VERSION 5.8 ;
BUSBITCHARS "[]" ;
DIVIDERCHAR "/" ;
UNITS
    DATABASE MICRONS 1000 ;
END UNITS

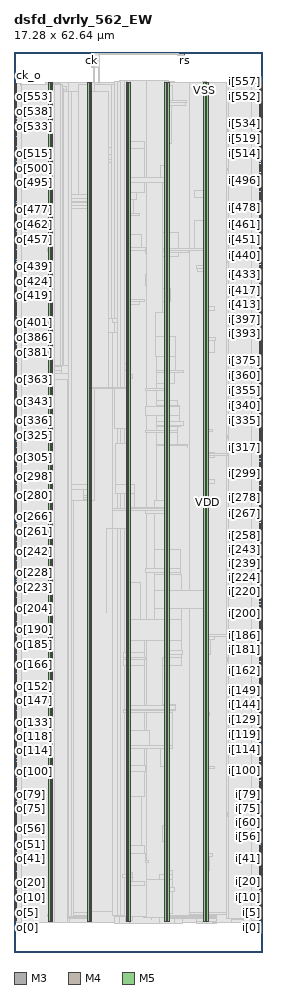
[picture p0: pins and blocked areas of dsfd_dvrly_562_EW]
MACRO dsfd_dvrly_562_EW
  FOREIGN dsfd_dvrly_562_EW 0 0 ;
  CLASS BLOCK ;
  SIZE 17.28 BY 62.64 ;
  PIN ck
    DIRECTION INPUT ;
    USE SIGNAL ;
    PORT
      LAYER M3 ;
        RECT  5.4 62.496 5.418 62.64 ;
    END
  END ck
  PIN ck_o
    DIRECTION OUTPUT ;
    USE SIGNAL ;
    PORT
      LAYER M4 ;
        RECT  0 60.432 0.192 60.456 ;
    END
  END ck_o
  PIN i[0]
    DIRECTION INPUT ;
    USE SIGNAL ;
    PORT
      LAYER M4 ;
        RECT  17.088 2.208 17.28 2.232 ;
    END
  END i[0]
  PIN i[100]
    DIRECTION INPUT ;
    USE SIGNAL ;
    PORT
      LAYER M4 ;
        RECT  17.088 12.624 17.28 12.648 ;
    END
  END i[100]
  PIN i[101]
    DIRECTION INPUT ;
    USE SIGNAL ;
    PORT
      LAYER M4 ;
        RECT  17.088 12.72 17.28 12.744 ;
    END
  END i[101]
  PIN i[102]
    DIRECTION INPUT ;
    USE SIGNAL ;
    PORT
      LAYER M4 ;
        RECT  17.088 12.816 17.28 12.84 ;
    END
  END i[102]
  PIN i[103]
    DIRECTION INPUT ;
    USE SIGNAL ;
    PORT
      LAYER M4 ;
        RECT  17.088 12.912 17.28 12.936 ;
    END
  END i[103]
  PIN i[104]
    DIRECTION INPUT ;
    USE SIGNAL ;
    PORT
      LAYER M4 ;
        RECT  17.088 13.008 17.28 13.032 ;
    END
  END i[104]
  PIN i[105]
    DIRECTION INPUT ;
    USE SIGNAL ;
    PORT
      LAYER M4 ;
        RECT  17.088 13.104 17.28 13.128 ;
    END
  END i[105]
  PIN i[106]
    DIRECTION INPUT ;
    USE SIGNAL ;
    PORT
      LAYER M4 ;
        RECT  17.088 13.2 17.28 13.224 ;
    END
  END i[106]
  PIN i[107]
    DIRECTION INPUT ;
    USE SIGNAL ;
    PORT
      LAYER M4 ;
        RECT  17.088 13.344 17.28 13.368 ;
    END
  END i[107]
  PIN i[108]
    DIRECTION INPUT ;
    USE SIGNAL ;
    PORT
      LAYER M4 ;
        RECT  17.088 13.44 17.28 13.464 ;
    END
  END i[108]
  PIN i[109]
    DIRECTION INPUT ;
    USE SIGNAL ;
    PORT
      LAYER M4 ;
        RECT  17.088 13.536 17.28 13.56 ;
    END
  END i[109]
  PIN i[10]
    DIRECTION INPUT ;
    USE SIGNAL ;
    PORT
      LAYER M4 ;
        RECT  17.088 3.264 17.28 3.288 ;
    END
  END i[10]
  PIN i[110]
    DIRECTION INPUT ;
    USE SIGNAL ;
    PORT
      LAYER M4 ;
        RECT  17.088 13.632 17.28 13.656 ;
    END
  END i[110]
  PIN i[111]
    DIRECTION INPUT ;
    USE SIGNAL ;
    PORT
      LAYER M4 ;
        RECT  17.088 13.728 17.28 13.752 ;
    END
  END i[111]
  PIN i[112]
    DIRECTION INPUT ;
    USE SIGNAL ;
    PORT
      LAYER M4 ;
        RECT  17.088 13.824 17.28 13.848 ;
    END
  END i[112]
  PIN i[113]
    DIRECTION INPUT ;
    USE SIGNAL ;
    PORT
      LAYER M4 ;
        RECT  17.088 13.968 17.28 13.992 ;
    END
  END i[113]
  PIN i[114]
    DIRECTION INPUT ;
    USE SIGNAL ;
    PORT
      LAYER M4 ;
        RECT  17.088 14.064 17.28 14.088 ;
    END
  END i[114]
  PIN i[115]
    DIRECTION INPUT ;
    USE SIGNAL ;
    PORT
      LAYER M4 ;
        RECT  17.088 14.16 17.28 14.184 ;
    END
  END i[115]
  PIN i[116]
    DIRECTION INPUT ;
    USE SIGNAL ;
    PORT
      LAYER M4 ;
        RECT  17.088 14.256 17.28 14.28 ;
    END
  END i[116]
  PIN i[117]
    DIRECTION INPUT ;
    USE SIGNAL ;
    PORT
      LAYER M4 ;
        RECT  17.088 14.352 17.28 14.376 ;
    END
  END i[117]
  PIN i[118]
    DIRECTION INPUT ;
    USE SIGNAL ;
    PORT
      LAYER M4 ;
        RECT  17.088 14.448 17.28 14.472 ;
    END
  END i[118]
  PIN i[119]
    DIRECTION INPUT ;
    USE SIGNAL ;
    PORT
      LAYER M4 ;
        RECT  17.088 14.592 17.28 14.616 ;
    END
  END i[119]
  PIN i[11]
    DIRECTION INPUT ;
    USE SIGNAL ;
    PORT
      LAYER M4 ;
        RECT  17.088 3.36 17.28 3.384 ;
    END
  END i[11]
  PIN i[120]
    DIRECTION INPUT ;
    USE SIGNAL ;
    PORT
      LAYER M4 ;
        RECT  17.088 14.688 17.28 14.712 ;
    END
  END i[120]
  PIN i[121]
    DIRECTION INPUT ;
    USE SIGNAL ;
    PORT
      LAYER M4 ;
        RECT  17.088 14.784 17.28 14.808 ;
    END
  END i[121]
  PIN i[122]
    DIRECTION INPUT ;
    USE SIGNAL ;
    PORT
      LAYER M4 ;
        RECT  17.088 14.88 17.28 14.904 ;
    END
  END i[122]
  PIN i[123]
    DIRECTION INPUT ;
    USE SIGNAL ;
    PORT
      LAYER M4 ;
        RECT  17.088 14.976 17.28 15 ;
    END
  END i[123]
  PIN i[124]
    DIRECTION INPUT ;
    USE SIGNAL ;
    PORT
      LAYER M4 ;
        RECT  17.088 15.072 17.28 15.096 ;
    END
  END i[124]
  PIN i[125]
    DIRECTION INPUT ;
    USE SIGNAL ;
    PORT
      LAYER M4 ;
        RECT  17.088 15.216 17.28 15.24 ;
    END
  END i[125]
  PIN i[126]
    DIRECTION INPUT ;
    USE SIGNAL ;
    PORT
      LAYER M4 ;
        RECT  17.088 15.312 17.28 15.336 ;
    END
  END i[126]
  PIN i[127]
    DIRECTION INPUT ;
    USE SIGNAL ;
    PORT
      LAYER M4 ;
        RECT  17.088 15.408 17.28 15.432 ;
    END
  END i[127]
  PIN i[128]
    DIRECTION INPUT ;
    USE SIGNAL ;
    PORT
      LAYER M4 ;
        RECT  17.088 15.504 17.28 15.528 ;
    END
  END i[128]
  PIN i[129]
    DIRECTION INPUT ;
    USE SIGNAL ;
    PORT
      LAYER M4 ;
        RECT  17.088 15.6 17.28 15.624 ;
    END
  END i[129]
  PIN i[12]
    DIRECTION INPUT ;
    USE SIGNAL ;
    PORT
      LAYER M4 ;
        RECT  17.088 3.456 17.28 3.48 ;
    END
  END i[12]
  PIN i[130]
    DIRECTION INPUT ;
    USE SIGNAL ;
    PORT
      LAYER M4 ;
        RECT  17.088 15.696 17.28 15.72 ;
    END
  END i[130]
  PIN i[131]
    DIRECTION INPUT ;
    USE SIGNAL ;
    PORT
      LAYER M4 ;
        RECT  17.088 15.84 17.28 15.864 ;
    END
  END i[131]
  PIN i[132]
    DIRECTION INPUT ;
    USE SIGNAL ;
    PORT
      LAYER M4 ;
        RECT  17.088 15.936 17.28 15.96 ;
    END
  END i[132]
  PIN i[133]
    DIRECTION INPUT ;
    USE SIGNAL ;
    PORT
      LAYER M4 ;
        RECT  17.088 16.032 17.28 16.056 ;
    END
  END i[133]
  PIN i[134]
    DIRECTION INPUT ;
    USE SIGNAL ;
    PORT
      LAYER M4 ;
        RECT  17.088 16.128 17.28 16.152 ;
    END
  END i[134]
  PIN i[135]
    DIRECTION INPUT ;
    USE SIGNAL ;
    PORT
      LAYER M4 ;
        RECT  17.088 16.224 17.28 16.248 ;
    END
  END i[135]
  PIN i[136]
    DIRECTION INPUT ;
    USE SIGNAL ;
    PORT
      LAYER M4 ;
        RECT  17.088 16.32 17.28 16.344 ;
    END
  END i[136]
  PIN i[137]
    DIRECTION INPUT ;
    USE SIGNAL ;
    PORT
      LAYER M4 ;
        RECT  17.088 16.464 17.28 16.488 ;
    END
  END i[137]
  PIN i[138]
    DIRECTION INPUT ;
    USE SIGNAL ;
    PORT
      LAYER M4 ;
        RECT  17.088 16.56 17.28 16.584 ;
    END
  END i[138]
  PIN i[139]
    DIRECTION INPUT ;
    USE SIGNAL ;
    PORT
      LAYER M4 ;
        RECT  17.088 16.656 17.28 16.68 ;
    END
  END i[139]
  PIN i[13]
    DIRECTION INPUT ;
    USE SIGNAL ;
    PORT
      LAYER M4 ;
        RECT  17.088 3.552 17.28 3.576 ;
    END
  END i[13]
  PIN i[140]
    DIRECTION INPUT ;
    USE SIGNAL ;
    PORT
      LAYER M4 ;
        RECT  17.088 16.752 17.28 16.776 ;
    END
  END i[140]
  PIN i[141]
    DIRECTION INPUT ;
    USE SIGNAL ;
    PORT
      LAYER M4 ;
        RECT  17.088 16.848 17.28 16.872 ;
    END
  END i[141]
  PIN i[142]
    DIRECTION INPUT ;
    USE SIGNAL ;
    PORT
      LAYER M4 ;
        RECT  17.088 16.944 17.28 16.968 ;
    END
  END i[142]
  PIN i[143]
    DIRECTION INPUT ;
    USE SIGNAL ;
    PORT
      LAYER M4 ;
        RECT  17.088 17.04 17.28 17.064 ;
    END
  END i[143]
  PIN i[144]
    DIRECTION INPUT ;
    USE SIGNAL ;
    PORT
      LAYER M4 ;
        RECT  17.088 17.184 17.28 17.208 ;
    END
  END i[144]
  PIN i[145]
    DIRECTION INPUT ;
    USE SIGNAL ;
    PORT
      LAYER M4 ;
        RECT  17.088 17.28 17.28 17.304 ;
    END
  END i[145]
  PIN i[146]
    DIRECTION INPUT ;
    USE SIGNAL ;
    PORT
      LAYER M4 ;
        RECT  17.088 17.376 17.28 17.4 ;
    END
  END i[146]
  PIN i[147]
    DIRECTION INPUT ;
    USE SIGNAL ;
    PORT
      LAYER M4 ;
        RECT  17.088 17.472 17.28 17.496 ;
    END
  END i[147]
  PIN i[148]
    DIRECTION INPUT ;
    USE SIGNAL ;
    PORT
      LAYER M4 ;
        RECT  17.088 17.568 17.28 17.592 ;
    END
  END i[148]
  PIN i[149]
    DIRECTION INPUT ;
    USE SIGNAL ;
    PORT
      LAYER M4 ;
        RECT  17.088 17.664 17.28 17.688 ;
    END
  END i[149]
  PIN i[14]
    DIRECTION INPUT ;
    USE SIGNAL ;
    PORT
      LAYER M4 ;
        RECT  17.088 3.696 17.28 3.72 ;
    END
  END i[14]
  PIN i[150]
    DIRECTION INPUT ;
    USE SIGNAL ;
    PORT
      LAYER M4 ;
        RECT  17.088 17.808 17.28 17.832 ;
    END
  END i[150]
  PIN i[151]
    DIRECTION INPUT ;
    USE SIGNAL ;
    PORT
      LAYER M4 ;
        RECT  17.088 17.904 17.28 17.928 ;
    END
  END i[151]
  PIN i[152]
    DIRECTION INPUT ;
    USE SIGNAL ;
    PORT
      LAYER M4 ;
        RECT  17.088 18 17.28 18.024 ;
    END
  END i[152]
  PIN i[153]
    DIRECTION INPUT ;
    USE SIGNAL ;
    PORT
      LAYER M4 ;
        RECT  17.088 18.096 17.28 18.12 ;
    END
  END i[153]
  PIN i[154]
    DIRECTION INPUT ;
    USE SIGNAL ;
    PORT
      LAYER M4 ;
        RECT  17.088 18.192 17.28 18.216 ;
    END
  END i[154]
  PIN i[155]
    DIRECTION INPUT ;
    USE SIGNAL ;
    PORT
      LAYER M4 ;
        RECT  17.088 18.288 17.28 18.312 ;
    END
  END i[155]
  PIN i[156]
    DIRECTION INPUT ;
    USE SIGNAL ;
    PORT
      LAYER M4 ;
        RECT  17.088 18.432 17.28 18.456 ;
    END
  END i[156]
  PIN i[157]
    DIRECTION INPUT ;
    USE SIGNAL ;
    PORT
      LAYER M4 ;
        RECT  17.088 18.528 17.28 18.552 ;
    END
  END i[157]
  PIN i[158]
    DIRECTION INPUT ;
    USE SIGNAL ;
    PORT
      LAYER M4 ;
        RECT  17.088 18.624 17.28 18.648 ;
    END
  END i[158]
  PIN i[159]
    DIRECTION INPUT ;
    USE SIGNAL ;
    PORT
      LAYER M4 ;
        RECT  17.088 18.72 17.28 18.744 ;
    END
  END i[159]
  PIN i[15]
    DIRECTION INPUT ;
    USE SIGNAL ;
    PORT
      LAYER M4 ;
        RECT  17.088 3.792 17.28 3.816 ;
    END
  END i[15]
  PIN i[160]
    DIRECTION INPUT ;
    USE SIGNAL ;
    PORT
      LAYER M4 ;
        RECT  17.088 18.816 17.28 18.84 ;
    END
  END i[160]
  PIN i[161]
    DIRECTION INPUT ;
    USE SIGNAL ;
    PORT
      LAYER M4 ;
        RECT  17.088 18.912 17.28 18.936 ;
    END
  END i[161]
  PIN i[162]
    DIRECTION INPUT ;
    USE SIGNAL ;
    PORT
      LAYER M4 ;
        RECT  17.088 19.056 17.28 19.08 ;
    END
  END i[162]
  PIN i[163]
    DIRECTION INPUT ;
    USE SIGNAL ;
    PORT
      LAYER M4 ;
        RECT  17.088 19.152 17.28 19.176 ;
    END
  END i[163]
  PIN i[164]
    DIRECTION INPUT ;
    USE SIGNAL ;
    PORT
      LAYER M4 ;
        RECT  17.088 19.248 17.28 19.272 ;
    END
  END i[164]
  PIN i[165]
    DIRECTION INPUT ;
    USE SIGNAL ;
    PORT
      LAYER M4 ;
        RECT  17.088 19.344 17.28 19.368 ;
    END
  END i[165]
  PIN i[166]
    DIRECTION INPUT ;
    USE SIGNAL ;
    PORT
      LAYER M4 ;
        RECT  17.088 19.44 17.28 19.464 ;
    END
  END i[166]
  PIN i[167]
    DIRECTION INPUT ;
    USE SIGNAL ;
    PORT
      LAYER M4 ;
        RECT  17.088 19.536 17.28 19.56 ;
    END
  END i[167]
  PIN i[168]
    DIRECTION INPUT ;
    USE SIGNAL ;
    PORT
      LAYER M4 ;
        RECT  17.088 19.68 17.28 19.704 ;
    END
  END i[168]
  PIN i[169]
    DIRECTION INPUT ;
    USE SIGNAL ;
    PORT
      LAYER M4 ;
        RECT  17.088 19.776 17.28 19.8 ;
    END
  END i[169]
  PIN i[16]
    DIRECTION INPUT ;
    USE SIGNAL ;
    PORT
      LAYER M4 ;
        RECT  17.088 3.888 17.28 3.912 ;
    END
  END i[16]
  PIN i[170]
    DIRECTION INPUT ;
    USE SIGNAL ;
    PORT
      LAYER M4 ;
        RECT  17.088 19.872 17.28 19.896 ;
    END
  END i[170]
  PIN i[171]
    DIRECTION INPUT ;
    USE SIGNAL ;
    PORT
      LAYER M4 ;
        RECT  17.088 19.968 17.28 19.992 ;
    END
  END i[171]
  PIN i[172]
    DIRECTION INPUT ;
    USE SIGNAL ;
    PORT
      LAYER M4 ;
        RECT  17.088 20.064 17.28 20.088 ;
    END
  END i[172]
  PIN i[173]
    DIRECTION INPUT ;
    USE SIGNAL ;
    PORT
      LAYER M4 ;
        RECT  17.088 20.16 17.28 20.184 ;
    END
  END i[173]
  PIN i[174]
    DIRECTION INPUT ;
    USE SIGNAL ;
    PORT
      LAYER M4 ;
        RECT  17.088 20.304 17.28 20.328 ;
    END
  END i[174]
  PIN i[175]
    DIRECTION INPUT ;
    USE SIGNAL ;
    PORT
      LAYER M4 ;
        RECT  17.088 20.4 17.28 20.424 ;
    END
  END i[175]
  PIN i[176]
    DIRECTION INPUT ;
    USE SIGNAL ;
    PORT
      LAYER M4 ;
        RECT  17.088 20.496 17.28 20.52 ;
    END
  END i[176]
  PIN i[177]
    DIRECTION INPUT ;
    USE SIGNAL ;
    PORT
      LAYER M4 ;
        RECT  17.088 20.592 17.28 20.616 ;
    END
  END i[177]
  PIN i[178]
    DIRECTION INPUT ;
    USE SIGNAL ;
    PORT
      LAYER M4 ;
        RECT  17.088 20.688 17.28 20.712 ;
    END
  END i[178]
  PIN i[179]
    DIRECTION INPUT ;
    USE SIGNAL ;
    PORT
      LAYER M4 ;
        RECT  17.088 20.784 17.28 20.808 ;
    END
  END i[179]
  PIN i[17]
    DIRECTION INPUT ;
    USE SIGNAL ;
    PORT
      LAYER M4 ;
        RECT  17.088 3.984 17.28 4.008 ;
    END
  END i[17]
  PIN i[180]
    DIRECTION INPUT ;
    USE SIGNAL ;
    PORT
      LAYER M4 ;
        RECT  17.088 20.88 17.28 20.904 ;
    END
  END i[180]
  PIN i[181]
    DIRECTION INPUT ;
    USE SIGNAL ;
    PORT
      LAYER M4 ;
        RECT  17.088 21.024 17.28 21.048 ;
    END
  END i[181]
  PIN i[182]
    DIRECTION INPUT ;
    USE SIGNAL ;
    PORT
      LAYER M4 ;
        RECT  17.088 21.12 17.28 21.144 ;
    END
  END i[182]
  PIN i[183]
    DIRECTION INPUT ;
    USE SIGNAL ;
    PORT
      LAYER M4 ;
        RECT  17.088 21.216 17.28 21.24 ;
    END
  END i[183]
  PIN i[184]
    DIRECTION INPUT ;
    USE SIGNAL ;
    PORT
      LAYER M4 ;
        RECT  17.088 21.312 17.28 21.336 ;
    END
  END i[184]
  PIN i[185]
    DIRECTION INPUT ;
    USE SIGNAL ;
    PORT
      LAYER M4 ;
        RECT  17.088 21.408 17.28 21.432 ;
    END
  END i[185]
  PIN i[186]
    DIRECTION INPUT ;
    USE SIGNAL ;
    PORT
      LAYER M4 ;
        RECT  17.088 21.504 17.28 21.528 ;
    END
  END i[186]
  PIN i[187]
    DIRECTION INPUT ;
    USE SIGNAL ;
    PORT
      LAYER M4 ;
        RECT  17.088 21.648 17.28 21.672 ;
    END
  END i[187]
  PIN i[188]
    DIRECTION INPUT ;
    USE SIGNAL ;
    PORT
      LAYER M4 ;
        RECT  17.088 21.744 17.28 21.768 ;
    END
  END i[188]
  PIN i[189]
    DIRECTION INPUT ;
    USE SIGNAL ;
    PORT
      LAYER M4 ;
        RECT  17.088 21.84 17.28 21.864 ;
    END
  END i[189]
  PIN i[18]
    DIRECTION INPUT ;
    USE SIGNAL ;
    PORT
      LAYER M4 ;
        RECT  17.088 4.08 17.28 4.104 ;
    END
  END i[18]
  PIN i[190]
    DIRECTION INPUT ;
    USE SIGNAL ;
    PORT
      LAYER M4 ;
        RECT  17.088 21.936 17.28 21.96 ;
    END
  END i[190]
  PIN i[191]
    DIRECTION INPUT ;
    USE SIGNAL ;
    PORT
      LAYER M4 ;
        RECT  17.088 22.032 17.28 22.056 ;
    END
  END i[191]
  PIN i[192]
    DIRECTION INPUT ;
    USE SIGNAL ;
    PORT
      LAYER M4 ;
        RECT  17.088 22.128 17.28 22.152 ;
    END
  END i[192]
  PIN i[193]
    DIRECTION INPUT ;
    USE SIGNAL ;
    PORT
      LAYER M4 ;
        RECT  17.088 22.272 17.28 22.296 ;
    END
  END i[193]
  PIN i[194]
    DIRECTION INPUT ;
    USE SIGNAL ;
    PORT
      LAYER M4 ;
        RECT  17.088 22.368 17.28 22.392 ;
    END
  END i[194]
  PIN i[195]
    DIRECTION INPUT ;
    USE SIGNAL ;
    PORT
      LAYER M4 ;
        RECT  17.088 22.464 17.28 22.488 ;
    END
  END i[195]
  PIN i[196]
    DIRECTION INPUT ;
    USE SIGNAL ;
    PORT
      LAYER M4 ;
        RECT  17.088 22.56 17.28 22.584 ;
    END
  END i[196]
  PIN i[197]
    DIRECTION INPUT ;
    USE SIGNAL ;
    PORT
      LAYER M4 ;
        RECT  17.088 22.656 17.28 22.68 ;
    END
  END i[197]
  PIN i[198]
    DIRECTION INPUT ;
    USE SIGNAL ;
    PORT
      LAYER M4 ;
        RECT  17.088 22.752 17.28 22.776 ;
    END
  END i[198]
  PIN i[199]
    DIRECTION INPUT ;
    USE SIGNAL ;
    PORT
      LAYER M4 ;
        RECT  17.088 22.896 17.28 22.92 ;
    END
  END i[199]
  PIN i[19]
    DIRECTION INPUT ;
    USE SIGNAL ;
    PORT
      LAYER M4 ;
        RECT  17.088 4.176 17.28 4.2 ;
    END
  END i[19]
  PIN i[1]
    DIRECTION INPUT ;
    USE SIGNAL ;
    PORT
      LAYER M4 ;
        RECT  17.088 2.304 17.28 2.328 ;
    END
  END i[1]
  PIN i[200]
    DIRECTION INPUT ;
    USE SIGNAL ;
    PORT
      LAYER M4 ;
        RECT  17.088 22.992 17.28 23.016 ;
    END
  END i[200]
  PIN i[201]
    DIRECTION INPUT ;
    USE SIGNAL ;
    PORT
      LAYER M4 ;
        RECT  17.088 23.088 17.28 23.112 ;
    END
  END i[201]
  PIN i[202]
    DIRECTION INPUT ;
    USE SIGNAL ;
    PORT
      LAYER M4 ;
        RECT  17.088 23.184 17.28 23.208 ;
    END
  END i[202]
  PIN i[203]
    DIRECTION INPUT ;
    USE SIGNAL ;
    PORT
      LAYER M4 ;
        RECT  17.088 23.28 17.28 23.304 ;
    END
  END i[203]
  PIN i[204]
    DIRECTION INPUT ;
    USE SIGNAL ;
    PORT
      LAYER M4 ;
        RECT  17.088 23.376 17.28 23.4 ;
    END
  END i[204]
  PIN i[205]
    DIRECTION INPUT ;
    USE SIGNAL ;
    PORT
      LAYER M4 ;
        RECT  17.088 23.52 17.28 23.544 ;
    END
  END i[205]
  PIN i[206]
    DIRECTION INPUT ;
    USE SIGNAL ;
    PORT
      LAYER M4 ;
        RECT  17.088 23.616 17.28 23.64 ;
    END
  END i[206]
  PIN i[207]
    DIRECTION INPUT ;
    USE SIGNAL ;
    PORT
      LAYER M4 ;
        RECT  17.088 23.712 17.28 23.736 ;
    END
  END i[207]
  PIN i[208]
    DIRECTION INPUT ;
    USE SIGNAL ;
    PORT
      LAYER M4 ;
        RECT  17.088 23.808 17.28 23.832 ;
    END
  END i[208]
  PIN i[209]
    DIRECTION INPUT ;
    USE SIGNAL ;
    PORT
      LAYER M4 ;
        RECT  17.088 23.904 17.28 23.928 ;
    END
  END i[209]
  PIN i[20]
    DIRECTION INPUT ;
    USE SIGNAL ;
    PORT
      LAYER M4 ;
        RECT  17.088 4.32 17.28 4.344 ;
    END
  END i[20]
  PIN i[210]
    DIRECTION INPUT ;
    USE SIGNAL ;
    PORT
      LAYER M4 ;
        RECT  17.088 24 17.28 24.024 ;
    END
  END i[210]
  PIN i[211]
    DIRECTION INPUT ;
    USE SIGNAL ;
    PORT
      LAYER M4 ;
        RECT  17.088 24.096 17.28 24.12 ;
    END
  END i[211]
  PIN i[212]
    DIRECTION INPUT ;
    USE SIGNAL ;
    PORT
      LAYER M4 ;
        RECT  17.088 24.24 17.28 24.264 ;
    END
  END i[212]
  PIN i[213]
    DIRECTION INPUT ;
    USE SIGNAL ;
    PORT
      LAYER M4 ;
        RECT  17.088 24.336 17.28 24.36 ;
    END
  END i[213]
  PIN i[214]
    DIRECTION INPUT ;
    USE SIGNAL ;
    PORT
      LAYER M4 ;
        RECT  17.088 24.432 17.28 24.456 ;
    END
  END i[214]
  PIN i[215]
    DIRECTION INPUT ;
    USE SIGNAL ;
    PORT
      LAYER M4 ;
        RECT  17.088 24.528 17.28 24.552 ;
    END
  END i[215]
  PIN i[216]
    DIRECTION INPUT ;
    USE SIGNAL ;
    PORT
      LAYER M4 ;
        RECT  17.088 24.624 17.28 24.648 ;
    END
  END i[216]
  PIN i[217]
    DIRECTION INPUT ;
    USE SIGNAL ;
    PORT
      LAYER M4 ;
        RECT  17.088 24.72 17.28 24.744 ;
    END
  END i[217]
  PIN i[218]
    DIRECTION INPUT ;
    USE SIGNAL ;
    PORT
      LAYER M4 ;
        RECT  17.088 24.864 17.28 24.888 ;
    END
  END i[218]
  PIN i[219]
    DIRECTION INPUT ;
    USE SIGNAL ;
    PORT
      LAYER M4 ;
        RECT  17.088 24.96 17.28 24.984 ;
    END
  END i[219]
  PIN i[21]
    DIRECTION INPUT ;
    USE SIGNAL ;
    PORT
      LAYER M4 ;
        RECT  17.088 4.416 17.28 4.44 ;
    END
  END i[21]
  PIN i[220]
    DIRECTION INPUT ;
    USE SIGNAL ;
    PORT
      LAYER M4 ;
        RECT  17.088 25.056 17.28 25.08 ;
    END
  END i[220]
  PIN i[221]
    DIRECTION INPUT ;
    USE SIGNAL ;
    PORT
      LAYER M4 ;
        RECT  17.088 25.152 17.28 25.176 ;
    END
  END i[221]
  PIN i[222]
    DIRECTION INPUT ;
    USE SIGNAL ;
    PORT
      LAYER M4 ;
        RECT  17.088 25.248 17.28 25.272 ;
    END
  END i[222]
  PIN i[223]
    DIRECTION INPUT ;
    USE SIGNAL ;
    PORT
      LAYER M4 ;
        RECT  17.088 25.344 17.28 25.368 ;
    END
  END i[223]
  PIN i[224]
    DIRECTION INPUT ;
    USE SIGNAL ;
    PORT
      LAYER M4 ;
        RECT  17.088 25.488 17.28 25.512 ;
    END
  END i[224]
  PIN i[225]
    DIRECTION INPUT ;
    USE SIGNAL ;
    PORT
      LAYER M4 ;
        RECT  17.088 25.584 17.28 25.608 ;
    END
  END i[225]
  PIN i[226]
    DIRECTION INPUT ;
    USE SIGNAL ;
    PORT
      LAYER M4 ;
        RECT  17.088 25.68 17.28 25.704 ;
    END
  END i[226]
  PIN i[227]
    DIRECTION INPUT ;
    USE SIGNAL ;
    PORT
      LAYER M4 ;
        RECT  17.088 25.776 17.28 25.8 ;
    END
  END i[227]
  PIN i[228]
    DIRECTION INPUT ;
    USE SIGNAL ;
    PORT
      LAYER M4 ;
        RECT  17.088 25.872 17.28 25.896 ;
    END
  END i[228]
  PIN i[229]
    DIRECTION INPUT ;
    USE SIGNAL ;
    PORT
      LAYER M4 ;
        RECT  17.088 25.968 17.28 25.992 ;
    END
  END i[229]
  PIN i[22]
    DIRECTION INPUT ;
    USE SIGNAL ;
    PORT
      LAYER M4 ;
        RECT  17.088 4.512 17.28 4.536 ;
    END
  END i[22]
  PIN i[230]
    DIRECTION INPUT ;
    USE SIGNAL ;
    PORT
      LAYER M4 ;
        RECT  17.088 26.112 17.28 26.136 ;
    END
  END i[230]
  PIN i[231]
    DIRECTION INPUT ;
    USE SIGNAL ;
    PORT
      LAYER M4 ;
        RECT  17.088 26.208 17.28 26.232 ;
    END
  END i[231]
  PIN i[232]
    DIRECTION INPUT ;
    USE SIGNAL ;
    PORT
      LAYER M4 ;
        RECT  17.088 26.304 17.28 26.328 ;
    END
  END i[232]
  PIN i[233]
    DIRECTION INPUT ;
    USE SIGNAL ;
    PORT
      LAYER M4 ;
        RECT  17.088 26.4 17.28 26.424 ;
    END
  END i[233]
  PIN i[234]
    DIRECTION INPUT ;
    USE SIGNAL ;
    PORT
      LAYER M4 ;
        RECT  17.088 26.496 17.28 26.52 ;
    END
  END i[234]
  PIN i[235]
    DIRECTION INPUT ;
    USE SIGNAL ;
    PORT
      LAYER M4 ;
        RECT  17.088 26.592 17.28 26.616 ;
    END
  END i[235]
  PIN i[236]
    DIRECTION INPUT ;
    USE SIGNAL ;
    PORT
      LAYER M4 ;
        RECT  17.088 26.736 17.28 26.76 ;
    END
  END i[236]
  PIN i[237]
    DIRECTION INPUT ;
    USE SIGNAL ;
    PORT
      LAYER M4 ;
        RECT  17.088 26.832 17.28 26.856 ;
    END
  END i[237]
  PIN i[238]
    DIRECTION INPUT ;
    USE SIGNAL ;
    PORT
      LAYER M4 ;
        RECT  17.088 26.928 17.28 26.952 ;
    END
  END i[238]
  PIN i[239]
    DIRECTION INPUT ;
    USE SIGNAL ;
    PORT
      LAYER M4 ;
        RECT  17.088 27.024 17.28 27.048 ;
    END
  END i[239]
  PIN i[23]
    DIRECTION INPUT ;
    USE SIGNAL ;
    PORT
      LAYER M4 ;
        RECT  17.088 4.608 17.28 4.632 ;
    END
  END i[23]
  PIN i[240]
    DIRECTION INPUT ;
    USE SIGNAL ;
    PORT
      LAYER M4 ;
        RECT  17.088 27.12 17.28 27.144 ;
    END
  END i[240]
  PIN i[241]
    DIRECTION INPUT ;
    USE SIGNAL ;
    PORT
      LAYER M4 ;
        RECT  17.088 27.216 17.28 27.24 ;
    END
  END i[241]
  PIN i[242]
    DIRECTION INPUT ;
    USE SIGNAL ;
    PORT
      LAYER M4 ;
        RECT  17.088 27.36 17.28 27.384 ;
    END
  END i[242]
  PIN i[243]
    DIRECTION INPUT ;
    USE SIGNAL ;
    PORT
      LAYER M4 ;
        RECT  17.088 27.456 17.28 27.48 ;
    END
  END i[243]
  PIN i[244]
    DIRECTION INPUT ;
    USE SIGNAL ;
    PORT
      LAYER M4 ;
        RECT  17.088 27.552 17.28 27.576 ;
    END
  END i[244]
  PIN i[245]
    DIRECTION INPUT ;
    USE SIGNAL ;
    PORT
      LAYER M4 ;
        RECT  17.088 27.648 17.28 27.672 ;
    END
  END i[245]
  PIN i[246]
    DIRECTION INPUT ;
    USE SIGNAL ;
    PORT
      LAYER M4 ;
        RECT  17.088 27.744 17.28 27.768 ;
    END
  END i[246]
  PIN i[247]
    DIRECTION INPUT ;
    USE SIGNAL ;
    PORT
      LAYER M4 ;
        RECT  17.088 27.84 17.28 27.864 ;
    END
  END i[247]
  PIN i[248]
    DIRECTION INPUT ;
    USE SIGNAL ;
    PORT
      LAYER M4 ;
        RECT  17.088 27.936 17.28 27.96 ;
    END
  END i[248]
  PIN i[249]
    DIRECTION INPUT ;
    USE SIGNAL ;
    PORT
      LAYER M4 ;
        RECT  17.088 28.08 17.28 28.104 ;
    END
  END i[249]
  PIN i[24]
    DIRECTION INPUT ;
    USE SIGNAL ;
    PORT
      LAYER M4 ;
        RECT  17.088 4.704 17.28 4.728 ;
    END
  END i[24]
  PIN i[250]
    DIRECTION INPUT ;
    USE SIGNAL ;
    PORT
      LAYER M4 ;
        RECT  17.088 28.176 17.28 28.2 ;
    END
  END i[250]
  PIN i[251]
    DIRECTION INPUT ;
    USE SIGNAL ;
    PORT
      LAYER M4 ;
        RECT  17.088 28.272 17.28 28.296 ;
    END
  END i[251]
  PIN i[252]
    DIRECTION INPUT ;
    USE SIGNAL ;
    PORT
      LAYER M4 ;
        RECT  17.088 28.368 17.28 28.392 ;
    END
  END i[252]
  PIN i[253]
    DIRECTION INPUT ;
    USE SIGNAL ;
    PORT
      LAYER M4 ;
        RECT  17.088 28.464 17.28 28.488 ;
    END
  END i[253]
  PIN i[254]
    DIRECTION INPUT ;
    USE SIGNAL ;
    PORT
      LAYER M4 ;
        RECT  17.088 28.56 17.28 28.584 ;
    END
  END i[254]
  PIN i[255]
    DIRECTION INPUT ;
    USE SIGNAL ;
    PORT
      LAYER M4 ;
        RECT  17.088 28.704 17.28 28.728 ;
    END
  END i[255]
  PIN i[256]
    DIRECTION INPUT ;
    USE SIGNAL ;
    PORT
      LAYER M4 ;
        RECT  17.088 28.8 17.28 28.824 ;
    END
  END i[256]
  PIN i[257]
    DIRECTION INPUT ;
    USE SIGNAL ;
    PORT
      LAYER M4 ;
        RECT  17.088 28.896 17.28 28.92 ;
    END
  END i[257]
  PIN i[258]
    DIRECTION INPUT ;
    USE SIGNAL ;
    PORT
      LAYER M4 ;
        RECT  17.088 28.992 17.28 29.016 ;
    END
  END i[258]
  PIN i[259]
    DIRECTION INPUT ;
    USE SIGNAL ;
    PORT
      LAYER M4 ;
        RECT  17.088 29.088 17.28 29.112 ;
    END
  END i[259]
  PIN i[25]
    DIRECTION INPUT ;
    USE SIGNAL ;
    PORT
      LAYER M4 ;
        RECT  17.088 4.8 17.28 4.824 ;
    END
  END i[25]
  PIN i[260]
    DIRECTION INPUT ;
    USE SIGNAL ;
    PORT
      LAYER M4 ;
        RECT  17.088 29.184 17.28 29.208 ;
    END
  END i[260]
  PIN i[261]
    DIRECTION INPUT ;
    USE SIGNAL ;
    PORT
      LAYER M4 ;
        RECT  17.088 29.328 17.28 29.352 ;
    END
  END i[261]
  PIN i[262]
    DIRECTION INPUT ;
    USE SIGNAL ;
    PORT
      LAYER M4 ;
        RECT  17.088 29.424 17.28 29.448 ;
    END
  END i[262]
  PIN i[263]
    DIRECTION INPUT ;
    USE SIGNAL ;
    PORT
      LAYER M4 ;
        RECT  17.088 29.52 17.28 29.544 ;
    END
  END i[263]
  PIN i[264]
    DIRECTION INPUT ;
    USE SIGNAL ;
    PORT
      LAYER M4 ;
        RECT  17.088 29.616 17.28 29.64 ;
    END
  END i[264]
  PIN i[265]
    DIRECTION INPUT ;
    USE SIGNAL ;
    PORT
      LAYER M4 ;
        RECT  17.088 29.712 17.28 29.736 ;
    END
  END i[265]
  PIN i[266]
    DIRECTION INPUT ;
    USE SIGNAL ;
    PORT
      LAYER M4 ;
        RECT  17.088 29.808 17.28 29.832 ;
    END
  END i[266]
  PIN i[267]
    DIRECTION INPUT ;
    USE SIGNAL ;
    PORT
      LAYER M4 ;
        RECT  17.088 29.952 17.28 29.976 ;
    END
  END i[267]
  PIN i[268]
    DIRECTION INPUT ;
    USE SIGNAL ;
    PORT
      LAYER M4 ;
        RECT  17.088 30.048 17.28 30.072 ;
    END
  END i[268]
  PIN i[269]
    DIRECTION INPUT ;
    USE SIGNAL ;
    PORT
      LAYER M4 ;
        RECT  17.088 30.144 17.28 30.168 ;
    END
  END i[269]
  PIN i[26]
    DIRECTION INPUT ;
    USE SIGNAL ;
    PORT
      LAYER M4 ;
        RECT  17.088 4.944 17.28 4.968 ;
    END
  END i[26]
  PIN i[270]
    DIRECTION INPUT ;
    USE SIGNAL ;
    PORT
      LAYER M4 ;
        RECT  17.088 30.24 17.28 30.264 ;
    END
  END i[270]
  PIN i[271]
    DIRECTION INPUT ;
    USE SIGNAL ;
    PORT
      LAYER M4 ;
        RECT  17.088 30.336 17.28 30.36 ;
    END
  END i[271]
  PIN i[272]
    DIRECTION INPUT ;
    USE SIGNAL ;
    PORT
      LAYER M4 ;
        RECT  17.088 30.432 17.28 30.456 ;
    END
  END i[272]
  PIN i[273]
    DIRECTION INPUT ;
    USE SIGNAL ;
    PORT
      LAYER M4 ;
        RECT  17.088 30.576 17.28 30.6 ;
    END
  END i[273]
  PIN i[274]
    DIRECTION INPUT ;
    USE SIGNAL ;
    PORT
      LAYER M4 ;
        RECT  17.088 30.672 17.28 30.696 ;
    END
  END i[274]
  PIN i[275]
    DIRECTION INPUT ;
    USE SIGNAL ;
    PORT
      LAYER M4 ;
        RECT  17.088 30.768 17.28 30.792 ;
    END
  END i[275]
  PIN i[276]
    DIRECTION INPUT ;
    USE SIGNAL ;
    PORT
      LAYER M4 ;
        RECT  17.088 30.864 17.28 30.888 ;
    END
  END i[276]
  PIN i[277]
    DIRECTION INPUT ;
    USE SIGNAL ;
    PORT
      LAYER M4 ;
        RECT  17.088 30.96 17.28 30.984 ;
    END
  END i[277]
  PIN i[278]
    DIRECTION INPUT ;
    USE SIGNAL ;
    PORT
      LAYER M4 ;
        RECT  17.088 31.056 17.28 31.08 ;
    END
  END i[278]
  PIN i[279]
    DIRECTION INPUT ;
    USE SIGNAL ;
    PORT
      LAYER M4 ;
        RECT  17.088 31.2 17.28 31.224 ;
    END
  END i[279]
  PIN i[27]
    DIRECTION INPUT ;
    USE SIGNAL ;
    PORT
      LAYER M4 ;
        RECT  17.088 5.04 17.28 5.064 ;
    END
  END i[27]
  PIN i[280]
    DIRECTION INPUT ;
    USE SIGNAL ;
    PORT
      LAYER M4 ;
        RECT  17.088 31.296 17.28 31.32 ;
    END
  END i[280]
  PIN i[281]
    DIRECTION INPUT ;
    USE SIGNAL ;
    PORT
      LAYER M4 ;
        RECT  17.088 31.392 17.28 31.416 ;
    END
  END i[281]
  PIN i[282]
    DIRECTION INPUT ;
    USE SIGNAL ;
    PORT
      LAYER M4 ;
        RECT  17.088 31.488 17.28 31.512 ;
    END
  END i[282]
  PIN i[283]
    DIRECTION INPUT ;
    USE SIGNAL ;
    PORT
      LAYER M4 ;
        RECT  17.088 31.584 17.28 31.608 ;
    END
  END i[283]
  PIN i[284]
    DIRECTION INPUT ;
    USE SIGNAL ;
    PORT
      LAYER M4 ;
        RECT  17.088 31.68 17.28 31.704 ;
    END
  END i[284]
  PIN i[285]
    DIRECTION INPUT ;
    USE SIGNAL ;
    PORT
      LAYER M4 ;
        RECT  17.088 31.776 17.28 31.8 ;
    END
  END i[285]
  PIN i[286]
    DIRECTION INPUT ;
    USE SIGNAL ;
    PORT
      LAYER M4 ;
        RECT  17.088 31.92 17.28 31.944 ;
    END
  END i[286]
  PIN i[287]
    DIRECTION INPUT ;
    USE SIGNAL ;
    PORT
      LAYER M4 ;
        RECT  17.088 32.016 17.28 32.04 ;
    END
  END i[287]
  PIN i[288]
    DIRECTION INPUT ;
    USE SIGNAL ;
    PORT
      LAYER M4 ;
        RECT  17.088 32.112 17.28 32.136 ;
    END
  END i[288]
  PIN i[289]
    DIRECTION INPUT ;
    USE SIGNAL ;
    PORT
      LAYER M4 ;
        RECT  17.088 32.208 17.28 32.232 ;
    END
  END i[289]
  PIN i[28]
    DIRECTION INPUT ;
    USE SIGNAL ;
    PORT
      LAYER M4 ;
        RECT  17.088 5.136 17.28 5.16 ;
    END
  END i[28]
  PIN i[290]
    DIRECTION INPUT ;
    USE SIGNAL ;
    PORT
      LAYER M4 ;
        RECT  17.088 32.304 17.28 32.328 ;
    END
  END i[290]
  PIN i[291]
    DIRECTION INPUT ;
    USE SIGNAL ;
    PORT
      LAYER M4 ;
        RECT  17.088 32.4 17.28 32.424 ;
    END
  END i[291]
  PIN i[292]
    DIRECTION INPUT ;
    USE SIGNAL ;
    PORT
      LAYER M4 ;
        RECT  17.088 32.544 17.28 32.568 ;
    END
  END i[292]
  PIN i[293]
    DIRECTION INPUT ;
    USE SIGNAL ;
    PORT
      LAYER M4 ;
        RECT  17.088 32.64 17.28 32.664 ;
    END
  END i[293]
  PIN i[294]
    DIRECTION INPUT ;
    USE SIGNAL ;
    PORT
      LAYER M4 ;
        RECT  17.088 32.736 17.28 32.76 ;
    END
  END i[294]
  PIN i[295]
    DIRECTION INPUT ;
    USE SIGNAL ;
    PORT
      LAYER M4 ;
        RECT  17.088 32.832 17.28 32.856 ;
    END
  END i[295]
  PIN i[296]
    DIRECTION INPUT ;
    USE SIGNAL ;
    PORT
      LAYER M4 ;
        RECT  17.088 32.928 17.28 32.952 ;
    END
  END i[296]
  PIN i[297]
    DIRECTION INPUT ;
    USE SIGNAL ;
    PORT
      LAYER M4 ;
        RECT  17.088 33.024 17.28 33.048 ;
    END
  END i[297]
  PIN i[298]
    DIRECTION INPUT ;
    USE SIGNAL ;
    PORT
      LAYER M4 ;
        RECT  17.088 33.168 17.28 33.192 ;
    END
  END i[298]
  PIN i[299]
    DIRECTION INPUT ;
    USE SIGNAL ;
    PORT
      LAYER M4 ;
        RECT  17.088 33.264 17.28 33.288 ;
    END
  END i[299]
  PIN i[29]
    DIRECTION INPUT ;
    USE SIGNAL ;
    PORT
      LAYER M4 ;
        RECT  17.088 5.232 17.28 5.256 ;
    END
  END i[29]
  PIN i[2]
    DIRECTION INPUT ;
    USE SIGNAL ;
    PORT
      LAYER M4 ;
        RECT  17.088 2.448 17.28 2.472 ;
    END
  END i[2]
  PIN i[300]
    DIRECTION INPUT ;
    USE SIGNAL ;
    PORT
      LAYER M4 ;
        RECT  17.088 33.36 17.28 33.384 ;
    END
  END i[300]
  PIN i[301]
    DIRECTION INPUT ;
    USE SIGNAL ;
    PORT
      LAYER M4 ;
        RECT  17.088 33.456 17.28 33.48 ;
    END
  END i[301]
  PIN i[302]
    DIRECTION INPUT ;
    USE SIGNAL ;
    PORT
      LAYER M4 ;
        RECT  17.088 33.552 17.28 33.576 ;
    END
  END i[302]
  PIN i[303]
    DIRECTION INPUT ;
    USE SIGNAL ;
    PORT
      LAYER M4 ;
        RECT  17.088 33.648 17.28 33.672 ;
    END
  END i[303]
  PIN i[304]
    DIRECTION INPUT ;
    USE SIGNAL ;
    PORT
      LAYER M4 ;
        RECT  17.088 33.792 17.28 33.816 ;
    END
  END i[304]
  PIN i[305]
    DIRECTION INPUT ;
    USE SIGNAL ;
    PORT
      LAYER M4 ;
        RECT  17.088 33.888 17.28 33.912 ;
    END
  END i[305]
  PIN i[306]
    DIRECTION INPUT ;
    USE SIGNAL ;
    PORT
      LAYER M4 ;
        RECT  17.088 33.984 17.28 34.008 ;
    END
  END i[306]
  PIN i[307]
    DIRECTION INPUT ;
    USE SIGNAL ;
    PORT
      LAYER M4 ;
        RECT  17.088 34.08 17.28 34.104 ;
    END
  END i[307]
  PIN i[308]
    DIRECTION INPUT ;
    USE SIGNAL ;
    PORT
      LAYER M4 ;
        RECT  17.088 34.176 17.28 34.2 ;
    END
  END i[308]
  PIN i[309]
    DIRECTION INPUT ;
    USE SIGNAL ;
    PORT
      LAYER M4 ;
        RECT  17.088 34.272 17.28 34.296 ;
    END
  END i[309]
  PIN i[30]
    DIRECTION INPUT ;
    USE SIGNAL ;
    PORT
      LAYER M4 ;
        RECT  17.088 5.328 17.28 5.352 ;
    END
  END i[30]
  PIN i[310]
    DIRECTION INPUT ;
    USE SIGNAL ;
    PORT
      LAYER M4 ;
        RECT  17.088 34.416 17.28 34.44 ;
    END
  END i[310]
  PIN i[311]
    DIRECTION INPUT ;
    USE SIGNAL ;
    PORT
      LAYER M4 ;
        RECT  17.088 34.512 17.28 34.536 ;
    END
  END i[311]
  PIN i[312]
    DIRECTION INPUT ;
    USE SIGNAL ;
    PORT
      LAYER M4 ;
        RECT  17.088 34.608 17.28 34.632 ;
    END
  END i[312]
  PIN i[313]
    DIRECTION INPUT ;
    USE SIGNAL ;
    PORT
      LAYER M4 ;
        RECT  17.088 34.704 17.28 34.728 ;
    END
  END i[313]
  PIN i[314]
    DIRECTION INPUT ;
    USE SIGNAL ;
    PORT
      LAYER M4 ;
        RECT  17.088 34.8 17.28 34.824 ;
    END
  END i[314]
  PIN i[315]
    DIRECTION INPUT ;
    USE SIGNAL ;
    PORT
      LAYER M4 ;
        RECT  17.088 34.896 17.28 34.92 ;
    END
  END i[315]
  PIN i[316]
    DIRECTION INPUT ;
    USE SIGNAL ;
    PORT
      LAYER M4 ;
        RECT  17.088 34.992 17.28 35.016 ;
    END
  END i[316]
  PIN i[317]
    DIRECTION INPUT ;
    USE SIGNAL ;
    PORT
      LAYER M4 ;
        RECT  17.088 35.136 17.28 35.16 ;
    END
  END i[317]
  PIN i[318]
    DIRECTION INPUT ;
    USE SIGNAL ;
    PORT
      LAYER M4 ;
        RECT  17.088 35.232 17.28 35.256 ;
    END
  END i[318]
  PIN i[319]
    DIRECTION INPUT ;
    USE SIGNAL ;
    PORT
      LAYER M4 ;
        RECT  17.088 35.328 17.28 35.352 ;
    END
  END i[319]
  PIN i[31]
    DIRECTION INPUT ;
    USE SIGNAL ;
    PORT
      LAYER M4 ;
        RECT  17.088 5.424 17.28 5.448 ;
    END
  END i[31]
  PIN i[320]
    DIRECTION INPUT ;
    USE SIGNAL ;
    PORT
      LAYER M4 ;
        RECT  17.088 35.424 17.28 35.448 ;
    END
  END i[320]
  PIN i[321]
    DIRECTION INPUT ;
    USE SIGNAL ;
    PORT
      LAYER M4 ;
        RECT  17.088 35.52 17.28 35.544 ;
    END
  END i[321]
  PIN i[322]
    DIRECTION INPUT ;
    USE SIGNAL ;
    PORT
      LAYER M4 ;
        RECT  17.088 35.616 17.28 35.64 ;
    END
  END i[322]
  PIN i[323]
    DIRECTION INPUT ;
    USE SIGNAL ;
    PORT
      LAYER M4 ;
        RECT  17.088 35.76 17.28 35.784 ;
    END
  END i[323]
  PIN i[324]
    DIRECTION INPUT ;
    USE SIGNAL ;
    PORT
      LAYER M4 ;
        RECT  17.088 35.856 17.28 35.88 ;
    END
  END i[324]
  PIN i[325]
    DIRECTION INPUT ;
    USE SIGNAL ;
    PORT
      LAYER M4 ;
        RECT  17.088 35.952 17.28 35.976 ;
    END
  END i[325]
  PIN i[326]
    DIRECTION INPUT ;
    USE SIGNAL ;
    PORT
      LAYER M4 ;
        RECT  17.088 36.048 17.28 36.072 ;
    END
  END i[326]
  PIN i[327]
    DIRECTION INPUT ;
    USE SIGNAL ;
    PORT
      LAYER M4 ;
        RECT  17.088 36.144 17.28 36.168 ;
    END
  END i[327]
  PIN i[328]
    DIRECTION INPUT ;
    USE SIGNAL ;
    PORT
      LAYER M4 ;
        RECT  17.088 36.24 17.28 36.264 ;
    END
  END i[328]
  PIN i[329]
    DIRECTION INPUT ;
    USE SIGNAL ;
    PORT
      LAYER M4 ;
        RECT  17.088 36.384 17.28 36.408 ;
    END
  END i[329]
  PIN i[32]
    DIRECTION INPUT ;
    USE SIGNAL ;
    PORT
      LAYER M4 ;
        RECT  17.088 5.568 17.28 5.592 ;
    END
  END i[32]
  PIN i[330]
    DIRECTION INPUT ;
    USE SIGNAL ;
    PORT
      LAYER M4 ;
        RECT  17.088 36.48 17.28 36.504 ;
    END
  END i[330]
  PIN i[331]
    DIRECTION INPUT ;
    USE SIGNAL ;
    PORT
      LAYER M4 ;
        RECT  17.088 36.576 17.28 36.6 ;
    END
  END i[331]
  PIN i[332]
    DIRECTION INPUT ;
    USE SIGNAL ;
    PORT
      LAYER M4 ;
        RECT  17.088 36.672 17.28 36.696 ;
    END
  END i[332]
  PIN i[333]
    DIRECTION INPUT ;
    USE SIGNAL ;
    PORT
      LAYER M4 ;
        RECT  17.088 36.768 17.28 36.792 ;
    END
  END i[333]
  PIN i[334]
    DIRECTION INPUT ;
    USE SIGNAL ;
    PORT
      LAYER M4 ;
        RECT  17.088 36.864 17.28 36.888 ;
    END
  END i[334]
  PIN i[335]
    DIRECTION INPUT ;
    USE SIGNAL ;
    PORT
      LAYER M4 ;
        RECT  17.088 37.008 17.28 37.032 ;
    END
  END i[335]
  PIN i[336]
    DIRECTION INPUT ;
    USE SIGNAL ;
    PORT
      LAYER M4 ;
        RECT  17.088 37.104 17.28 37.128 ;
    END
  END i[336]
  PIN i[337]
    DIRECTION INPUT ;
    USE SIGNAL ;
    PORT
      LAYER M4 ;
        RECT  17.088 37.2 17.28 37.224 ;
    END
  END i[337]
  PIN i[338]
    DIRECTION INPUT ;
    USE SIGNAL ;
    PORT
      LAYER M4 ;
        RECT  17.088 37.296 17.28 37.32 ;
    END
  END i[338]
  PIN i[339]
    DIRECTION INPUT ;
    USE SIGNAL ;
    PORT
      LAYER M4 ;
        RECT  17.088 37.392 17.28 37.416 ;
    END
  END i[339]
  PIN i[33]
    DIRECTION INPUT ;
    USE SIGNAL ;
    PORT
      LAYER M4 ;
        RECT  17.088 5.664 17.28 5.688 ;
    END
  END i[33]
  PIN i[340]
    DIRECTION INPUT ;
    USE SIGNAL ;
    PORT
      LAYER M4 ;
        RECT  17.088 37.488 17.28 37.512 ;
    END
  END i[340]
  PIN i[341]
    DIRECTION INPUT ;
    USE SIGNAL ;
    PORT
      LAYER M4 ;
        RECT  17.088 37.632 17.28 37.656 ;
    END
  END i[341]
  PIN i[342]
    DIRECTION INPUT ;
    USE SIGNAL ;
    PORT
      LAYER M4 ;
        RECT  17.088 37.728 17.28 37.752 ;
    END
  END i[342]
  PIN i[343]
    DIRECTION INPUT ;
    USE SIGNAL ;
    PORT
      LAYER M4 ;
        RECT  17.088 37.824 17.28 37.848 ;
    END
  END i[343]
  PIN i[344]
    DIRECTION INPUT ;
    USE SIGNAL ;
    PORT
      LAYER M4 ;
        RECT  17.088 37.92 17.28 37.944 ;
    END
  END i[344]
  PIN i[345]
    DIRECTION INPUT ;
    USE SIGNAL ;
    PORT
      LAYER M4 ;
        RECT  17.088 38.016 17.28 38.04 ;
    END
  END i[345]
  PIN i[346]
    DIRECTION INPUT ;
    USE SIGNAL ;
    PORT
      LAYER M4 ;
        RECT  17.088 38.112 17.28 38.136 ;
    END
  END i[346]
  PIN i[347]
    DIRECTION INPUT ;
    USE SIGNAL ;
    PORT
      LAYER M4 ;
        RECT  17.088 38.256 17.28 38.28 ;
    END
  END i[347]
  PIN i[348]
    DIRECTION INPUT ;
    USE SIGNAL ;
    PORT
      LAYER M4 ;
        RECT  17.088 38.352 17.28 38.376 ;
    END
  END i[348]
  PIN i[349]
    DIRECTION INPUT ;
    USE SIGNAL ;
    PORT
      LAYER M4 ;
        RECT  17.088 38.448 17.28 38.472 ;
    END
  END i[349]
  PIN i[34]
    DIRECTION INPUT ;
    USE SIGNAL ;
    PORT
      LAYER M4 ;
        RECT  17.088 5.76 17.28 5.784 ;
    END
  END i[34]
  PIN i[350]
    DIRECTION INPUT ;
    USE SIGNAL ;
    PORT
      LAYER M4 ;
        RECT  17.088 38.544 17.28 38.568 ;
    END
  END i[350]
  PIN i[351]
    DIRECTION INPUT ;
    USE SIGNAL ;
    PORT
      LAYER M4 ;
        RECT  17.088 38.64 17.28 38.664 ;
    END
  END i[351]
  PIN i[352]
    DIRECTION INPUT ;
    USE SIGNAL ;
    PORT
      LAYER M4 ;
        RECT  17.088 38.736 17.28 38.76 ;
    END
  END i[352]
  PIN i[353]
    DIRECTION INPUT ;
    USE SIGNAL ;
    PORT
      LAYER M4 ;
        RECT  17.088 38.832 17.28 38.856 ;
    END
  END i[353]
  PIN i[354]
    DIRECTION INPUT ;
    USE SIGNAL ;
    PORT
      LAYER M4 ;
        RECT  17.088 38.976 17.28 39 ;
    END
  END i[354]
  PIN i[355]
    DIRECTION INPUT ;
    USE SIGNAL ;
    PORT
      LAYER M4 ;
        RECT  17.088 39.072 17.28 39.096 ;
    END
  END i[355]
  PIN i[356]
    DIRECTION INPUT ;
    USE SIGNAL ;
    PORT
      LAYER M4 ;
        RECT  17.088 39.168 17.28 39.192 ;
    END
  END i[356]
  PIN i[357]
    DIRECTION INPUT ;
    USE SIGNAL ;
    PORT
      LAYER M4 ;
        RECT  17.088 39.264 17.28 39.288 ;
    END
  END i[357]
  PIN i[358]
    DIRECTION INPUT ;
    USE SIGNAL ;
    PORT
      LAYER M4 ;
        RECT  17.088 39.36 17.28 39.384 ;
    END
  END i[358]
  PIN i[359]
    DIRECTION INPUT ;
    USE SIGNAL ;
    PORT
      LAYER M4 ;
        RECT  17.088 39.456 17.28 39.48 ;
    END
  END i[359]
  PIN i[35]
    DIRECTION INPUT ;
    USE SIGNAL ;
    PORT
      LAYER M4 ;
        RECT  17.088 5.856 17.28 5.88 ;
    END
  END i[35]
  PIN i[360]
    DIRECTION INPUT ;
    USE SIGNAL ;
    PORT
      LAYER M4 ;
        RECT  17.088 39.6 17.28 39.624 ;
    END
  END i[360]
  PIN i[361]
    DIRECTION INPUT ;
    USE SIGNAL ;
    PORT
      LAYER M4 ;
        RECT  17.088 39.696 17.28 39.72 ;
    END
  END i[361]
  PIN i[362]
    DIRECTION INPUT ;
    USE SIGNAL ;
    PORT
      LAYER M4 ;
        RECT  17.088 39.792 17.28 39.816 ;
    END
  END i[362]
  PIN i[363]
    DIRECTION INPUT ;
    USE SIGNAL ;
    PORT
      LAYER M4 ;
        RECT  17.088 39.888 17.28 39.912 ;
    END
  END i[363]
  PIN i[364]
    DIRECTION INPUT ;
    USE SIGNAL ;
    PORT
      LAYER M4 ;
        RECT  17.088 39.984 17.28 40.008 ;
    END
  END i[364]
  PIN i[365]
    DIRECTION INPUT ;
    USE SIGNAL ;
    PORT
      LAYER M4 ;
        RECT  17.088 40.08 17.28 40.104 ;
    END
  END i[365]
  PIN i[366]
    DIRECTION INPUT ;
    USE SIGNAL ;
    PORT
      LAYER M4 ;
        RECT  17.088 40.224 17.28 40.248 ;
    END
  END i[366]
  PIN i[367]
    DIRECTION INPUT ;
    USE SIGNAL ;
    PORT
      LAYER M4 ;
        RECT  17.088 40.32 17.28 40.344 ;
    END
  END i[367]
  PIN i[368]
    DIRECTION INPUT ;
    USE SIGNAL ;
    PORT
      LAYER M4 ;
        RECT  17.088 40.416 17.28 40.44 ;
    END
  END i[368]
  PIN i[369]
    DIRECTION INPUT ;
    USE SIGNAL ;
    PORT
      LAYER M4 ;
        RECT  17.088 40.512 17.28 40.536 ;
    END
  END i[369]
  PIN i[36]
    DIRECTION INPUT ;
    USE SIGNAL ;
    PORT
      LAYER M4 ;
        RECT  17.088 5.952 17.28 5.976 ;
    END
  END i[36]
  PIN i[370]
    DIRECTION INPUT ;
    USE SIGNAL ;
    PORT
      LAYER M4 ;
        RECT  17.088 40.608 17.28 40.632 ;
    END
  END i[370]
  PIN i[371]
    DIRECTION INPUT ;
    USE SIGNAL ;
    PORT
      LAYER M4 ;
        RECT  17.088 40.704 17.28 40.728 ;
    END
  END i[371]
  PIN i[372]
    DIRECTION INPUT ;
    USE SIGNAL ;
    PORT
      LAYER M4 ;
        RECT  17.088 40.848 17.28 40.872 ;
    END
  END i[372]
  PIN i[373]
    DIRECTION INPUT ;
    USE SIGNAL ;
    PORT
      LAYER M4 ;
        RECT  17.088 40.944 17.28 40.968 ;
    END
  END i[373]
  PIN i[374]
    DIRECTION INPUT ;
    USE SIGNAL ;
    PORT
      LAYER M4 ;
        RECT  17.088 41.04 17.28 41.064 ;
    END
  END i[374]
  PIN i[375]
    DIRECTION INPUT ;
    USE SIGNAL ;
    PORT
      LAYER M4 ;
        RECT  17.088 41.136 17.28 41.16 ;
    END
  END i[375]
  PIN i[376]
    DIRECTION INPUT ;
    USE SIGNAL ;
    PORT
      LAYER M4 ;
        RECT  17.088 41.232 17.28 41.256 ;
    END
  END i[376]
  PIN i[377]
    DIRECTION INPUT ;
    USE SIGNAL ;
    PORT
      LAYER M4 ;
        RECT  17.088 41.328 17.28 41.352 ;
    END
  END i[377]
  PIN i[378]
    DIRECTION INPUT ;
    USE SIGNAL ;
    PORT
      LAYER M4 ;
        RECT  17.088 41.472 17.28 41.496 ;
    END
  END i[378]
  PIN i[379]
    DIRECTION INPUT ;
    USE SIGNAL ;
    PORT
      LAYER M4 ;
        RECT  17.088 41.568 17.28 41.592 ;
    END
  END i[379]
  PIN i[37]
    DIRECTION INPUT ;
    USE SIGNAL ;
    PORT
      LAYER M4 ;
        RECT  17.088 6.048 17.28 6.072 ;
    END
  END i[37]
  PIN i[380]
    DIRECTION INPUT ;
    USE SIGNAL ;
    PORT
      LAYER M4 ;
        RECT  17.088 41.664 17.28 41.688 ;
    END
  END i[380]
  PIN i[381]
    DIRECTION INPUT ;
    USE SIGNAL ;
    PORT
      LAYER M4 ;
        RECT  17.088 41.76 17.28 41.784 ;
    END
  END i[381]
  PIN i[382]
    DIRECTION INPUT ;
    USE SIGNAL ;
    PORT
      LAYER M4 ;
        RECT  17.088 41.856 17.28 41.88 ;
    END
  END i[382]
  PIN i[383]
    DIRECTION INPUT ;
    USE SIGNAL ;
    PORT
      LAYER M4 ;
        RECT  17.088 41.952 17.28 41.976 ;
    END
  END i[383]
  PIN i[384]
    DIRECTION INPUT ;
    USE SIGNAL ;
    PORT
      LAYER M4 ;
        RECT  17.088 42.096 17.28 42.12 ;
    END
  END i[384]
  PIN i[385]
    DIRECTION INPUT ;
    USE SIGNAL ;
    PORT
      LAYER M4 ;
        RECT  17.088 42.192 17.28 42.216 ;
    END
  END i[385]
  PIN i[386]
    DIRECTION INPUT ;
    USE SIGNAL ;
    PORT
      LAYER M4 ;
        RECT  17.088 42.288 17.28 42.312 ;
    END
  END i[386]
  PIN i[387]
    DIRECTION INPUT ;
    USE SIGNAL ;
    PORT
      LAYER M4 ;
        RECT  17.088 42.384 17.28 42.408 ;
    END
  END i[387]
  PIN i[388]
    DIRECTION INPUT ;
    USE SIGNAL ;
    PORT
      LAYER M4 ;
        RECT  17.088 42.48 17.28 42.504 ;
    END
  END i[388]
  PIN i[389]
    DIRECTION INPUT ;
    USE SIGNAL ;
    PORT
      LAYER M4 ;
        RECT  17.088 42.576 17.28 42.6 ;
    END
  END i[389]
  PIN i[38]
    DIRECTION INPUT ;
    USE SIGNAL ;
    PORT
      LAYER M4 ;
        RECT  17.088 6.144 17.28 6.168 ;
    END
  END i[38]
  PIN i[390]
    DIRECTION INPUT ;
    USE SIGNAL ;
    PORT
      LAYER M4 ;
        RECT  17.088 42.672 17.28 42.696 ;
    END
  END i[390]
  PIN i[391]
    DIRECTION INPUT ;
    USE SIGNAL ;
    PORT
      LAYER M4 ;
        RECT  17.088 42.816 17.28 42.84 ;
    END
  END i[391]
  PIN i[392]
    DIRECTION INPUT ;
    USE SIGNAL ;
    PORT
      LAYER M4 ;
        RECT  17.088 42.912 17.28 42.936 ;
    END
  END i[392]
  PIN i[393]
    DIRECTION INPUT ;
    USE SIGNAL ;
    PORT
      LAYER M4 ;
        RECT  17.088 43.008 17.28 43.032 ;
    END
  END i[393]
  PIN i[394]
    DIRECTION INPUT ;
    USE SIGNAL ;
    PORT
      LAYER M4 ;
        RECT  17.088 43.104 17.28 43.128 ;
    END
  END i[394]
  PIN i[395]
    DIRECTION INPUT ;
    USE SIGNAL ;
    PORT
      LAYER M4 ;
        RECT  17.088 43.2 17.28 43.224 ;
    END
  END i[395]
  PIN i[396]
    DIRECTION INPUT ;
    USE SIGNAL ;
    PORT
      LAYER M4 ;
        RECT  17.088 43.296 17.28 43.32 ;
    END
  END i[396]
  PIN i[397]
    DIRECTION INPUT ;
    USE SIGNAL ;
    PORT
      LAYER M4 ;
        RECT  17.088 43.44 17.28 43.464 ;
    END
  END i[397]
  PIN i[398]
    DIRECTION INPUT ;
    USE SIGNAL ;
    PORT
      LAYER M4 ;
        RECT  17.088 43.536 17.28 43.56 ;
    END
  END i[398]
  PIN i[399]
    DIRECTION INPUT ;
    USE SIGNAL ;
    PORT
      LAYER M4 ;
        RECT  17.088 43.632 17.28 43.656 ;
    END
  END i[399]
  PIN i[39]
    DIRECTION INPUT ;
    USE SIGNAL ;
    PORT
      LAYER M4 ;
        RECT  17.088 6.288 17.28 6.312 ;
    END
  END i[39]
  PIN i[3]
    DIRECTION INPUT ;
    USE SIGNAL ;
    PORT
      LAYER M4 ;
        RECT  17.088 2.544 17.28 2.568 ;
    END
  END i[3]
  PIN i[400]
    DIRECTION INPUT ;
    USE SIGNAL ;
    PORT
      LAYER M4 ;
        RECT  17.088 43.728 17.28 43.752 ;
    END
  END i[400]
  PIN i[401]
    DIRECTION INPUT ;
    USE SIGNAL ;
    PORT
      LAYER M4 ;
        RECT  17.088 43.824 17.28 43.848 ;
    END
  END i[401]
  PIN i[402]
    DIRECTION INPUT ;
    USE SIGNAL ;
    PORT
      LAYER M4 ;
        RECT  17.088 43.92 17.28 43.944 ;
    END
  END i[402]
  PIN i[403]
    DIRECTION INPUT ;
    USE SIGNAL ;
    PORT
      LAYER M4 ;
        RECT  17.088 44.064 17.28 44.088 ;
    END
  END i[403]
  PIN i[404]
    DIRECTION INPUT ;
    USE SIGNAL ;
    PORT
      LAYER M4 ;
        RECT  17.088 44.16 17.28 44.184 ;
    END
  END i[404]
  PIN i[405]
    DIRECTION INPUT ;
    USE SIGNAL ;
    PORT
      LAYER M4 ;
        RECT  17.088 44.256 17.28 44.28 ;
    END
  END i[405]
  PIN i[406]
    DIRECTION INPUT ;
    USE SIGNAL ;
    PORT
      LAYER M4 ;
        RECT  17.088 44.352 17.28 44.376 ;
    END
  END i[406]
  PIN i[407]
    DIRECTION INPUT ;
    USE SIGNAL ;
    PORT
      LAYER M4 ;
        RECT  17.088 44.448 17.28 44.472 ;
    END
  END i[407]
  PIN i[408]
    DIRECTION INPUT ;
    USE SIGNAL ;
    PORT
      LAYER M4 ;
        RECT  17.088 44.544 17.28 44.568 ;
    END
  END i[408]
  PIN i[409]
    DIRECTION INPUT ;
    USE SIGNAL ;
    PORT
      LAYER M4 ;
        RECT  17.088 44.688 17.28 44.712 ;
    END
  END i[409]
  PIN i[40]
    DIRECTION INPUT ;
    USE SIGNAL ;
    PORT
      LAYER M4 ;
        RECT  17.088 6.384 17.28 6.408 ;
    END
  END i[40]
  PIN i[410]
    DIRECTION INPUT ;
    USE SIGNAL ;
    PORT
      LAYER M4 ;
        RECT  17.088 44.784 17.28 44.808 ;
    END
  END i[410]
  PIN i[411]
    DIRECTION INPUT ;
    USE SIGNAL ;
    PORT
      LAYER M4 ;
        RECT  17.088 44.88 17.28 44.904 ;
    END
  END i[411]
  PIN i[412]
    DIRECTION INPUT ;
    USE SIGNAL ;
    PORT
      LAYER M4 ;
        RECT  17.088 44.976 17.28 45 ;
    END
  END i[412]
  PIN i[413]
    DIRECTION INPUT ;
    USE SIGNAL ;
    PORT
      LAYER M4 ;
        RECT  17.088 45.072 17.28 45.096 ;
    END
  END i[413]
  PIN i[414]
    DIRECTION INPUT ;
    USE SIGNAL ;
    PORT
      LAYER M4 ;
        RECT  17.088 45.168 17.28 45.192 ;
    END
  END i[414]
  PIN i[415]
    DIRECTION INPUT ;
    USE SIGNAL ;
    PORT
      LAYER M4 ;
        RECT  17.088 45.312 17.28 45.336 ;
    END
  END i[415]
  PIN i[416]
    DIRECTION INPUT ;
    USE SIGNAL ;
    PORT
      LAYER M4 ;
        RECT  17.088 45.408 17.28 45.432 ;
    END
  END i[416]
  PIN i[417]
    DIRECTION INPUT ;
    USE SIGNAL ;
    PORT
      LAYER M4 ;
        RECT  17.088 45.504 17.28 45.528 ;
    END
  END i[417]
  PIN i[418]
    DIRECTION INPUT ;
    USE SIGNAL ;
    PORT
      LAYER M4 ;
        RECT  17.088 45.6 17.28 45.624 ;
    END
  END i[418]
  PIN i[419]
    DIRECTION INPUT ;
    USE SIGNAL ;
    PORT
      LAYER M4 ;
        RECT  17.088 45.696 17.28 45.72 ;
    END
  END i[419]
  PIN i[41]
    DIRECTION INPUT ;
    USE SIGNAL ;
    PORT
      LAYER M4 ;
        RECT  17.088 6.48 17.28 6.504 ;
    END
  END i[41]
  PIN i[420]
    DIRECTION INPUT ;
    USE SIGNAL ;
    PORT
      LAYER M4 ;
        RECT  17.088 45.792 17.28 45.816 ;
    END
  END i[420]
  PIN i[421]
    DIRECTION INPUT ;
    USE SIGNAL ;
    PORT
      LAYER M4 ;
        RECT  17.088 45.936 17.28 45.96 ;
    END
  END i[421]
  PIN i[422]
    DIRECTION INPUT ;
    USE SIGNAL ;
    PORT
      LAYER M4 ;
        RECT  17.088 46.032 17.28 46.056 ;
    END
  END i[422]
  PIN i[423]
    DIRECTION INPUT ;
    USE SIGNAL ;
    PORT
      LAYER M4 ;
        RECT  17.088 46.128 17.28 46.152 ;
    END
  END i[423]
  PIN i[424]
    DIRECTION INPUT ;
    USE SIGNAL ;
    PORT
      LAYER M4 ;
        RECT  17.088 46.224 17.28 46.248 ;
    END
  END i[424]
  PIN i[425]
    DIRECTION INPUT ;
    USE SIGNAL ;
    PORT
      LAYER M4 ;
        RECT  17.088 46.32 17.28 46.344 ;
    END
  END i[425]
  PIN i[426]
    DIRECTION INPUT ;
    USE SIGNAL ;
    PORT
      LAYER M4 ;
        RECT  17.088 46.416 17.28 46.44 ;
    END
  END i[426]
  PIN i[427]
    DIRECTION INPUT ;
    USE SIGNAL ;
    PORT
      LAYER M4 ;
        RECT  17.088 46.512 17.28 46.536 ;
    END
  END i[427]
  PIN i[428]
    DIRECTION INPUT ;
    USE SIGNAL ;
    PORT
      LAYER M4 ;
        RECT  17.088 46.656 17.28 46.68 ;
    END
  END i[428]
  PIN i[429]
    DIRECTION INPUT ;
    USE SIGNAL ;
    PORT
      LAYER M4 ;
        RECT  17.088 46.752 17.28 46.776 ;
    END
  END i[429]
  PIN i[42]
    DIRECTION INPUT ;
    USE SIGNAL ;
    PORT
      LAYER M4 ;
        RECT  17.088 6.576 17.28 6.6 ;
    END
  END i[42]
  PIN i[430]
    DIRECTION INPUT ;
    USE SIGNAL ;
    PORT
      LAYER M4 ;
        RECT  17.088 46.848 17.28 46.872 ;
    END
  END i[430]
  PIN i[431]
    DIRECTION INPUT ;
    USE SIGNAL ;
    PORT
      LAYER M4 ;
        RECT  17.088 46.944 17.28 46.968 ;
    END
  END i[431]
  PIN i[432]
    DIRECTION INPUT ;
    USE SIGNAL ;
    PORT
      LAYER M4 ;
        RECT  17.088 47.04 17.28 47.064 ;
    END
  END i[432]
  PIN i[433]
    DIRECTION INPUT ;
    USE SIGNAL ;
    PORT
      LAYER M4 ;
        RECT  17.088 47.136 17.28 47.16 ;
    END
  END i[433]
  PIN i[434]
    DIRECTION INPUT ;
    USE SIGNAL ;
    PORT
      LAYER M4 ;
        RECT  17.088 47.28 17.28 47.304 ;
    END
  END i[434]
  PIN i[435]
    DIRECTION INPUT ;
    USE SIGNAL ;
    PORT
      LAYER M4 ;
        RECT  17.088 47.376 17.28 47.4 ;
    END
  END i[435]
  PIN i[436]
    DIRECTION INPUT ;
    USE SIGNAL ;
    PORT
      LAYER M4 ;
        RECT  17.088 47.472 17.28 47.496 ;
    END
  END i[436]
  PIN i[437]
    DIRECTION INPUT ;
    USE SIGNAL ;
    PORT
      LAYER M4 ;
        RECT  17.088 47.568 17.28 47.592 ;
    END
  END i[437]
  PIN i[438]
    DIRECTION INPUT ;
    USE SIGNAL ;
    PORT
      LAYER M4 ;
        RECT  17.088 47.664 17.28 47.688 ;
    END
  END i[438]
  PIN i[439]
    DIRECTION INPUT ;
    USE SIGNAL ;
    PORT
      LAYER M4 ;
        RECT  17.088 47.76 17.28 47.784 ;
    END
  END i[439]
  PIN i[43]
    DIRECTION INPUT ;
    USE SIGNAL ;
    PORT
      LAYER M4 ;
        RECT  17.088 6.672 17.28 6.696 ;
    END
  END i[43]
  PIN i[440]
    DIRECTION INPUT ;
    USE SIGNAL ;
    PORT
      LAYER M4 ;
        RECT  17.088 47.904 17.28 47.928 ;
    END
  END i[440]
  PIN i[441]
    DIRECTION INPUT ;
    USE SIGNAL ;
    PORT
      LAYER M4 ;
        RECT  17.088 48 17.28 48.024 ;
    END
  END i[441]
  PIN i[442]
    DIRECTION INPUT ;
    USE SIGNAL ;
    PORT
      LAYER M4 ;
        RECT  17.088 48.096 17.28 48.12 ;
    END
  END i[442]
  PIN i[443]
    DIRECTION INPUT ;
    USE SIGNAL ;
    PORT
      LAYER M4 ;
        RECT  17.088 48.192 17.28 48.216 ;
    END
  END i[443]
  PIN i[444]
    DIRECTION INPUT ;
    USE SIGNAL ;
    PORT
      LAYER M4 ;
        RECT  17.088 48.288 17.28 48.312 ;
    END
  END i[444]
  PIN i[445]
    DIRECTION INPUT ;
    USE SIGNAL ;
    PORT
      LAYER M4 ;
        RECT  17.088 48.384 17.28 48.408 ;
    END
  END i[445]
  PIN i[446]
    DIRECTION INPUT ;
    USE SIGNAL ;
    PORT
      LAYER M4 ;
        RECT  17.088 48.528 17.28 48.552 ;
    END
  END i[446]
  PIN i[447]
    DIRECTION INPUT ;
    USE SIGNAL ;
    PORT
      LAYER M4 ;
        RECT  17.088 48.624 17.28 48.648 ;
    END
  END i[447]
  PIN i[448]
    DIRECTION INPUT ;
    USE SIGNAL ;
    PORT
      LAYER M4 ;
        RECT  17.088 48.72 17.28 48.744 ;
    END
  END i[448]
  PIN i[449]
    DIRECTION INPUT ;
    USE SIGNAL ;
    PORT
      LAYER M4 ;
        RECT  17.088 48.816 17.28 48.84 ;
    END
  END i[449]
  PIN i[44]
    DIRECTION INPUT ;
    USE SIGNAL ;
    PORT
      LAYER M4 ;
        RECT  17.088 6.768 17.28 6.792 ;
    END
  END i[44]
  PIN i[450]
    DIRECTION INPUT ;
    USE SIGNAL ;
    PORT
      LAYER M4 ;
        RECT  17.088 48.912 17.28 48.936 ;
    END
  END i[450]
  PIN i[451]
    DIRECTION INPUT ;
    USE SIGNAL ;
    PORT
      LAYER M4 ;
        RECT  17.088 49.008 17.28 49.032 ;
    END
  END i[451]
  PIN i[452]
    DIRECTION INPUT ;
    USE SIGNAL ;
    PORT
      LAYER M4 ;
        RECT  17.088 49.152 17.28 49.176 ;
    END
  END i[452]
  PIN i[453]
    DIRECTION INPUT ;
    USE SIGNAL ;
    PORT
      LAYER M4 ;
        RECT  17.088 49.248 17.28 49.272 ;
    END
  END i[453]
  PIN i[454]
    DIRECTION INPUT ;
    USE SIGNAL ;
    PORT
      LAYER M4 ;
        RECT  17.088 49.344 17.28 49.368 ;
    END
  END i[454]
  PIN i[455]
    DIRECTION INPUT ;
    USE SIGNAL ;
    PORT
      LAYER M4 ;
        RECT  17.088 49.44 17.28 49.464 ;
    END
  END i[455]
  PIN i[456]
    DIRECTION INPUT ;
    USE SIGNAL ;
    PORT
      LAYER M4 ;
        RECT  17.088 49.536 17.28 49.56 ;
    END
  END i[456]
  PIN i[457]
    DIRECTION INPUT ;
    USE SIGNAL ;
    PORT
      LAYER M4 ;
        RECT  17.088 49.632 17.28 49.656 ;
    END
  END i[457]
  PIN i[458]
    DIRECTION INPUT ;
    USE SIGNAL ;
    PORT
      LAYER M4 ;
        RECT  17.088 49.728 17.28 49.752 ;
    END
  END i[458]
  PIN i[459]
    DIRECTION INPUT ;
    USE SIGNAL ;
    PORT
      LAYER M4 ;
        RECT  17.088 49.872 17.28 49.896 ;
    END
  END i[459]
  PIN i[45]
    DIRECTION INPUT ;
    USE SIGNAL ;
    PORT
      LAYER M4 ;
        RECT  17.088 6.912 17.28 6.936 ;
    END
  END i[45]
  PIN i[460]
    DIRECTION INPUT ;
    USE SIGNAL ;
    PORT
      LAYER M4 ;
        RECT  17.088 49.968 17.28 49.992 ;
    END
  END i[460]
  PIN i[461]
    DIRECTION INPUT ;
    USE SIGNAL ;
    PORT
      LAYER M4 ;
        RECT  17.088 50.064 17.28 50.088 ;
    END
  END i[461]
  PIN i[462]
    DIRECTION INPUT ;
    USE SIGNAL ;
    PORT
      LAYER M4 ;
        RECT  17.088 50.16 17.28 50.184 ;
    END
  END i[462]
  PIN i[463]
    DIRECTION INPUT ;
    USE SIGNAL ;
    PORT
      LAYER M4 ;
        RECT  17.088 50.256 17.28 50.28 ;
    END
  END i[463]
  PIN i[464]
    DIRECTION INPUT ;
    USE SIGNAL ;
    PORT
      LAYER M4 ;
        RECT  17.088 50.352 17.28 50.376 ;
    END
  END i[464]
  PIN i[465]
    DIRECTION INPUT ;
    USE SIGNAL ;
    PORT
      LAYER M4 ;
        RECT  17.088 50.496 17.28 50.52 ;
    END
  END i[465]
  PIN i[466]
    DIRECTION INPUT ;
    USE SIGNAL ;
    PORT
      LAYER M4 ;
        RECT  17.088 50.592 17.28 50.616 ;
    END
  END i[466]
  PIN i[467]
    DIRECTION INPUT ;
    USE SIGNAL ;
    PORT
      LAYER M4 ;
        RECT  17.088 50.688 17.28 50.712 ;
    END
  END i[467]
  PIN i[468]
    DIRECTION INPUT ;
    USE SIGNAL ;
    PORT
      LAYER M4 ;
        RECT  17.088 50.784 17.28 50.808 ;
    END
  END i[468]
  PIN i[469]
    DIRECTION INPUT ;
    USE SIGNAL ;
    PORT
      LAYER M4 ;
        RECT  17.088 50.88 17.28 50.904 ;
    END
  END i[469]
  PIN i[46]
    DIRECTION INPUT ;
    USE SIGNAL ;
    PORT
      LAYER M4 ;
        RECT  17.088 7.008 17.28 7.032 ;
    END
  END i[46]
  PIN i[470]
    DIRECTION INPUT ;
    USE SIGNAL ;
    PORT
      LAYER M4 ;
        RECT  17.088 50.976 17.28 51 ;
    END
  END i[470]
  PIN i[471]
    DIRECTION INPUT ;
    USE SIGNAL ;
    PORT
      LAYER M4 ;
        RECT  17.088 51.12 17.28 51.144 ;
    END
  END i[471]
  PIN i[472]
    DIRECTION INPUT ;
    USE SIGNAL ;
    PORT
      LAYER M4 ;
        RECT  17.088 51.216 17.28 51.24 ;
    END
  END i[472]
  PIN i[473]
    DIRECTION INPUT ;
    USE SIGNAL ;
    PORT
      LAYER M4 ;
        RECT  17.088 51.312 17.28 51.336 ;
    END
  END i[473]
  PIN i[474]
    DIRECTION INPUT ;
    USE SIGNAL ;
    PORT
      LAYER M4 ;
        RECT  17.088 51.408 17.28 51.432 ;
    END
  END i[474]
  PIN i[475]
    DIRECTION INPUT ;
    USE SIGNAL ;
    PORT
      LAYER M4 ;
        RECT  17.088 51.504 17.28 51.528 ;
    END
  END i[475]
  PIN i[476]
    DIRECTION INPUT ;
    USE SIGNAL ;
    PORT
      LAYER M4 ;
        RECT  17.088 51.6 17.28 51.624 ;
    END
  END i[476]
  PIN i[477]
    DIRECTION INPUT ;
    USE SIGNAL ;
    PORT
      LAYER M4 ;
        RECT  17.088 51.744 17.28 51.768 ;
    END
  END i[477]
  PIN i[478]
    DIRECTION INPUT ;
    USE SIGNAL ;
    PORT
      LAYER M4 ;
        RECT  17.088 51.84 17.28 51.864 ;
    END
  END i[478]
  PIN i[479]
    DIRECTION INPUT ;
    USE SIGNAL ;
    PORT
      LAYER M4 ;
        RECT  17.088 51.936 17.28 51.96 ;
    END
  END i[479]
  PIN i[47]
    DIRECTION INPUT ;
    USE SIGNAL ;
    PORT
      LAYER M4 ;
        RECT  17.088 7.104 17.28 7.128 ;
    END
  END i[47]
  PIN i[480]
    DIRECTION INPUT ;
    USE SIGNAL ;
    PORT
      LAYER M4 ;
        RECT  17.088 52.032 17.28 52.056 ;
    END
  END i[480]
  PIN i[481]
    DIRECTION INPUT ;
    USE SIGNAL ;
    PORT
      LAYER M4 ;
        RECT  17.088 52.128 17.28 52.152 ;
    END
  END i[481]
  PIN i[482]
    DIRECTION INPUT ;
    USE SIGNAL ;
    PORT
      LAYER M4 ;
        RECT  17.088 52.224 17.28 52.248 ;
    END
  END i[482]
  PIN i[483]
    DIRECTION INPUT ;
    USE SIGNAL ;
    PORT
      LAYER M4 ;
        RECT  17.088 52.368 17.28 52.392 ;
    END
  END i[483]
  PIN i[484]
    DIRECTION INPUT ;
    USE SIGNAL ;
    PORT
      LAYER M4 ;
        RECT  17.088 52.464 17.28 52.488 ;
    END
  END i[484]
  PIN i[485]
    DIRECTION INPUT ;
    USE SIGNAL ;
    PORT
      LAYER M4 ;
        RECT  17.088 52.56 17.28 52.584 ;
    END
  END i[485]
  PIN i[486]
    DIRECTION INPUT ;
    USE SIGNAL ;
    PORT
      LAYER M4 ;
        RECT  17.088 52.656 17.28 52.68 ;
    END
  END i[486]
  PIN i[487]
    DIRECTION INPUT ;
    USE SIGNAL ;
    PORT
      LAYER M4 ;
        RECT  17.088 52.752 17.28 52.776 ;
    END
  END i[487]
  PIN i[488]
    DIRECTION INPUT ;
    USE SIGNAL ;
    PORT
      LAYER M4 ;
        RECT  17.088 52.848 17.28 52.872 ;
    END
  END i[488]
  PIN i[489]
    DIRECTION INPUT ;
    USE SIGNAL ;
    PORT
      LAYER M4 ;
        RECT  17.088 52.992 17.28 53.016 ;
    END
  END i[489]
  PIN i[48]
    DIRECTION INPUT ;
    USE SIGNAL ;
    PORT
      LAYER M4 ;
        RECT  17.088 7.2 17.28 7.224 ;
    END
  END i[48]
  PIN i[490]
    DIRECTION INPUT ;
    USE SIGNAL ;
    PORT
      LAYER M4 ;
        RECT  17.088 53.088 17.28 53.112 ;
    END
  END i[490]
  PIN i[491]
    DIRECTION INPUT ;
    USE SIGNAL ;
    PORT
      LAYER M4 ;
        RECT  17.088 53.184 17.28 53.208 ;
    END
  END i[491]
  PIN i[492]
    DIRECTION INPUT ;
    USE SIGNAL ;
    PORT
      LAYER M4 ;
        RECT  17.088 53.28 17.28 53.304 ;
    END
  END i[492]
  PIN i[493]
    DIRECTION INPUT ;
    USE SIGNAL ;
    PORT
      LAYER M4 ;
        RECT  17.088 53.376 17.28 53.4 ;
    END
  END i[493]
  PIN i[494]
    DIRECTION INPUT ;
    USE SIGNAL ;
    PORT
      LAYER M4 ;
        RECT  17.088 53.472 17.28 53.496 ;
    END
  END i[494]
  PIN i[495]
    DIRECTION INPUT ;
    USE SIGNAL ;
    PORT
      LAYER M4 ;
        RECT  17.088 53.568 17.28 53.592 ;
    END
  END i[495]
  PIN i[496]
    DIRECTION INPUT ;
    USE SIGNAL ;
    PORT
      LAYER M4 ;
        RECT  17.088 53.712 17.28 53.736 ;
    END
  END i[496]
  PIN i[497]
    DIRECTION INPUT ;
    USE SIGNAL ;
    PORT
      LAYER M4 ;
        RECT  17.088 53.808 17.28 53.832 ;
    END
  END i[497]
  PIN i[498]
    DIRECTION INPUT ;
    USE SIGNAL ;
    PORT
      LAYER M4 ;
        RECT  17.088 53.904 17.28 53.928 ;
    END
  END i[498]
  PIN i[499]
    DIRECTION INPUT ;
    USE SIGNAL ;
    PORT
      LAYER M4 ;
        RECT  17.088 54 17.28 54.024 ;
    END
  END i[499]
  PIN i[49]
    DIRECTION INPUT ;
    USE SIGNAL ;
    PORT
      LAYER M4 ;
        RECT  17.088 7.296 17.28 7.32 ;
    END
  END i[49]
  PIN i[4]
    DIRECTION INPUT ;
    USE SIGNAL ;
    PORT
      LAYER M4 ;
        RECT  17.088 2.64 17.28 2.664 ;
    END
  END i[4]
  PIN i[500]
    DIRECTION INPUT ;
    USE SIGNAL ;
    PORT
      LAYER M4 ;
        RECT  17.088 54.096 17.28 54.12 ;
    END
  END i[500]
  PIN i[501]
    DIRECTION INPUT ;
    USE SIGNAL ;
    PORT
      LAYER M4 ;
        RECT  17.088 54.192 17.28 54.216 ;
    END
  END i[501]
  PIN i[502]
    DIRECTION INPUT ;
    USE SIGNAL ;
    PORT
      LAYER M4 ;
        RECT  17.088 54.336 17.28 54.36 ;
    END
  END i[502]
  PIN i[503]
    DIRECTION INPUT ;
    USE SIGNAL ;
    PORT
      LAYER M4 ;
        RECT  17.088 54.432 17.28 54.456 ;
    END
  END i[503]
  PIN i[504]
    DIRECTION INPUT ;
    USE SIGNAL ;
    PORT
      LAYER M4 ;
        RECT  17.088 54.528 17.28 54.552 ;
    END
  END i[504]
  PIN i[505]
    DIRECTION INPUT ;
    USE SIGNAL ;
    PORT
      LAYER M4 ;
        RECT  17.088 54.624 17.28 54.648 ;
    END
  END i[505]
  PIN i[506]
    DIRECTION INPUT ;
    USE SIGNAL ;
    PORT
      LAYER M4 ;
        RECT  17.088 54.72 17.28 54.744 ;
    END
  END i[506]
  PIN i[507]
    DIRECTION INPUT ;
    USE SIGNAL ;
    PORT
      LAYER M4 ;
        RECT  17.088 54.816 17.28 54.84 ;
    END
  END i[507]
  PIN i[508]
    DIRECTION INPUT ;
    USE SIGNAL ;
    PORT
      LAYER M4 ;
        RECT  17.088 54.96 17.28 54.984 ;
    END
  END i[508]
  PIN i[509]
    DIRECTION INPUT ;
    USE SIGNAL ;
    PORT
      LAYER M4 ;
        RECT  17.088 55.056 17.28 55.08 ;
    END
  END i[509]
  PIN i[50]
    DIRECTION INPUT ;
    USE SIGNAL ;
    PORT
      LAYER M4 ;
        RECT  17.088 7.392 17.28 7.416 ;
    END
  END i[50]
  PIN i[510]
    DIRECTION INPUT ;
    USE SIGNAL ;
    PORT
      LAYER M4 ;
        RECT  17.088 55.152 17.28 55.176 ;
    END
  END i[510]
  PIN i[511]
    DIRECTION INPUT ;
    USE SIGNAL ;
    PORT
      LAYER M4 ;
        RECT  17.088 55.248 17.28 55.272 ;
    END
  END i[511]
  PIN i[512]
    DIRECTION INPUT ;
    USE SIGNAL ;
    PORT
      LAYER M4 ;
        RECT  17.088 55.344 17.28 55.368 ;
    END
  END i[512]
  PIN i[513]
    DIRECTION INPUT ;
    USE SIGNAL ;
    PORT
      LAYER M4 ;
        RECT  17.088 55.44 17.28 55.464 ;
    END
  END i[513]
  PIN i[514]
    DIRECTION INPUT ;
    USE SIGNAL ;
    PORT
      LAYER M4 ;
        RECT  17.088 55.584 17.28 55.608 ;
    END
  END i[514]
  PIN i[515]
    DIRECTION INPUT ;
    USE SIGNAL ;
    PORT
      LAYER M4 ;
        RECT  17.088 55.68 17.28 55.704 ;
    END
  END i[515]
  PIN i[516]
    DIRECTION INPUT ;
    USE SIGNAL ;
    PORT
      LAYER M4 ;
        RECT  17.088 55.776 17.28 55.8 ;
    END
  END i[516]
  PIN i[517]
    DIRECTION INPUT ;
    USE SIGNAL ;
    PORT
      LAYER M4 ;
        RECT  17.088 55.872 17.28 55.896 ;
    END
  END i[517]
  PIN i[518]
    DIRECTION INPUT ;
    USE SIGNAL ;
    PORT
      LAYER M4 ;
        RECT  17.088 55.968 17.28 55.992 ;
    END
  END i[518]
  PIN i[519]
    DIRECTION INPUT ;
    USE SIGNAL ;
    PORT
      LAYER M4 ;
        RECT  17.088 56.064 17.28 56.088 ;
    END
  END i[519]
  PIN i[51]
    DIRECTION INPUT ;
    USE SIGNAL ;
    PORT
      LAYER M4 ;
        RECT  17.088 7.536 17.28 7.56 ;
    END
  END i[51]
  PIN i[520]
    DIRECTION INPUT ;
    USE SIGNAL ;
    PORT
      LAYER M4 ;
        RECT  17.088 56.208 17.28 56.232 ;
    END
  END i[520]
  PIN i[521]
    DIRECTION INPUT ;
    USE SIGNAL ;
    PORT
      LAYER M4 ;
        RECT  17.088 56.304 17.28 56.328 ;
    END
  END i[521]
  PIN i[522]
    DIRECTION INPUT ;
    USE SIGNAL ;
    PORT
      LAYER M4 ;
        RECT  17.088 56.4 17.28 56.424 ;
    END
  END i[522]
  PIN i[523]
    DIRECTION INPUT ;
    USE SIGNAL ;
    PORT
      LAYER M4 ;
        RECT  17.088 56.496 17.28 56.52 ;
    END
  END i[523]
  PIN i[524]
    DIRECTION INPUT ;
    USE SIGNAL ;
    PORT
      LAYER M4 ;
        RECT  17.088 56.592 17.28 56.616 ;
    END
  END i[524]
  PIN i[525]
    DIRECTION INPUT ;
    USE SIGNAL ;
    PORT
      LAYER M4 ;
        RECT  17.088 56.688 17.28 56.712 ;
    END
  END i[525]
  PIN i[526]
    DIRECTION INPUT ;
    USE SIGNAL ;
    PORT
      LAYER M4 ;
        RECT  17.088 56.832 17.28 56.856 ;
    END
  END i[526]
  PIN i[527]
    DIRECTION INPUT ;
    USE SIGNAL ;
    PORT
      LAYER M4 ;
        RECT  17.088 56.928 17.28 56.952 ;
    END
  END i[527]
  PIN i[528]
    DIRECTION INPUT ;
    USE SIGNAL ;
    PORT
      LAYER M4 ;
        RECT  17.088 57.024 17.28 57.048 ;
    END
  END i[528]
  PIN i[529]
    DIRECTION INPUT ;
    USE SIGNAL ;
    PORT
      LAYER M4 ;
        RECT  17.088 57.12 17.28 57.144 ;
    END
  END i[529]
  PIN i[52]
    DIRECTION INPUT ;
    USE SIGNAL ;
    PORT
      LAYER M4 ;
        RECT  17.088 7.632 17.28 7.656 ;
    END
  END i[52]
  PIN i[530]
    DIRECTION INPUT ;
    USE SIGNAL ;
    PORT
      LAYER M4 ;
        RECT  17.088 57.216 17.28 57.24 ;
    END
  END i[530]
  PIN i[531]
    DIRECTION INPUT ;
    USE SIGNAL ;
    PORT
      LAYER M4 ;
        RECT  17.088 57.312 17.28 57.336 ;
    END
  END i[531]
  PIN i[532]
    DIRECTION INPUT ;
    USE SIGNAL ;
    PORT
      LAYER M4 ;
        RECT  17.088 57.408 17.28 57.432 ;
    END
  END i[532]
  PIN i[533]
    DIRECTION INPUT ;
    USE SIGNAL ;
    PORT
      LAYER M4 ;
        RECT  17.088 57.552 17.28 57.576 ;
    END
  END i[533]
  PIN i[534]
    DIRECTION INPUT ;
    USE SIGNAL ;
    PORT
      LAYER M4 ;
        RECT  17.088 57.648 17.28 57.672 ;
    END
  END i[534]
  PIN i[535]
    DIRECTION INPUT ;
    USE SIGNAL ;
    PORT
      LAYER M4 ;
        RECT  17.088 57.744 17.28 57.768 ;
    END
  END i[535]
  PIN i[536]
    DIRECTION INPUT ;
    USE SIGNAL ;
    PORT
      LAYER M4 ;
        RECT  17.088 57.84 17.28 57.864 ;
    END
  END i[536]
  PIN i[537]
    DIRECTION INPUT ;
    USE SIGNAL ;
    PORT
      LAYER M4 ;
        RECT  17.088 57.936 17.28 57.96 ;
    END
  END i[537]
  PIN i[538]
    DIRECTION INPUT ;
    USE SIGNAL ;
    PORT
      LAYER M4 ;
        RECT  17.088 58.032 17.28 58.056 ;
    END
  END i[538]
  PIN i[539]
    DIRECTION INPUT ;
    USE SIGNAL ;
    PORT
      LAYER M4 ;
        RECT  17.088 58.176 17.28 58.2 ;
    END
  END i[539]
  PIN i[53]
    DIRECTION INPUT ;
    USE SIGNAL ;
    PORT
      LAYER M4 ;
        RECT  17.088 7.728 17.28 7.752 ;
    END
  END i[53]
  PIN i[540]
    DIRECTION INPUT ;
    USE SIGNAL ;
    PORT
      LAYER M4 ;
        RECT  17.088 58.272 17.28 58.296 ;
    END
  END i[540]
  PIN i[541]
    DIRECTION INPUT ;
    USE SIGNAL ;
    PORT
      LAYER M4 ;
        RECT  17.088 58.368 17.28 58.392 ;
    END
  END i[541]
  PIN i[542]
    DIRECTION INPUT ;
    USE SIGNAL ;
    PORT
      LAYER M4 ;
        RECT  17.088 58.464 17.28 58.488 ;
    END
  END i[542]
  PIN i[543]
    DIRECTION INPUT ;
    USE SIGNAL ;
    PORT
      LAYER M4 ;
        RECT  17.088 58.56 17.28 58.584 ;
    END
  END i[543]
  PIN i[544]
    DIRECTION INPUT ;
    USE SIGNAL ;
    PORT
      LAYER M4 ;
        RECT  17.088 58.656 17.28 58.68 ;
    END
  END i[544]
  PIN i[545]
    DIRECTION INPUT ;
    USE SIGNAL ;
    PORT
      LAYER M4 ;
        RECT  17.088 58.8 17.28 58.824 ;
    END
  END i[545]
  PIN i[546]
    DIRECTION INPUT ;
    USE SIGNAL ;
    PORT
      LAYER M4 ;
        RECT  17.088 58.896 17.28 58.92 ;
    END
  END i[546]
  PIN i[547]
    DIRECTION INPUT ;
    USE SIGNAL ;
    PORT
      LAYER M4 ;
        RECT  17.088 58.992 17.28 59.016 ;
    END
  END i[547]
  PIN i[548]
    DIRECTION INPUT ;
    USE SIGNAL ;
    PORT
      LAYER M4 ;
        RECT  17.088 59.088 17.28 59.112 ;
    END
  END i[548]
  PIN i[549]
    DIRECTION INPUT ;
    USE SIGNAL ;
    PORT
      LAYER M4 ;
        RECT  17.088 59.184 17.28 59.208 ;
    END
  END i[549]
  PIN i[54]
    DIRECTION INPUT ;
    USE SIGNAL ;
    PORT
      LAYER M4 ;
        RECT  17.088 7.824 17.28 7.848 ;
    END
  END i[54]
  PIN i[550]
    DIRECTION INPUT ;
    USE SIGNAL ;
    PORT
      LAYER M4 ;
        RECT  17.088 59.28 17.28 59.304 ;
    END
  END i[550]
  PIN i[551]
    DIRECTION INPUT ;
    USE SIGNAL ;
    PORT
      LAYER M4 ;
        RECT  17.088 59.424 17.28 59.448 ;
    END
  END i[551]
  PIN i[552]
    DIRECTION INPUT ;
    USE SIGNAL ;
    PORT
      LAYER M4 ;
        RECT  17.088 59.52 17.28 59.544 ;
    END
  END i[552]
  PIN i[553]
    DIRECTION INPUT ;
    USE SIGNAL ;
    PORT
      LAYER M4 ;
        RECT  17.088 59.616 17.28 59.64 ;
    END
  END i[553]
  PIN i[554]
    DIRECTION INPUT ;
    USE SIGNAL ;
    PORT
      LAYER M4 ;
        RECT  17.088 59.712 17.28 59.736 ;
    END
  END i[554]
  PIN i[555]
    DIRECTION INPUT ;
    USE SIGNAL ;
    PORT
      LAYER M4 ;
        RECT  17.088 59.808 17.28 59.832 ;
    END
  END i[555]
  PIN i[556]
    DIRECTION INPUT ;
    USE SIGNAL ;
    PORT
      LAYER M4 ;
        RECT  17.088 59.904 17.28 59.928 ;
    END
  END i[556]
  PIN i[557]
    DIRECTION INPUT ;
    USE SIGNAL ;
    PORT
      LAYER M4 ;
        RECT  17.088 60.048 17.28 60.072 ;
    END
  END i[557]
  PIN i[558]
    DIRECTION INPUT ;
    USE SIGNAL ;
    PORT
      LAYER M4 ;
        RECT  17.088 60.144 17.28 60.168 ;
    END
  END i[558]
  PIN i[559]
    DIRECTION INPUT ;
    USE SIGNAL ;
    PORT
      LAYER M4 ;
        RECT  17.088 60.24 17.28 60.264 ;
    END
  END i[559]
  PIN i[55]
    DIRECTION INPUT ;
    USE SIGNAL ;
    PORT
      LAYER M4 ;
        RECT  17.088 7.92 17.28 7.944 ;
    END
  END i[55]
  PIN i[560]
    DIRECTION INPUT ;
    USE SIGNAL ;
    PORT
      LAYER M4 ;
        RECT  17.088 60.336 17.28 60.36 ;
    END
  END i[560]
  PIN i[561]
    DIRECTION INPUT ;
    USE SIGNAL ;
    PORT
      LAYER M4 ;
        RECT  17.088 60.432 17.28 60.456 ;
    END
  END i[561]
  PIN i[56]
    DIRECTION INPUT ;
    USE SIGNAL ;
    PORT
      LAYER M4 ;
        RECT  17.088 8.016 17.28 8.04 ;
    END
  END i[56]
  PIN i[57]
    DIRECTION INPUT ;
    USE SIGNAL ;
    PORT
      LAYER M4 ;
        RECT  17.088 8.16 17.28 8.184 ;
    END
  END i[57]
  PIN i[58]
    DIRECTION INPUT ;
    USE SIGNAL ;
    PORT
      LAYER M4 ;
        RECT  17.088 8.256 17.28 8.28 ;
    END
  END i[58]
  PIN i[59]
    DIRECTION INPUT ;
    USE SIGNAL ;
    PORT
      LAYER M4 ;
        RECT  17.088 8.352 17.28 8.376 ;
    END
  END i[59]
  PIN i[5]
    DIRECTION INPUT ;
    USE SIGNAL ;
    PORT
      LAYER M4 ;
        RECT  17.088 2.736 17.28 2.76 ;
    END
  END i[5]
  PIN i[60]
    DIRECTION INPUT ;
    USE SIGNAL ;
    PORT
      LAYER M4 ;
        RECT  17.088 8.448 17.28 8.472 ;
    END
  END i[60]
  PIN i[61]
    DIRECTION INPUT ;
    USE SIGNAL ;
    PORT
      LAYER M4 ;
        RECT  17.088 8.544 17.28 8.568 ;
    END
  END i[61]
  PIN i[62]
    DIRECTION INPUT ;
    USE SIGNAL ;
    PORT
      LAYER M4 ;
        RECT  17.088 8.64 17.28 8.664 ;
    END
  END i[62]
  PIN i[63]
    DIRECTION INPUT ;
    USE SIGNAL ;
    PORT
      LAYER M4 ;
        RECT  17.088 8.784 17.28 8.808 ;
    END
  END i[63]
  PIN i[64]
    DIRECTION INPUT ;
    USE SIGNAL ;
    PORT
      LAYER M4 ;
        RECT  17.088 8.88 17.28 8.904 ;
    END
  END i[64]
  PIN i[65]
    DIRECTION INPUT ;
    USE SIGNAL ;
    PORT
      LAYER M4 ;
        RECT  17.088 8.976 17.28 9 ;
    END
  END i[65]
  PIN i[66]
    DIRECTION INPUT ;
    USE SIGNAL ;
    PORT
      LAYER M4 ;
        RECT  17.088 9.072 17.28 9.096 ;
    END
  END i[66]
  PIN i[67]
    DIRECTION INPUT ;
    USE SIGNAL ;
    PORT
      LAYER M4 ;
        RECT  17.088 9.168 17.28 9.192 ;
    END
  END i[67]
  PIN i[68]
    DIRECTION INPUT ;
    USE SIGNAL ;
    PORT
      LAYER M4 ;
        RECT  17.088 9.264 17.28 9.288 ;
    END
  END i[68]
  PIN i[69]
    DIRECTION INPUT ;
    USE SIGNAL ;
    PORT
      LAYER M4 ;
        RECT  17.088 9.408 17.28 9.432 ;
    END
  END i[69]
  PIN i[6]
    DIRECTION INPUT ;
    USE SIGNAL ;
    PORT
      LAYER M4 ;
        RECT  17.088 2.832 17.28 2.856 ;
    END
  END i[6]
  PIN i[70]
    DIRECTION INPUT ;
    USE SIGNAL ;
    PORT
      LAYER M4 ;
        RECT  17.088 9.504 17.28 9.528 ;
    END
  END i[70]
  PIN i[71]
    DIRECTION INPUT ;
    USE SIGNAL ;
    PORT
      LAYER M4 ;
        RECT  17.088 9.6 17.28 9.624 ;
    END
  END i[71]
  PIN i[72]
    DIRECTION INPUT ;
    USE SIGNAL ;
    PORT
      LAYER M4 ;
        RECT  17.088 9.696 17.28 9.72 ;
    END
  END i[72]
  PIN i[73]
    DIRECTION INPUT ;
    USE SIGNAL ;
    PORT
      LAYER M4 ;
        RECT  17.088 9.792 17.28 9.816 ;
    END
  END i[73]
  PIN i[74]
    DIRECTION INPUT ;
    USE SIGNAL ;
    PORT
      LAYER M4 ;
        RECT  17.088 9.888 17.28 9.912 ;
    END
  END i[74]
  PIN i[75]
    DIRECTION INPUT ;
    USE SIGNAL ;
    PORT
      LAYER M4 ;
        RECT  17.088 9.984 17.28 10.008 ;
    END
  END i[75]
  PIN i[76]
    DIRECTION INPUT ;
    USE SIGNAL ;
    PORT
      LAYER M4 ;
        RECT  17.088 10.128 17.28 10.152 ;
    END
  END i[76]
  PIN i[77]
    DIRECTION INPUT ;
    USE SIGNAL ;
    PORT
      LAYER M4 ;
        RECT  17.088 10.224 17.28 10.248 ;
    END
  END i[77]
  PIN i[78]
    DIRECTION INPUT ;
    USE SIGNAL ;
    PORT
      LAYER M4 ;
        RECT  17.088 10.32 17.28 10.344 ;
    END
  END i[78]
  PIN i[79]
    DIRECTION INPUT ;
    USE SIGNAL ;
    PORT
      LAYER M4 ;
        RECT  17.088 10.416 17.28 10.44 ;
    END
  END i[79]
  PIN i[7]
    DIRECTION INPUT ;
    USE SIGNAL ;
    PORT
      LAYER M4 ;
        RECT  17.088 2.928 17.28 2.952 ;
    END
  END i[7]
  PIN i[80]
    DIRECTION INPUT ;
    USE SIGNAL ;
    PORT
      LAYER M4 ;
        RECT  17.088 10.512 17.28 10.536 ;
    END
  END i[80]
  PIN i[81]
    DIRECTION INPUT ;
    USE SIGNAL ;
    PORT
      LAYER M4 ;
        RECT  17.088 10.608 17.28 10.632 ;
    END
  END i[81]
  PIN i[82]
    DIRECTION INPUT ;
    USE SIGNAL ;
    PORT
      LAYER M4 ;
        RECT  17.088 10.752 17.28 10.776 ;
    END
  END i[82]
  PIN i[83]
    DIRECTION INPUT ;
    USE SIGNAL ;
    PORT
      LAYER M4 ;
        RECT  17.088 10.848 17.28 10.872 ;
    END
  END i[83]
  PIN i[84]
    DIRECTION INPUT ;
    USE SIGNAL ;
    PORT
      LAYER M4 ;
        RECT  17.088 10.944 17.28 10.968 ;
    END
  END i[84]
  PIN i[85]
    DIRECTION INPUT ;
    USE SIGNAL ;
    PORT
      LAYER M4 ;
        RECT  17.088 11.04 17.28 11.064 ;
    END
  END i[85]
  PIN i[86]
    DIRECTION INPUT ;
    USE SIGNAL ;
    PORT
      LAYER M4 ;
        RECT  17.088 11.136 17.28 11.16 ;
    END
  END i[86]
  PIN i[87]
    DIRECTION INPUT ;
    USE SIGNAL ;
    PORT
      LAYER M4 ;
        RECT  17.088 11.232 17.28 11.256 ;
    END
  END i[87]
  PIN i[88]
    DIRECTION INPUT ;
    USE SIGNAL ;
    PORT
      LAYER M4 ;
        RECT  17.088 11.376 17.28 11.4 ;
    END
  END i[88]
  PIN i[89]
    DIRECTION INPUT ;
    USE SIGNAL ;
    PORT
      LAYER M4 ;
        RECT  17.088 11.472 17.28 11.496 ;
    END
  END i[89]
  PIN i[8]
    DIRECTION INPUT ;
    USE SIGNAL ;
    PORT
      LAYER M4 ;
        RECT  17.088 3.072 17.28 3.096 ;
    END
  END i[8]
  PIN i[90]
    DIRECTION INPUT ;
    USE SIGNAL ;
    PORT
      LAYER M4 ;
        RECT  17.088 11.568 17.28 11.592 ;
    END
  END i[90]
  PIN i[91]
    DIRECTION INPUT ;
    USE SIGNAL ;
    PORT
      LAYER M4 ;
        RECT  17.088 11.664 17.28 11.688 ;
    END
  END i[91]
  PIN i[92]
    DIRECTION INPUT ;
    USE SIGNAL ;
    PORT
      LAYER M4 ;
        RECT  17.088 11.76 17.28 11.784 ;
    END
  END i[92]
  PIN i[93]
    DIRECTION INPUT ;
    USE SIGNAL ;
    PORT
      LAYER M4 ;
        RECT  17.088 11.856 17.28 11.88 ;
    END
  END i[93]
  PIN i[94]
    DIRECTION INPUT ;
    USE SIGNAL ;
    PORT
      LAYER M4 ;
        RECT  17.088 12 17.28 12.024 ;
    END
  END i[94]
  PIN i[95]
    DIRECTION INPUT ;
    USE SIGNAL ;
    PORT
      LAYER M4 ;
        RECT  17.088 12.096 17.28 12.12 ;
    END
  END i[95]
  PIN i[96]
    DIRECTION INPUT ;
    USE SIGNAL ;
    PORT
      LAYER M4 ;
        RECT  17.088 12.192 17.28 12.216 ;
    END
  END i[96]
  PIN i[97]
    DIRECTION INPUT ;
    USE SIGNAL ;
    PORT
      LAYER M4 ;
        RECT  17.088 12.288 17.28 12.312 ;
    END
  END i[97]
  PIN i[98]
    DIRECTION INPUT ;
    USE SIGNAL ;
    PORT
      LAYER M4 ;
        RECT  17.088 12.384 17.28 12.408 ;
    END
  END i[98]
  PIN i[99]
    DIRECTION INPUT ;
    USE SIGNAL ;
    PORT
      LAYER M4 ;
        RECT  17.088 12.48 17.28 12.504 ;
    END
  END i[99]
  PIN i[9]
    DIRECTION INPUT ;
    USE SIGNAL ;
    PORT
      LAYER M4 ;
        RECT  17.088 3.168 17.28 3.192 ;
    END
  END i[9]
  PIN o[0]
    DIRECTION OUTPUT ;
    USE SIGNAL ;
    PORT
      LAYER M4 ;
        RECT  0 2.208 0.192 2.232 ;
    END
  END o[0]
  PIN o[100]
    DIRECTION OUTPUT ;
    USE SIGNAL ;
    PORT
      LAYER M4 ;
        RECT  0 12.576 0.192 12.6 ;
    END
  END o[100]
  PIN o[101]
    DIRECTION OUTPUT ;
    USE SIGNAL ;
    PORT
      LAYER M4 ;
        RECT  0 12.672 0.192 12.696 ;
    END
  END o[101]
  PIN o[102]
    DIRECTION OUTPUT ;
    USE SIGNAL ;
    PORT
      LAYER M4 ;
        RECT  0 12.768 0.192 12.792 ;
    END
  END o[102]
  PIN o[103]
    DIRECTION OUTPUT ;
    USE SIGNAL ;
    PORT
      LAYER M4 ;
        RECT  0 12.912 0.192 12.936 ;
    END
  END o[103]
  PIN o[104]
    DIRECTION OUTPUT ;
    USE SIGNAL ;
    PORT
      LAYER M4 ;
        RECT  0 13.008 0.192 13.032 ;
    END
  END o[104]
  PIN o[105]
    DIRECTION OUTPUT ;
    USE SIGNAL ;
    PORT
      LAYER M4 ;
        RECT  0 13.104 0.192 13.128 ;
    END
  END o[105]
  PIN o[106]
    DIRECTION OUTPUT ;
    USE SIGNAL ;
    PORT
      LAYER M4 ;
        RECT  0 13.2 0.192 13.224 ;
    END
  END o[106]
  PIN o[107]
    DIRECTION OUTPUT ;
    USE SIGNAL ;
    PORT
      LAYER M4 ;
        RECT  0 13.296 0.192 13.32 ;
    END
  END o[107]
  PIN o[108]
    DIRECTION OUTPUT ;
    USE SIGNAL ;
    PORT
      LAYER M4 ;
        RECT  0 13.392 0.192 13.416 ;
    END
  END o[108]
  PIN o[109]
    DIRECTION OUTPUT ;
    USE SIGNAL ;
    PORT
      LAYER M4 ;
        RECT  0 13.536 0.192 13.56 ;
    END
  END o[109]
  PIN o[10]
    DIRECTION OUTPUT ;
    USE SIGNAL ;
    PORT
      LAYER M4 ;
        RECT  0 3.264 0.192 3.288 ;
    END
  END o[10]
  PIN o[110]
    DIRECTION OUTPUT ;
    USE SIGNAL ;
    PORT
      LAYER M4 ;
        RECT  0 13.632 0.192 13.656 ;
    END
  END o[110]
  PIN o[111]
    DIRECTION OUTPUT ;
    USE SIGNAL ;
    PORT
      LAYER M4 ;
        RECT  0 13.728 0.192 13.752 ;
    END
  END o[111]
  PIN o[112]
    DIRECTION OUTPUT ;
    USE SIGNAL ;
    PORT
      LAYER M4 ;
        RECT  0 13.824 0.192 13.848 ;
    END
  END o[112]
  PIN o[113]
    DIRECTION OUTPUT ;
    USE SIGNAL ;
    PORT
      LAYER M4 ;
        RECT  0 13.92 0.192 13.944 ;
    END
  END o[113]
  PIN o[114]
    DIRECTION OUTPUT ;
    USE SIGNAL ;
    PORT
      LAYER M4 ;
        RECT  0 14.016 0.192 14.04 ;
    END
  END o[114]
  PIN o[115]
    DIRECTION OUTPUT ;
    USE SIGNAL ;
    PORT
      LAYER M4 ;
        RECT  0 14.16 0.192 14.184 ;
    END
  END o[115]
  PIN o[116]
    DIRECTION OUTPUT ;
    USE SIGNAL ;
    PORT
      LAYER M4 ;
        RECT  0 14.256 0.192 14.28 ;
    END
  END o[116]
  PIN o[117]
    DIRECTION OUTPUT ;
    USE SIGNAL ;
    PORT
      LAYER M4 ;
        RECT  0 14.352 0.192 14.376 ;
    END
  END o[117]
  PIN o[118]
    DIRECTION OUTPUT ;
    USE SIGNAL ;
    PORT
      LAYER M4 ;
        RECT  0 14.448 0.192 14.472 ;
    END
  END o[118]
  PIN o[119]
    DIRECTION OUTPUT ;
    USE SIGNAL ;
    PORT
      LAYER M4 ;
        RECT  0 14.544 0.192 14.568 ;
    END
  END o[119]
  PIN o[11]
    DIRECTION OUTPUT ;
    USE SIGNAL ;
    PORT
      LAYER M4 ;
        RECT  0 3.36 0.192 3.384 ;
    END
  END o[11]
  PIN o[120]
    DIRECTION OUTPUT ;
    USE SIGNAL ;
    PORT
      LAYER M4 ;
        RECT  0 14.64 0.192 14.664 ;
    END
  END o[120]
  PIN o[121]
    DIRECTION OUTPUT ;
    USE SIGNAL ;
    PORT
      LAYER M4 ;
        RECT  0 14.736 0.192 14.76 ;
    END
  END o[121]
  PIN o[122]
    DIRECTION OUTPUT ;
    USE SIGNAL ;
    PORT
      LAYER M4 ;
        RECT  0 14.88 0.192 14.904 ;
    END
  END o[122]
  PIN o[123]
    DIRECTION OUTPUT ;
    USE SIGNAL ;
    PORT
      LAYER M4 ;
        RECT  0 14.976 0.192 15 ;
    END
  END o[123]
  PIN o[124]
    DIRECTION OUTPUT ;
    USE SIGNAL ;
    PORT
      LAYER M4 ;
        RECT  0 15.072 0.192 15.096 ;
    END
  END o[124]
  PIN o[125]
    DIRECTION OUTPUT ;
    USE SIGNAL ;
    PORT
      LAYER M4 ;
        RECT  0 15.168 0.192 15.192 ;
    END
  END o[125]
  PIN o[126]
    DIRECTION OUTPUT ;
    USE SIGNAL ;
    PORT
      LAYER M4 ;
        RECT  0 15.264 0.192 15.288 ;
    END
  END o[126]
  PIN o[127]
    DIRECTION OUTPUT ;
    USE SIGNAL ;
    PORT
      LAYER M4 ;
        RECT  0 15.36 0.192 15.384 ;
    END
  END o[127]
  PIN o[128]
    DIRECTION OUTPUT ;
    USE SIGNAL ;
    PORT
      LAYER M4 ;
        RECT  0 15.504 0.192 15.528 ;
    END
  END o[128]
  PIN o[129]
    DIRECTION OUTPUT ;
    USE SIGNAL ;
    PORT
      LAYER M4 ;
        RECT  0 15.6 0.192 15.624 ;
    END
  END o[129]
  PIN o[12]
    DIRECTION OUTPUT ;
    USE SIGNAL ;
    PORT
      LAYER M4 ;
        RECT  0 3.456 0.192 3.48 ;
    END
  END o[12]
  PIN o[130]
    DIRECTION OUTPUT ;
    USE SIGNAL ;
    PORT
      LAYER M4 ;
        RECT  0 15.696 0.192 15.72 ;
    END
  END o[130]
  PIN o[131]
    DIRECTION OUTPUT ;
    USE SIGNAL ;
    PORT
      LAYER M4 ;
        RECT  0 15.792 0.192 15.816 ;
    END
  END o[131]
  PIN o[132]
    DIRECTION OUTPUT ;
    USE SIGNAL ;
    PORT
      LAYER M4 ;
        RECT  0 15.888 0.192 15.912 ;
    END
  END o[132]
  PIN o[133]
    DIRECTION OUTPUT ;
    USE SIGNAL ;
    PORT
      LAYER M4 ;
        RECT  0 15.984 0.192 16.008 ;
    END
  END o[133]
  PIN o[134]
    DIRECTION OUTPUT ;
    USE SIGNAL ;
    PORT
      LAYER M4 ;
        RECT  0 16.128 0.192 16.152 ;
    END
  END o[134]
  PIN o[135]
    DIRECTION OUTPUT ;
    USE SIGNAL ;
    PORT
      LAYER M4 ;
        RECT  0 16.224 0.192 16.248 ;
    END
  END o[135]
  PIN o[136]
    DIRECTION OUTPUT ;
    USE SIGNAL ;
    PORT
      LAYER M4 ;
        RECT  0 16.32 0.192 16.344 ;
    END
  END o[136]
  PIN o[137]
    DIRECTION OUTPUT ;
    USE SIGNAL ;
    PORT
      LAYER M4 ;
        RECT  0 16.416 0.192 16.44 ;
    END
  END o[137]
  PIN o[138]
    DIRECTION OUTPUT ;
    USE SIGNAL ;
    PORT
      LAYER M4 ;
        RECT  0 16.512 0.192 16.536 ;
    END
  END o[138]
  PIN o[139]
    DIRECTION OUTPUT ;
    USE SIGNAL ;
    PORT
      LAYER M4 ;
        RECT  0 16.608 0.192 16.632 ;
    END
  END o[139]
  PIN o[13]
    DIRECTION OUTPUT ;
    USE SIGNAL ;
    PORT
      LAYER M4 ;
        RECT  0 3.552 0.192 3.576 ;
    END
  END o[13]
  PIN o[140]
    DIRECTION OUTPUT ;
    USE SIGNAL ;
    PORT
      LAYER M4 ;
        RECT  0 16.704 0.192 16.728 ;
    END
  END o[140]
  PIN o[141]
    DIRECTION OUTPUT ;
    USE SIGNAL ;
    PORT
      LAYER M4 ;
        RECT  0 16.848 0.192 16.872 ;
    END
  END o[141]
  PIN o[142]
    DIRECTION OUTPUT ;
    USE SIGNAL ;
    PORT
      LAYER M4 ;
        RECT  0 16.944 0.192 16.968 ;
    END
  END o[142]
  PIN o[143]
    DIRECTION OUTPUT ;
    USE SIGNAL ;
    PORT
      LAYER M4 ;
        RECT  0 17.04 0.192 17.064 ;
    END
  END o[143]
  PIN o[144]
    DIRECTION OUTPUT ;
    USE SIGNAL ;
    PORT
      LAYER M4 ;
        RECT  0 17.136 0.192 17.16 ;
    END
  END o[144]
  PIN o[145]
    DIRECTION OUTPUT ;
    USE SIGNAL ;
    PORT
      LAYER M4 ;
        RECT  0 17.232 0.192 17.256 ;
    END
  END o[145]
  PIN o[146]
    DIRECTION OUTPUT ;
    USE SIGNAL ;
    PORT
      LAYER M4 ;
        RECT  0 17.328 0.192 17.352 ;
    END
  END o[146]
  PIN o[147]
    DIRECTION OUTPUT ;
    USE SIGNAL ;
    PORT
      LAYER M4 ;
        RECT  0 17.472 0.192 17.496 ;
    END
  END o[147]
  PIN o[148]
    DIRECTION OUTPUT ;
    USE SIGNAL ;
    PORT
      LAYER M4 ;
        RECT  0 17.568 0.192 17.592 ;
    END
  END o[148]
  PIN o[149]
    DIRECTION OUTPUT ;
    USE SIGNAL ;
    PORT
      LAYER M4 ;
        RECT  0 17.664 0.192 17.688 ;
    END
  END o[149]
  PIN o[14]
    DIRECTION OUTPUT ;
    USE SIGNAL ;
    PORT
      LAYER M4 ;
        RECT  0 3.696 0.192 3.72 ;
    END
  END o[14]
  PIN o[150]
    DIRECTION OUTPUT ;
    USE SIGNAL ;
    PORT
      LAYER M4 ;
        RECT  0 17.76 0.192 17.784 ;
    END
  END o[150]
  PIN o[151]
    DIRECTION OUTPUT ;
    USE SIGNAL ;
    PORT
      LAYER M4 ;
        RECT  0 17.856 0.192 17.88 ;
    END
  END o[151]
  PIN o[152]
    DIRECTION OUTPUT ;
    USE SIGNAL ;
    PORT
      LAYER M4 ;
        RECT  0 17.952 0.192 17.976 ;
    END
  END o[152]
  PIN o[153]
    DIRECTION OUTPUT ;
    USE SIGNAL ;
    PORT
      LAYER M4 ;
        RECT  0 18.096 0.192 18.12 ;
    END
  END o[153]
  PIN o[154]
    DIRECTION OUTPUT ;
    USE SIGNAL ;
    PORT
      LAYER M4 ;
        RECT  0 18.192 0.192 18.216 ;
    END
  END o[154]
  PIN o[155]
    DIRECTION OUTPUT ;
    USE SIGNAL ;
    PORT
      LAYER M4 ;
        RECT  0 18.288 0.192 18.312 ;
    END
  END o[155]
  PIN o[156]
    DIRECTION OUTPUT ;
    USE SIGNAL ;
    PORT
      LAYER M4 ;
        RECT  0 18.384 0.192 18.408 ;
    END
  END o[156]
  PIN o[157]
    DIRECTION OUTPUT ;
    USE SIGNAL ;
    PORT
      LAYER M4 ;
        RECT  0 18.48 0.192 18.504 ;
    END
  END o[157]
  PIN o[158]
    DIRECTION OUTPUT ;
    USE SIGNAL ;
    PORT
      LAYER M4 ;
        RECT  0 18.576 0.192 18.6 ;
    END
  END o[158]
  PIN o[159]
    DIRECTION OUTPUT ;
    USE SIGNAL ;
    PORT
      LAYER M4 ;
        RECT  0 18.672 0.192 18.696 ;
    END
  END o[159]
  PIN o[15]
    DIRECTION OUTPUT ;
    USE SIGNAL ;
    PORT
      LAYER M4 ;
        RECT  0 3.792 0.192 3.816 ;
    END
  END o[15]
  PIN o[160]
    DIRECTION OUTPUT ;
    USE SIGNAL ;
    PORT
      LAYER M4 ;
        RECT  0 18.816 0.192 18.84 ;
    END
  END o[160]
  PIN o[161]
    DIRECTION OUTPUT ;
    USE SIGNAL ;
    PORT
      LAYER M4 ;
        RECT  0 18.912 0.192 18.936 ;
    END
  END o[161]
  PIN o[162]
    DIRECTION OUTPUT ;
    USE SIGNAL ;
    PORT
      LAYER M4 ;
        RECT  0 19.008 0.192 19.032 ;
    END
  END o[162]
  PIN o[163]
    DIRECTION OUTPUT ;
    USE SIGNAL ;
    PORT
      LAYER M4 ;
        RECT  0 19.104 0.192 19.128 ;
    END
  END o[163]
  PIN o[164]
    DIRECTION OUTPUT ;
    USE SIGNAL ;
    PORT
      LAYER M4 ;
        RECT  0 19.2 0.192 19.224 ;
    END
  END o[164]
  PIN o[165]
    DIRECTION OUTPUT ;
    USE SIGNAL ;
    PORT
      LAYER M4 ;
        RECT  0 19.296 0.192 19.32 ;
    END
  END o[165]
  PIN o[166]
    DIRECTION OUTPUT ;
    USE SIGNAL ;
    PORT
      LAYER M4 ;
        RECT  0 19.44 0.192 19.464 ;
    END
  END o[166]
  PIN o[167]
    DIRECTION OUTPUT ;
    USE SIGNAL ;
    PORT
      LAYER M4 ;
        RECT  0 19.536 0.192 19.56 ;
    END
  END o[167]
  PIN o[168]
    DIRECTION OUTPUT ;
    USE SIGNAL ;
    PORT
      LAYER M4 ;
        RECT  0 19.632 0.192 19.656 ;
    END
  END o[168]
  PIN o[169]
    DIRECTION OUTPUT ;
    USE SIGNAL ;
    PORT
      LAYER M4 ;
        RECT  0 19.728 0.192 19.752 ;
    END
  END o[169]
  PIN o[16]
    DIRECTION OUTPUT ;
    USE SIGNAL ;
    PORT
      LAYER M4 ;
        RECT  0 3.888 0.192 3.912 ;
    END
  END o[16]
  PIN o[170]
    DIRECTION OUTPUT ;
    USE SIGNAL ;
    PORT
      LAYER M4 ;
        RECT  0 19.824 0.192 19.848 ;
    END
  END o[170]
  PIN o[171]
    DIRECTION OUTPUT ;
    USE SIGNAL ;
    PORT
      LAYER M4 ;
        RECT  0 19.92 0.192 19.944 ;
    END
  END o[171]
  PIN o[172]
    DIRECTION OUTPUT ;
    USE SIGNAL ;
    PORT
      LAYER M4 ;
        RECT  0 20.064 0.192 20.088 ;
    END
  END o[172]
  PIN o[173]
    DIRECTION OUTPUT ;
    USE SIGNAL ;
    PORT
      LAYER M4 ;
        RECT  0 20.16 0.192 20.184 ;
    END
  END o[173]
  PIN o[174]
    DIRECTION OUTPUT ;
    USE SIGNAL ;
    PORT
      LAYER M4 ;
        RECT  0 20.256 0.192 20.28 ;
    END
  END o[174]
  PIN o[175]
    DIRECTION OUTPUT ;
    USE SIGNAL ;
    PORT
      LAYER M4 ;
        RECT  0 20.352 0.192 20.376 ;
    END
  END o[175]
  PIN o[176]
    DIRECTION OUTPUT ;
    USE SIGNAL ;
    PORT
      LAYER M4 ;
        RECT  0 20.448 0.192 20.472 ;
    END
  END o[176]
  PIN o[177]
    DIRECTION OUTPUT ;
    USE SIGNAL ;
    PORT
      LAYER M4 ;
        RECT  0 20.544 0.192 20.568 ;
    END
  END o[177]
  PIN o[178]
    DIRECTION OUTPUT ;
    USE SIGNAL ;
    PORT
      LAYER M4 ;
        RECT  0 20.64 0.192 20.664 ;
    END
  END o[178]
  PIN o[179]
    DIRECTION OUTPUT ;
    USE SIGNAL ;
    PORT
      LAYER M4 ;
        RECT  0 20.784 0.192 20.808 ;
    END
  END o[179]
  PIN o[17]
    DIRECTION OUTPUT ;
    USE SIGNAL ;
    PORT
      LAYER M4 ;
        RECT  0 3.984 0.192 4.008 ;
    END
  END o[17]
  PIN o[180]
    DIRECTION OUTPUT ;
    USE SIGNAL ;
    PORT
      LAYER M4 ;
        RECT  0 20.88 0.192 20.904 ;
    END
  END o[180]
  PIN o[181]
    DIRECTION OUTPUT ;
    USE SIGNAL ;
    PORT
      LAYER M4 ;
        RECT  0 20.976 0.192 21 ;
    END
  END o[181]
  PIN o[182]
    DIRECTION OUTPUT ;
    USE SIGNAL ;
    PORT
      LAYER M4 ;
        RECT  0 21.072 0.192 21.096 ;
    END
  END o[182]
  PIN o[183]
    DIRECTION OUTPUT ;
    USE SIGNAL ;
    PORT
      LAYER M4 ;
        RECT  0 21.168 0.192 21.192 ;
    END
  END o[183]
  PIN o[184]
    DIRECTION OUTPUT ;
    USE SIGNAL ;
    PORT
      LAYER M4 ;
        RECT  0 21.264 0.192 21.288 ;
    END
  END o[184]
  PIN o[185]
    DIRECTION OUTPUT ;
    USE SIGNAL ;
    PORT
      LAYER M4 ;
        RECT  0 21.408 0.192 21.432 ;
    END
  END o[185]
  PIN o[186]
    DIRECTION OUTPUT ;
    USE SIGNAL ;
    PORT
      LAYER M4 ;
        RECT  0 21.504 0.192 21.528 ;
    END
  END o[186]
  PIN o[187]
    DIRECTION OUTPUT ;
    USE SIGNAL ;
    PORT
      LAYER M4 ;
        RECT  0 21.6 0.192 21.624 ;
    END
  END o[187]
  PIN o[188]
    DIRECTION OUTPUT ;
    USE SIGNAL ;
    PORT
      LAYER M4 ;
        RECT  0 21.696 0.192 21.72 ;
    END
  END o[188]
  PIN o[189]
    DIRECTION OUTPUT ;
    USE SIGNAL ;
    PORT
      LAYER M4 ;
        RECT  0 21.792 0.192 21.816 ;
    END
  END o[189]
  PIN o[18]
    DIRECTION OUTPUT ;
    USE SIGNAL ;
    PORT
      LAYER M4 ;
        RECT  0 4.08 0.192 4.104 ;
    END
  END o[18]
  PIN o[190]
    DIRECTION OUTPUT ;
    USE SIGNAL ;
    PORT
      LAYER M4 ;
        RECT  0 21.888 0.192 21.912 ;
    END
  END o[190]
  PIN o[191]
    DIRECTION OUTPUT ;
    USE SIGNAL ;
    PORT
      LAYER M4 ;
        RECT  0 22.032 0.192 22.056 ;
    END
  END o[191]
  PIN o[192]
    DIRECTION OUTPUT ;
    USE SIGNAL ;
    PORT
      LAYER M4 ;
        RECT  0 22.128 0.192 22.152 ;
    END
  END o[192]
  PIN o[193]
    DIRECTION OUTPUT ;
    USE SIGNAL ;
    PORT
      LAYER M4 ;
        RECT  0 22.224 0.192 22.248 ;
    END
  END o[193]
  PIN o[194]
    DIRECTION OUTPUT ;
    USE SIGNAL ;
    PORT
      LAYER M4 ;
        RECT  0 22.32 0.192 22.344 ;
    END
  END o[194]
  PIN o[195]
    DIRECTION OUTPUT ;
    USE SIGNAL ;
    PORT
      LAYER M4 ;
        RECT  0 22.416 0.192 22.44 ;
    END
  END o[195]
  PIN o[196]
    DIRECTION OUTPUT ;
    USE SIGNAL ;
    PORT
      LAYER M4 ;
        RECT  0 22.512 0.192 22.536 ;
    END
  END o[196]
  PIN o[197]
    DIRECTION OUTPUT ;
    USE SIGNAL ;
    PORT
      LAYER M4 ;
        RECT  0 22.608 0.192 22.632 ;
    END
  END o[197]
  PIN o[198]
    DIRECTION OUTPUT ;
    USE SIGNAL ;
    PORT
      LAYER M4 ;
        RECT  0 22.752 0.192 22.776 ;
    END
  END o[198]
  PIN o[199]
    DIRECTION OUTPUT ;
    USE SIGNAL ;
    PORT
      LAYER M4 ;
        RECT  0 22.848 0.192 22.872 ;
    END
  END o[199]
  PIN o[19]
    DIRECTION OUTPUT ;
    USE SIGNAL ;
    PORT
      LAYER M4 ;
        RECT  0 4.176 0.192 4.2 ;
    END
  END o[19]
  PIN o[1]
    DIRECTION OUTPUT ;
    USE SIGNAL ;
    PORT
      LAYER M4 ;
        RECT  0 2.304 0.192 2.328 ;
    END
  END o[1]
  PIN o[200]
    DIRECTION OUTPUT ;
    USE SIGNAL ;
    PORT
      LAYER M4 ;
        RECT  0 22.944 0.192 22.968 ;
    END
  END o[200]
  PIN o[201]
    DIRECTION OUTPUT ;
    USE SIGNAL ;
    PORT
      LAYER M4 ;
        RECT  0 23.04 0.192 23.064 ;
    END
  END o[201]
  PIN o[202]
    DIRECTION OUTPUT ;
    USE SIGNAL ;
    PORT
      LAYER M4 ;
        RECT  0 23.136 0.192 23.16 ;
    END
  END o[202]
  PIN o[203]
    DIRECTION OUTPUT ;
    USE SIGNAL ;
    PORT
      LAYER M4 ;
        RECT  0 23.232 0.192 23.256 ;
    END
  END o[203]
  PIN o[204]
    DIRECTION OUTPUT ;
    USE SIGNAL ;
    PORT
      LAYER M4 ;
        RECT  0 23.376 0.192 23.4 ;
    END
  END o[204]
  PIN o[205]
    DIRECTION OUTPUT ;
    USE SIGNAL ;
    PORT
      LAYER M4 ;
        RECT  0 23.472 0.192 23.496 ;
    END
  END o[205]
  PIN o[206]
    DIRECTION OUTPUT ;
    USE SIGNAL ;
    PORT
      LAYER M4 ;
        RECT  0 23.568 0.192 23.592 ;
    END
  END o[206]
  PIN o[207]
    DIRECTION OUTPUT ;
    USE SIGNAL ;
    PORT
      LAYER M4 ;
        RECT  0 23.664 0.192 23.688 ;
    END
  END o[207]
  PIN o[208]
    DIRECTION OUTPUT ;
    USE SIGNAL ;
    PORT
      LAYER M4 ;
        RECT  0 23.76 0.192 23.784 ;
    END
  END o[208]
  PIN o[209]
    DIRECTION OUTPUT ;
    USE SIGNAL ;
    PORT
      LAYER M4 ;
        RECT  0 23.856 0.192 23.88 ;
    END
  END o[209]
  PIN o[20]
    DIRECTION OUTPUT ;
    USE SIGNAL ;
    PORT
      LAYER M4 ;
        RECT  0 4.272 0.192 4.296 ;
    END
  END o[20]
  PIN o[210]
    DIRECTION OUTPUT ;
    USE SIGNAL ;
    PORT
      LAYER M4 ;
        RECT  0 24 0.192 24.024 ;
    END
  END o[210]
  PIN o[211]
    DIRECTION OUTPUT ;
    USE SIGNAL ;
    PORT
      LAYER M4 ;
        RECT  0 24.096 0.192 24.12 ;
    END
  END o[211]
  PIN o[212]
    DIRECTION OUTPUT ;
    USE SIGNAL ;
    PORT
      LAYER M4 ;
        RECT  0 24.192 0.192 24.216 ;
    END
  END o[212]
  PIN o[213]
    DIRECTION OUTPUT ;
    USE SIGNAL ;
    PORT
      LAYER M4 ;
        RECT  0 24.288 0.192 24.312 ;
    END
  END o[213]
  PIN o[214]
    DIRECTION OUTPUT ;
    USE SIGNAL ;
    PORT
      LAYER M4 ;
        RECT  0 24.384 0.192 24.408 ;
    END
  END o[214]
  PIN o[215]
    DIRECTION OUTPUT ;
    USE SIGNAL ;
    PORT
      LAYER M4 ;
        RECT  0 24.48 0.192 24.504 ;
    END
  END o[215]
  PIN o[216]
    DIRECTION OUTPUT ;
    USE SIGNAL ;
    PORT
      LAYER M4 ;
        RECT  0 24.576 0.192 24.6 ;
    END
  END o[216]
  PIN o[217]
    DIRECTION OUTPUT ;
    USE SIGNAL ;
    PORT
      LAYER M4 ;
        RECT  0 24.72 0.192 24.744 ;
    END
  END o[217]
  PIN o[218]
    DIRECTION OUTPUT ;
    USE SIGNAL ;
    PORT
      LAYER M4 ;
        RECT  0 24.816 0.192 24.84 ;
    END
  END o[218]
  PIN o[219]
    DIRECTION OUTPUT ;
    USE SIGNAL ;
    PORT
      LAYER M4 ;
        RECT  0 24.912 0.192 24.936 ;
    END
  END o[219]
  PIN o[21]
    DIRECTION OUTPUT ;
    USE SIGNAL ;
    PORT
      LAYER M4 ;
        RECT  0 4.416 0.192 4.44 ;
    END
  END o[21]
  PIN o[220]
    DIRECTION OUTPUT ;
    USE SIGNAL ;
    PORT
      LAYER M4 ;
        RECT  0 25.008 0.192 25.032 ;
    END
  END o[220]
  PIN o[221]
    DIRECTION OUTPUT ;
    USE SIGNAL ;
    PORT
      LAYER M4 ;
        RECT  0 25.104 0.192 25.128 ;
    END
  END o[221]
  PIN o[222]
    DIRECTION OUTPUT ;
    USE SIGNAL ;
    PORT
      LAYER M4 ;
        RECT  0 25.2 0.192 25.224 ;
    END
  END o[222]
  PIN o[223]
    DIRECTION OUTPUT ;
    USE SIGNAL ;
    PORT
      LAYER M4 ;
        RECT  0 25.344 0.192 25.368 ;
    END
  END o[223]
  PIN o[224]
    DIRECTION OUTPUT ;
    USE SIGNAL ;
    PORT
      LAYER M4 ;
        RECT  0 25.44 0.192 25.464 ;
    END
  END o[224]
  PIN o[225]
    DIRECTION OUTPUT ;
    USE SIGNAL ;
    PORT
      LAYER M4 ;
        RECT  0 25.536 0.192 25.56 ;
    END
  END o[225]
  PIN o[226]
    DIRECTION OUTPUT ;
    USE SIGNAL ;
    PORT
      LAYER M4 ;
        RECT  0 25.632 0.192 25.656 ;
    END
  END o[226]
  PIN o[227]
    DIRECTION OUTPUT ;
    USE SIGNAL ;
    PORT
      LAYER M4 ;
        RECT  0 25.728 0.192 25.752 ;
    END
  END o[227]
  PIN o[228]
    DIRECTION OUTPUT ;
    USE SIGNAL ;
    PORT
      LAYER M4 ;
        RECT  0 25.824 0.192 25.848 ;
    END
  END o[228]
  PIN o[229]
    DIRECTION OUTPUT ;
    USE SIGNAL ;
    PORT
      LAYER M4 ;
        RECT  0 25.968 0.192 25.992 ;
    END
  END o[229]
  PIN o[22]
    DIRECTION OUTPUT ;
    USE SIGNAL ;
    PORT
      LAYER M4 ;
        RECT  0 4.512 0.192 4.536 ;
    END
  END o[22]
  PIN o[230]
    DIRECTION OUTPUT ;
    USE SIGNAL ;
    PORT
      LAYER M4 ;
        RECT  0 26.064 0.192 26.088 ;
    END
  END o[230]
  PIN o[231]
    DIRECTION OUTPUT ;
    USE SIGNAL ;
    PORT
      LAYER M4 ;
        RECT  0 26.16 0.192 26.184 ;
    END
  END o[231]
  PIN o[232]
    DIRECTION OUTPUT ;
    USE SIGNAL ;
    PORT
      LAYER M4 ;
        RECT  0 26.256 0.192 26.28 ;
    END
  END o[232]
  PIN o[233]
    DIRECTION OUTPUT ;
    USE SIGNAL ;
    PORT
      LAYER M4 ;
        RECT  0 26.352 0.192 26.376 ;
    END
  END o[233]
  PIN o[234]
    DIRECTION OUTPUT ;
    USE SIGNAL ;
    PORT
      LAYER M4 ;
        RECT  0 26.448 0.192 26.472 ;
    END
  END o[234]
  PIN o[235]
    DIRECTION OUTPUT ;
    USE SIGNAL ;
    PORT
      LAYER M4 ;
        RECT  0 26.544 0.192 26.568 ;
    END
  END o[235]
  PIN o[236]
    DIRECTION OUTPUT ;
    USE SIGNAL ;
    PORT
      LAYER M4 ;
        RECT  0 26.688 0.192 26.712 ;
    END
  END o[236]
  PIN o[237]
    DIRECTION OUTPUT ;
    USE SIGNAL ;
    PORT
      LAYER M4 ;
        RECT  0 26.784 0.192 26.808 ;
    END
  END o[237]
  PIN o[238]
    DIRECTION OUTPUT ;
    USE SIGNAL ;
    PORT
      LAYER M4 ;
        RECT  0 26.88 0.192 26.904 ;
    END
  END o[238]
  PIN o[239]
    DIRECTION OUTPUT ;
    USE SIGNAL ;
    PORT
      LAYER M4 ;
        RECT  0 26.976 0.192 27 ;
    END
  END o[239]
  PIN o[23]
    DIRECTION OUTPUT ;
    USE SIGNAL ;
    PORT
      LAYER M4 ;
        RECT  0 4.608 0.192 4.632 ;
    END
  END o[23]
  PIN o[240]
    DIRECTION OUTPUT ;
    USE SIGNAL ;
    PORT
      LAYER M4 ;
        RECT  0 27.072 0.192 27.096 ;
    END
  END o[240]
  PIN o[241]
    DIRECTION OUTPUT ;
    USE SIGNAL ;
    PORT
      LAYER M4 ;
        RECT  0 27.168 0.192 27.192 ;
    END
  END o[241]
  PIN o[242]
    DIRECTION OUTPUT ;
    USE SIGNAL ;
    PORT
      LAYER M4 ;
        RECT  0 27.312 0.192 27.336 ;
    END
  END o[242]
  PIN o[243]
    DIRECTION OUTPUT ;
    USE SIGNAL ;
    PORT
      LAYER M4 ;
        RECT  0 27.408 0.192 27.432 ;
    END
  END o[243]
  PIN o[244]
    DIRECTION OUTPUT ;
    USE SIGNAL ;
    PORT
      LAYER M4 ;
        RECT  0 27.504 0.192 27.528 ;
    END
  END o[244]
  PIN o[245]
    DIRECTION OUTPUT ;
    USE SIGNAL ;
    PORT
      LAYER M4 ;
        RECT  0 27.6 0.192 27.624 ;
    END
  END o[245]
  PIN o[246]
    DIRECTION OUTPUT ;
    USE SIGNAL ;
    PORT
      LAYER M4 ;
        RECT  0 27.696 0.192 27.72 ;
    END
  END o[246]
  PIN o[247]
    DIRECTION OUTPUT ;
    USE SIGNAL ;
    PORT
      LAYER M4 ;
        RECT  0 27.792 0.192 27.816 ;
    END
  END o[247]
  PIN o[248]
    DIRECTION OUTPUT ;
    USE SIGNAL ;
    PORT
      LAYER M4 ;
        RECT  0 27.936 0.192 27.96 ;
    END
  END o[248]
  PIN o[249]
    DIRECTION OUTPUT ;
    USE SIGNAL ;
    PORT
      LAYER M4 ;
        RECT  0 28.032 0.192 28.056 ;
    END
  END o[249]
  PIN o[24]
    DIRECTION OUTPUT ;
    USE SIGNAL ;
    PORT
      LAYER M4 ;
        RECT  0 4.704 0.192 4.728 ;
    END
  END o[24]
  PIN o[250]
    DIRECTION OUTPUT ;
    USE SIGNAL ;
    PORT
      LAYER M4 ;
        RECT  0 28.128 0.192 28.152 ;
    END
  END o[250]
  PIN o[251]
    DIRECTION OUTPUT ;
    USE SIGNAL ;
    PORT
      LAYER M4 ;
        RECT  0 28.224 0.192 28.248 ;
    END
  END o[251]
  PIN o[252]
    DIRECTION OUTPUT ;
    USE SIGNAL ;
    PORT
      LAYER M4 ;
        RECT  0 28.32 0.192 28.344 ;
    END
  END o[252]
  PIN o[253]
    DIRECTION OUTPUT ;
    USE SIGNAL ;
    PORT
      LAYER M4 ;
        RECT  0 28.416 0.192 28.44 ;
    END
  END o[253]
  PIN o[254]
    DIRECTION OUTPUT ;
    USE SIGNAL ;
    PORT
      LAYER M4 ;
        RECT  0 28.512 0.192 28.536 ;
    END
  END o[254]
  PIN o[255]
    DIRECTION OUTPUT ;
    USE SIGNAL ;
    PORT
      LAYER M4 ;
        RECT  0 28.656 0.192 28.68 ;
    END
  END o[255]
  PIN o[256]
    DIRECTION OUTPUT ;
    USE SIGNAL ;
    PORT
      LAYER M4 ;
        RECT  0 28.752 0.192 28.776 ;
    END
  END o[256]
  PIN o[257]
    DIRECTION OUTPUT ;
    USE SIGNAL ;
    PORT
      LAYER M4 ;
        RECT  0 28.848 0.192 28.872 ;
    END
  END o[257]
  PIN o[258]
    DIRECTION OUTPUT ;
    USE SIGNAL ;
    PORT
      LAYER M4 ;
        RECT  0 28.944 0.192 28.968 ;
    END
  END o[258]
  PIN o[259]
    DIRECTION OUTPUT ;
    USE SIGNAL ;
    PORT
      LAYER M4 ;
        RECT  0 29.04 0.192 29.064 ;
    END
  END o[259]
  PIN o[25]
    DIRECTION OUTPUT ;
    USE SIGNAL ;
    PORT
      LAYER M4 ;
        RECT  0 4.8 0.192 4.824 ;
    END
  END o[25]
  PIN o[260]
    DIRECTION OUTPUT ;
    USE SIGNAL ;
    PORT
      LAYER M4 ;
        RECT  0 29.136 0.192 29.16 ;
    END
  END o[260]
  PIN o[261]
    DIRECTION OUTPUT ;
    USE SIGNAL ;
    PORT
      LAYER M4 ;
        RECT  0 29.28 0.192 29.304 ;
    END
  END o[261]
  PIN o[262]
    DIRECTION OUTPUT ;
    USE SIGNAL ;
    PORT
      LAYER M4 ;
        RECT  0 29.376 0.192 29.4 ;
    END
  END o[262]
  PIN o[263]
    DIRECTION OUTPUT ;
    USE SIGNAL ;
    PORT
      LAYER M4 ;
        RECT  0 29.472 0.192 29.496 ;
    END
  END o[263]
  PIN o[264]
    DIRECTION OUTPUT ;
    USE SIGNAL ;
    PORT
      LAYER M4 ;
        RECT  0 29.568 0.192 29.592 ;
    END
  END o[264]
  PIN o[265]
    DIRECTION OUTPUT ;
    USE SIGNAL ;
    PORT
      LAYER M4 ;
        RECT  0 29.664 0.192 29.688 ;
    END
  END o[265]
  PIN o[266]
    DIRECTION OUTPUT ;
    USE SIGNAL ;
    PORT
      LAYER M4 ;
        RECT  0 29.76 0.192 29.784 ;
    END
  END o[266]
  PIN o[267]
    DIRECTION OUTPUT ;
    USE SIGNAL ;
    PORT
      LAYER M4 ;
        RECT  0 29.904 0.192 29.928 ;
    END
  END o[267]
  PIN o[268]
    DIRECTION OUTPUT ;
    USE SIGNAL ;
    PORT
      LAYER M4 ;
        RECT  0 30 0.192 30.024 ;
    END
  END o[268]
  PIN o[269]
    DIRECTION OUTPUT ;
    USE SIGNAL ;
    PORT
      LAYER M4 ;
        RECT  0 30.096 0.192 30.12 ;
    END
  END o[269]
  PIN o[26]
    DIRECTION OUTPUT ;
    USE SIGNAL ;
    PORT
      LAYER M4 ;
        RECT  0 4.896 0.192 4.92 ;
    END
  END o[26]
  PIN o[270]
    DIRECTION OUTPUT ;
    USE SIGNAL ;
    PORT
      LAYER M4 ;
        RECT  0 30.192 0.192 30.216 ;
    END
  END o[270]
  PIN o[271]
    DIRECTION OUTPUT ;
    USE SIGNAL ;
    PORT
      LAYER M4 ;
        RECT  0 30.288 0.192 30.312 ;
    END
  END o[271]
  PIN o[272]
    DIRECTION OUTPUT ;
    USE SIGNAL ;
    PORT
      LAYER M4 ;
        RECT  0 30.384 0.192 30.408 ;
    END
  END o[272]
  PIN o[273]
    DIRECTION OUTPUT ;
    USE SIGNAL ;
    PORT
      LAYER M4 ;
        RECT  0 30.48 0.192 30.504 ;
    END
  END o[273]
  PIN o[274]
    DIRECTION OUTPUT ;
    USE SIGNAL ;
    PORT
      LAYER M4 ;
        RECT  0 30.624 0.192 30.648 ;
    END
  END o[274]
  PIN o[275]
    DIRECTION OUTPUT ;
    USE SIGNAL ;
    PORT
      LAYER M4 ;
        RECT  0 30.72 0.192 30.744 ;
    END
  END o[275]
  PIN o[276]
    DIRECTION OUTPUT ;
    USE SIGNAL ;
    PORT
      LAYER M4 ;
        RECT  0 30.816 0.192 30.84 ;
    END
  END o[276]
  PIN o[277]
    DIRECTION OUTPUT ;
    USE SIGNAL ;
    PORT
      LAYER M4 ;
        RECT  0 30.912 0.192 30.936 ;
    END
  END o[277]
  PIN o[278]
    DIRECTION OUTPUT ;
    USE SIGNAL ;
    PORT
      LAYER M4 ;
        RECT  0 31.008 0.192 31.032 ;
    END
  END o[278]
  PIN o[279]
    DIRECTION OUTPUT ;
    USE SIGNAL ;
    PORT
      LAYER M4 ;
        RECT  0 31.104 0.192 31.128 ;
    END
  END o[279]
  PIN o[27]
    DIRECTION OUTPUT ;
    USE SIGNAL ;
    PORT
      LAYER M4 ;
        RECT  0 5.04 0.192 5.064 ;
    END
  END o[27]
  PIN o[280]
    DIRECTION OUTPUT ;
    USE SIGNAL ;
    PORT
      LAYER M4 ;
        RECT  0 31.248 0.192 31.272 ;
    END
  END o[280]
  PIN o[281]
    DIRECTION OUTPUT ;
    USE SIGNAL ;
    PORT
      LAYER M4 ;
        RECT  0 31.344 0.192 31.368 ;
    END
  END o[281]
  PIN o[282]
    DIRECTION OUTPUT ;
    USE SIGNAL ;
    PORT
      LAYER M4 ;
        RECT  0 31.44 0.192 31.464 ;
    END
  END o[282]
  PIN o[283]
    DIRECTION OUTPUT ;
    USE SIGNAL ;
    PORT
      LAYER M4 ;
        RECT  0 31.536 0.192 31.56 ;
    END
  END o[283]
  PIN o[284]
    DIRECTION OUTPUT ;
    USE SIGNAL ;
    PORT
      LAYER M4 ;
        RECT  0 31.632 0.192 31.656 ;
    END
  END o[284]
  PIN o[285]
    DIRECTION OUTPUT ;
    USE SIGNAL ;
    PORT
      LAYER M4 ;
        RECT  0 31.728 0.192 31.752 ;
    END
  END o[285]
  PIN o[286]
    DIRECTION OUTPUT ;
    USE SIGNAL ;
    PORT
      LAYER M4 ;
        RECT  0 31.872 0.192 31.896 ;
    END
  END o[286]
  PIN o[287]
    DIRECTION OUTPUT ;
    USE SIGNAL ;
    PORT
      LAYER M4 ;
        RECT  0 31.968 0.192 31.992 ;
    END
  END o[287]
  PIN o[288]
    DIRECTION OUTPUT ;
    USE SIGNAL ;
    PORT
      LAYER M4 ;
        RECT  0 32.064 0.192 32.088 ;
    END
  END o[288]
  PIN o[289]
    DIRECTION OUTPUT ;
    USE SIGNAL ;
    PORT
      LAYER M4 ;
        RECT  0 32.16 0.192 32.184 ;
    END
  END o[289]
  PIN o[28]
    DIRECTION OUTPUT ;
    USE SIGNAL ;
    PORT
      LAYER M4 ;
        RECT  0 5.136 0.192 5.16 ;
    END
  END o[28]
  PIN o[290]
    DIRECTION OUTPUT ;
    USE SIGNAL ;
    PORT
      LAYER M4 ;
        RECT  0 32.256 0.192 32.28 ;
    END
  END o[290]
  PIN o[291]
    DIRECTION OUTPUT ;
    USE SIGNAL ;
    PORT
      LAYER M4 ;
        RECT  0 32.352 0.192 32.376 ;
    END
  END o[291]
  PIN o[292]
    DIRECTION OUTPUT ;
    USE SIGNAL ;
    PORT
      LAYER M4 ;
        RECT  0 32.448 0.192 32.472 ;
    END
  END o[292]
  PIN o[293]
    DIRECTION OUTPUT ;
    USE SIGNAL ;
    PORT
      LAYER M4 ;
        RECT  0 32.592 0.192 32.616 ;
    END
  END o[293]
  PIN o[294]
    DIRECTION OUTPUT ;
    USE SIGNAL ;
    PORT
      LAYER M4 ;
        RECT  0 32.688 0.192 32.712 ;
    END
  END o[294]
  PIN o[295]
    DIRECTION OUTPUT ;
    USE SIGNAL ;
    PORT
      LAYER M4 ;
        RECT  0 32.784 0.192 32.808 ;
    END
  END o[295]
  PIN o[296]
    DIRECTION OUTPUT ;
    USE SIGNAL ;
    PORT
      LAYER M4 ;
        RECT  0 32.88 0.192 32.904 ;
    END
  END o[296]
  PIN o[297]
    DIRECTION OUTPUT ;
    USE SIGNAL ;
    PORT
      LAYER M4 ;
        RECT  0 32.976 0.192 33 ;
    END
  END o[297]
  PIN o[298]
    DIRECTION OUTPUT ;
    USE SIGNAL ;
    PORT
      LAYER M4 ;
        RECT  0 33.072 0.192 33.096 ;
    END
  END o[298]
  PIN o[299]
    DIRECTION OUTPUT ;
    USE SIGNAL ;
    PORT
      LAYER M4 ;
        RECT  0 33.216 0.192 33.24 ;
    END
  END o[299]
  PIN o[29]
    DIRECTION OUTPUT ;
    USE SIGNAL ;
    PORT
      LAYER M4 ;
        RECT  0 5.232 0.192 5.256 ;
    END
  END o[29]
  PIN o[2]
    DIRECTION OUTPUT ;
    USE SIGNAL ;
    PORT
      LAYER M4 ;
        RECT  0 2.448 0.192 2.472 ;
    END
  END o[2]
  PIN o[300]
    DIRECTION OUTPUT ;
    USE SIGNAL ;
    PORT
      LAYER M4 ;
        RECT  0 33.312 0.192 33.336 ;
    END
  END o[300]
  PIN o[301]
    DIRECTION OUTPUT ;
    USE SIGNAL ;
    PORT
      LAYER M4 ;
        RECT  0 33.408 0.192 33.432 ;
    END
  END o[301]
  PIN o[302]
    DIRECTION OUTPUT ;
    USE SIGNAL ;
    PORT
      LAYER M4 ;
        RECT  0 33.504 0.192 33.528 ;
    END
  END o[302]
  PIN o[303]
    DIRECTION OUTPUT ;
    USE SIGNAL ;
    PORT
      LAYER M4 ;
        RECT  0 33.6 0.192 33.624 ;
    END
  END o[303]
  PIN o[304]
    DIRECTION OUTPUT ;
    USE SIGNAL ;
    PORT
      LAYER M4 ;
        RECT  0 33.696 0.192 33.72 ;
    END
  END o[304]
  PIN o[305]
    DIRECTION OUTPUT ;
    USE SIGNAL ;
    PORT
      LAYER M4 ;
        RECT  0 33.84 0.192 33.864 ;
    END
  END o[305]
  PIN o[306]
    DIRECTION OUTPUT ;
    USE SIGNAL ;
    PORT
      LAYER M4 ;
        RECT  0 33.936 0.192 33.96 ;
    END
  END o[306]
  PIN o[307]
    DIRECTION OUTPUT ;
    USE SIGNAL ;
    PORT
      LAYER M4 ;
        RECT  0 34.032 0.192 34.056 ;
    END
  END o[307]
  PIN o[308]
    DIRECTION OUTPUT ;
    USE SIGNAL ;
    PORT
      LAYER M4 ;
        RECT  0 34.128 0.192 34.152 ;
    END
  END o[308]
  PIN o[309]
    DIRECTION OUTPUT ;
    USE SIGNAL ;
    PORT
      LAYER M4 ;
        RECT  0 34.224 0.192 34.248 ;
    END
  END o[309]
  PIN o[30]
    DIRECTION OUTPUT ;
    USE SIGNAL ;
    PORT
      LAYER M4 ;
        RECT  0 5.328 0.192 5.352 ;
    END
  END o[30]
  PIN o[310]
    DIRECTION OUTPUT ;
    USE SIGNAL ;
    PORT
      LAYER M4 ;
        RECT  0 34.32 0.192 34.344 ;
    END
  END o[310]
  PIN o[311]
    DIRECTION OUTPUT ;
    USE SIGNAL ;
    PORT
      LAYER M4 ;
        RECT  0 34.416 0.192 34.44 ;
    END
  END o[311]
  PIN o[312]
    DIRECTION OUTPUT ;
    USE SIGNAL ;
    PORT
      LAYER M4 ;
        RECT  0 34.56 0.192 34.584 ;
    END
  END o[312]
  PIN o[313]
    DIRECTION OUTPUT ;
    USE SIGNAL ;
    PORT
      LAYER M4 ;
        RECT  0 34.656 0.192 34.68 ;
    END
  END o[313]
  PIN o[314]
    DIRECTION OUTPUT ;
    USE SIGNAL ;
    PORT
      LAYER M4 ;
        RECT  0 34.752 0.192 34.776 ;
    END
  END o[314]
  PIN o[315]
    DIRECTION OUTPUT ;
    USE SIGNAL ;
    PORT
      LAYER M4 ;
        RECT  0 34.848 0.192 34.872 ;
    END
  END o[315]
  PIN o[316]
    DIRECTION OUTPUT ;
    USE SIGNAL ;
    PORT
      LAYER M4 ;
        RECT  0 34.944 0.192 34.968 ;
    END
  END o[316]
  PIN o[317]
    DIRECTION OUTPUT ;
    USE SIGNAL ;
    PORT
      LAYER M4 ;
        RECT  0 35.04 0.192 35.064 ;
    END
  END o[317]
  PIN o[318]
    DIRECTION OUTPUT ;
    USE SIGNAL ;
    PORT
      LAYER M4 ;
        RECT  0 35.184 0.192 35.208 ;
    END
  END o[318]
  PIN o[319]
    DIRECTION OUTPUT ;
    USE SIGNAL ;
    PORT
      LAYER M4 ;
        RECT  0 35.28 0.192 35.304 ;
    END
  END o[319]
  PIN o[31]
    DIRECTION OUTPUT ;
    USE SIGNAL ;
    PORT
      LAYER M4 ;
        RECT  0 5.424 0.192 5.448 ;
    END
  END o[31]
  PIN o[320]
    DIRECTION OUTPUT ;
    USE SIGNAL ;
    PORT
      LAYER M4 ;
        RECT  0 35.376 0.192 35.4 ;
    END
  END o[320]
  PIN o[321]
    DIRECTION OUTPUT ;
    USE SIGNAL ;
    PORT
      LAYER M4 ;
        RECT  0 35.472 0.192 35.496 ;
    END
  END o[321]
  PIN o[322]
    DIRECTION OUTPUT ;
    USE SIGNAL ;
    PORT
      LAYER M4 ;
        RECT  0 35.568 0.192 35.592 ;
    END
  END o[322]
  PIN o[323]
    DIRECTION OUTPUT ;
    USE SIGNAL ;
    PORT
      LAYER M4 ;
        RECT  0 35.664 0.192 35.688 ;
    END
  END o[323]
  PIN o[324]
    DIRECTION OUTPUT ;
    USE SIGNAL ;
    PORT
      LAYER M4 ;
        RECT  0 35.808 0.192 35.832 ;
    END
  END o[324]
  PIN o[325]
    DIRECTION OUTPUT ;
    USE SIGNAL ;
    PORT
      LAYER M4 ;
        RECT  0 35.904 0.192 35.928 ;
    END
  END o[325]
  PIN o[326]
    DIRECTION OUTPUT ;
    USE SIGNAL ;
    PORT
      LAYER M4 ;
        RECT  0 36 0.192 36.024 ;
    END
  END o[326]
  PIN o[327]
    DIRECTION OUTPUT ;
    USE SIGNAL ;
    PORT
      LAYER M4 ;
        RECT  0 36.096 0.192 36.12 ;
    END
  END o[327]
  PIN o[328]
    DIRECTION OUTPUT ;
    USE SIGNAL ;
    PORT
      LAYER M4 ;
        RECT  0 36.192 0.192 36.216 ;
    END
  END o[328]
  PIN o[329]
    DIRECTION OUTPUT ;
    USE SIGNAL ;
    PORT
      LAYER M4 ;
        RECT  0 36.288 0.192 36.312 ;
    END
  END o[329]
  PIN o[32]
    DIRECTION OUTPUT ;
    USE SIGNAL ;
    PORT
      LAYER M4 ;
        RECT  0 5.52 0.192 5.544 ;
    END
  END o[32]
  PIN o[330]
    DIRECTION OUTPUT ;
    USE SIGNAL ;
    PORT
      LAYER M4 ;
        RECT  0 36.384 0.192 36.408 ;
    END
  END o[330]
  PIN o[331]
    DIRECTION OUTPUT ;
    USE SIGNAL ;
    PORT
      LAYER M4 ;
        RECT  0 36.528 0.192 36.552 ;
    END
  END o[331]
  PIN o[332]
    DIRECTION OUTPUT ;
    USE SIGNAL ;
    PORT
      LAYER M4 ;
        RECT  0 36.624 0.192 36.648 ;
    END
  END o[332]
  PIN o[333]
    DIRECTION OUTPUT ;
    USE SIGNAL ;
    PORT
      LAYER M4 ;
        RECT  0 36.72 0.192 36.744 ;
    END
  END o[333]
  PIN o[334]
    DIRECTION OUTPUT ;
    USE SIGNAL ;
    PORT
      LAYER M4 ;
        RECT  0 36.816 0.192 36.84 ;
    END
  END o[334]
  PIN o[335]
    DIRECTION OUTPUT ;
    USE SIGNAL ;
    PORT
      LAYER M4 ;
        RECT  0 36.912 0.192 36.936 ;
    END
  END o[335]
  PIN o[336]
    DIRECTION OUTPUT ;
    USE SIGNAL ;
    PORT
      LAYER M4 ;
        RECT  0 37.008 0.192 37.032 ;
    END
  END o[336]
  PIN o[337]
    DIRECTION OUTPUT ;
    USE SIGNAL ;
    PORT
      LAYER M4 ;
        RECT  0 37.152 0.192 37.176 ;
    END
  END o[337]
  PIN o[338]
    DIRECTION OUTPUT ;
    USE SIGNAL ;
    PORT
      LAYER M4 ;
        RECT  0 37.248 0.192 37.272 ;
    END
  END o[338]
  PIN o[339]
    DIRECTION OUTPUT ;
    USE SIGNAL ;
    PORT
      LAYER M4 ;
        RECT  0 37.344 0.192 37.368 ;
    END
  END o[339]
  PIN o[33]
    DIRECTION OUTPUT ;
    USE SIGNAL ;
    PORT
      LAYER M4 ;
        RECT  0 5.664 0.192 5.688 ;
    END
  END o[33]
  PIN o[340]
    DIRECTION OUTPUT ;
    USE SIGNAL ;
    PORT
      LAYER M4 ;
        RECT  0 37.44 0.192 37.464 ;
    END
  END o[340]
  PIN o[341]
    DIRECTION OUTPUT ;
    USE SIGNAL ;
    PORT
      LAYER M4 ;
        RECT  0 37.536 0.192 37.56 ;
    END
  END o[341]
  PIN o[342]
    DIRECTION OUTPUT ;
    USE SIGNAL ;
    PORT
      LAYER M4 ;
        RECT  0 37.632 0.192 37.656 ;
    END
  END o[342]
  PIN o[343]
    DIRECTION OUTPUT ;
    USE SIGNAL ;
    PORT
      LAYER M4 ;
        RECT  0 37.776 0.192 37.8 ;
    END
  END o[343]
  PIN o[344]
    DIRECTION OUTPUT ;
    USE SIGNAL ;
    PORT
      LAYER M4 ;
        RECT  0 37.872 0.192 37.896 ;
    END
  END o[344]
  PIN o[345]
    DIRECTION OUTPUT ;
    USE SIGNAL ;
    PORT
      LAYER M4 ;
        RECT  0 37.968 0.192 37.992 ;
    END
  END o[345]
  PIN o[346]
    DIRECTION OUTPUT ;
    USE SIGNAL ;
    PORT
      LAYER M4 ;
        RECT  0 38.064 0.192 38.088 ;
    END
  END o[346]
  PIN o[347]
    DIRECTION OUTPUT ;
    USE SIGNAL ;
    PORT
      LAYER M4 ;
        RECT  0 38.16 0.192 38.184 ;
    END
  END o[347]
  PIN o[348]
    DIRECTION OUTPUT ;
    USE SIGNAL ;
    PORT
      LAYER M4 ;
        RECT  0 38.256 0.192 38.28 ;
    END
  END o[348]
  PIN o[349]
    DIRECTION OUTPUT ;
    USE SIGNAL ;
    PORT
      LAYER M4 ;
        RECT  0 38.352 0.192 38.376 ;
    END
  END o[349]
  PIN o[34]
    DIRECTION OUTPUT ;
    USE SIGNAL ;
    PORT
      LAYER M4 ;
        RECT  0 5.76 0.192 5.784 ;
    END
  END o[34]
  PIN o[350]
    DIRECTION OUTPUT ;
    USE SIGNAL ;
    PORT
      LAYER M4 ;
        RECT  0 38.496 0.192 38.52 ;
    END
  END o[350]
  PIN o[351]
    DIRECTION OUTPUT ;
    USE SIGNAL ;
    PORT
      LAYER M4 ;
        RECT  0 38.592 0.192 38.616 ;
    END
  END o[351]
  PIN o[352]
    DIRECTION OUTPUT ;
    USE SIGNAL ;
    PORT
      LAYER M4 ;
        RECT  0 38.688 0.192 38.712 ;
    END
  END o[352]
  PIN o[353]
    DIRECTION OUTPUT ;
    USE SIGNAL ;
    PORT
      LAYER M4 ;
        RECT  0 38.784 0.192 38.808 ;
    END
  END o[353]
  PIN o[354]
    DIRECTION OUTPUT ;
    USE SIGNAL ;
    PORT
      LAYER M4 ;
        RECT  0 38.88 0.192 38.904 ;
    END
  END o[354]
  PIN o[355]
    DIRECTION OUTPUT ;
    USE SIGNAL ;
    PORT
      LAYER M4 ;
        RECT  0 38.976 0.192 39 ;
    END
  END o[355]
  PIN o[356]
    DIRECTION OUTPUT ;
    USE SIGNAL ;
    PORT
      LAYER M4 ;
        RECT  0 39.12 0.192 39.144 ;
    END
  END o[356]
  PIN o[357]
    DIRECTION OUTPUT ;
    USE SIGNAL ;
    PORT
      LAYER M4 ;
        RECT  0 39.216 0.192 39.24 ;
    END
  END o[357]
  PIN o[358]
    DIRECTION OUTPUT ;
    USE SIGNAL ;
    PORT
      LAYER M4 ;
        RECT  0 39.312 0.192 39.336 ;
    END
  END o[358]
  PIN o[359]
    DIRECTION OUTPUT ;
    USE SIGNAL ;
    PORT
      LAYER M4 ;
        RECT  0 39.408 0.192 39.432 ;
    END
  END o[359]
  PIN o[35]
    DIRECTION OUTPUT ;
    USE SIGNAL ;
    PORT
      LAYER M4 ;
        RECT  0 5.856 0.192 5.88 ;
    END
  END o[35]
  PIN o[360]
    DIRECTION OUTPUT ;
    USE SIGNAL ;
    PORT
      LAYER M4 ;
        RECT  0 39.504 0.192 39.528 ;
    END
  END o[360]
  PIN o[361]
    DIRECTION OUTPUT ;
    USE SIGNAL ;
    PORT
      LAYER M4 ;
        RECT  0 39.6 0.192 39.624 ;
    END
  END o[361]
  PIN o[362]
    DIRECTION OUTPUT ;
    USE SIGNAL ;
    PORT
      LAYER M4 ;
        RECT  0 39.744 0.192 39.768 ;
    END
  END o[362]
  PIN o[363]
    DIRECTION OUTPUT ;
    USE SIGNAL ;
    PORT
      LAYER M4 ;
        RECT  0 39.84 0.192 39.864 ;
    END
  END o[363]
  PIN o[364]
    DIRECTION OUTPUT ;
    USE SIGNAL ;
    PORT
      LAYER M4 ;
        RECT  0 39.936 0.192 39.96 ;
    END
  END o[364]
  PIN o[365]
    DIRECTION OUTPUT ;
    USE SIGNAL ;
    PORT
      LAYER M4 ;
        RECT  0 40.032 0.192 40.056 ;
    END
  END o[365]
  PIN o[366]
    DIRECTION OUTPUT ;
    USE SIGNAL ;
    PORT
      LAYER M4 ;
        RECT  0 40.128 0.192 40.152 ;
    END
  END o[366]
  PIN o[367]
    DIRECTION OUTPUT ;
    USE SIGNAL ;
    PORT
      LAYER M4 ;
        RECT  0 40.224 0.192 40.248 ;
    END
  END o[367]
  PIN o[368]
    DIRECTION OUTPUT ;
    USE SIGNAL ;
    PORT
      LAYER M4 ;
        RECT  0 40.368 0.192 40.392 ;
    END
  END o[368]
  PIN o[369]
    DIRECTION OUTPUT ;
    USE SIGNAL ;
    PORT
      LAYER M4 ;
        RECT  0 40.464 0.192 40.488 ;
    END
  END o[369]
  PIN o[36]
    DIRECTION OUTPUT ;
    USE SIGNAL ;
    PORT
      LAYER M4 ;
        RECT  0 5.952 0.192 5.976 ;
    END
  END o[36]
  PIN o[370]
    DIRECTION OUTPUT ;
    USE SIGNAL ;
    PORT
      LAYER M4 ;
        RECT  0 40.56 0.192 40.584 ;
    END
  END o[370]
  PIN o[371]
    DIRECTION OUTPUT ;
    USE SIGNAL ;
    PORT
      LAYER M4 ;
        RECT  0 40.656 0.192 40.68 ;
    END
  END o[371]
  PIN o[372]
    DIRECTION OUTPUT ;
    USE SIGNAL ;
    PORT
      LAYER M4 ;
        RECT  0 40.752 0.192 40.776 ;
    END
  END o[372]
  PIN o[373]
    DIRECTION OUTPUT ;
    USE SIGNAL ;
    PORT
      LAYER M4 ;
        RECT  0 40.848 0.192 40.872 ;
    END
  END o[373]
  PIN o[374]
    DIRECTION OUTPUT ;
    USE SIGNAL ;
    PORT
      LAYER M4 ;
        RECT  0 40.944 0.192 40.968 ;
    END
  END o[374]
  PIN o[375]
    DIRECTION OUTPUT ;
    USE SIGNAL ;
    PORT
      LAYER M4 ;
        RECT  0 41.088 0.192 41.112 ;
    END
  END o[375]
  PIN o[376]
    DIRECTION OUTPUT ;
    USE SIGNAL ;
    PORT
      LAYER M4 ;
        RECT  0 41.184 0.192 41.208 ;
    END
  END o[376]
  PIN o[377]
    DIRECTION OUTPUT ;
    USE SIGNAL ;
    PORT
      LAYER M4 ;
        RECT  0 41.28 0.192 41.304 ;
    END
  END o[377]
  PIN o[378]
    DIRECTION OUTPUT ;
    USE SIGNAL ;
    PORT
      LAYER M4 ;
        RECT  0 41.376 0.192 41.4 ;
    END
  END o[378]
  PIN o[379]
    DIRECTION OUTPUT ;
    USE SIGNAL ;
    PORT
      LAYER M4 ;
        RECT  0 41.472 0.192 41.496 ;
    END
  END o[379]
  PIN o[37]
    DIRECTION OUTPUT ;
    USE SIGNAL ;
    PORT
      LAYER M4 ;
        RECT  0 6.048 0.192 6.072 ;
    END
  END o[37]
  PIN o[380]
    DIRECTION OUTPUT ;
    USE SIGNAL ;
    PORT
      LAYER M4 ;
        RECT  0 41.568 0.192 41.592 ;
    END
  END o[380]
  PIN o[381]
    DIRECTION OUTPUT ;
    USE SIGNAL ;
    PORT
      LAYER M4 ;
        RECT  0 41.712 0.192 41.736 ;
    END
  END o[381]
  PIN o[382]
    DIRECTION OUTPUT ;
    USE SIGNAL ;
    PORT
      LAYER M4 ;
        RECT  0 41.808 0.192 41.832 ;
    END
  END o[382]
  PIN o[383]
    DIRECTION OUTPUT ;
    USE SIGNAL ;
    PORT
      LAYER M4 ;
        RECT  0 41.904 0.192 41.928 ;
    END
  END o[383]
  PIN o[384]
    DIRECTION OUTPUT ;
    USE SIGNAL ;
    PORT
      LAYER M4 ;
        RECT  0 42 0.192 42.024 ;
    END
  END o[384]
  PIN o[385]
    DIRECTION OUTPUT ;
    USE SIGNAL ;
    PORT
      LAYER M4 ;
        RECT  0 42.096 0.192 42.12 ;
    END
  END o[385]
  PIN o[386]
    DIRECTION OUTPUT ;
    USE SIGNAL ;
    PORT
      LAYER M4 ;
        RECT  0 42.192 0.192 42.216 ;
    END
  END o[386]
  PIN o[387]
    DIRECTION OUTPUT ;
    USE SIGNAL ;
    PORT
      LAYER M4 ;
        RECT  0 42.336 0.192 42.36 ;
    END
  END o[387]
  PIN o[388]
    DIRECTION OUTPUT ;
    USE SIGNAL ;
    PORT
      LAYER M4 ;
        RECT  0 42.432 0.192 42.456 ;
    END
  END o[388]
  PIN o[389]
    DIRECTION OUTPUT ;
    USE SIGNAL ;
    PORT
      LAYER M4 ;
        RECT  0 42.528 0.192 42.552 ;
    END
  END o[389]
  PIN o[38]
    DIRECTION OUTPUT ;
    USE SIGNAL ;
    PORT
      LAYER M4 ;
        RECT  0 6.144 0.192 6.168 ;
    END
  END o[38]
  PIN o[390]
    DIRECTION OUTPUT ;
    USE SIGNAL ;
    PORT
      LAYER M4 ;
        RECT  0 42.624 0.192 42.648 ;
    END
  END o[390]
  PIN o[391]
    DIRECTION OUTPUT ;
    USE SIGNAL ;
    PORT
      LAYER M4 ;
        RECT  0 42.72 0.192 42.744 ;
    END
  END o[391]
  PIN o[392]
    DIRECTION OUTPUT ;
    USE SIGNAL ;
    PORT
      LAYER M4 ;
        RECT  0 42.816 0.192 42.84 ;
    END
  END o[392]
  PIN o[393]
    DIRECTION OUTPUT ;
    USE SIGNAL ;
    PORT
      LAYER M4 ;
        RECT  0 42.912 0.192 42.936 ;
    END
  END o[393]
  PIN o[394]
    DIRECTION OUTPUT ;
    USE SIGNAL ;
    PORT
      LAYER M4 ;
        RECT  0 43.056 0.192 43.08 ;
    END
  END o[394]
  PIN o[395]
    DIRECTION OUTPUT ;
    USE SIGNAL ;
    PORT
      LAYER M4 ;
        RECT  0 43.152 0.192 43.176 ;
    END
  END o[395]
  PIN o[396]
    DIRECTION OUTPUT ;
    USE SIGNAL ;
    PORT
      LAYER M4 ;
        RECT  0 43.248 0.192 43.272 ;
    END
  END o[396]
  PIN o[397]
    DIRECTION OUTPUT ;
    USE SIGNAL ;
    PORT
      LAYER M4 ;
        RECT  0 43.344 0.192 43.368 ;
    END
  END o[397]
  PIN o[398]
    DIRECTION OUTPUT ;
    USE SIGNAL ;
    PORT
      LAYER M4 ;
        RECT  0 43.44 0.192 43.464 ;
    END
  END o[398]
  PIN o[399]
    DIRECTION OUTPUT ;
    USE SIGNAL ;
    PORT
      LAYER M4 ;
        RECT  0 43.536 0.192 43.56 ;
    END
  END o[399]
  PIN o[39]
    DIRECTION OUTPUT ;
    USE SIGNAL ;
    PORT
      LAYER M4 ;
        RECT  0 6.24 0.192 6.264 ;
    END
  END o[39]
  PIN o[3]
    DIRECTION OUTPUT ;
    USE SIGNAL ;
    PORT
      LAYER M4 ;
        RECT  0 2.544 0.192 2.568 ;
    END
  END o[3]
  PIN o[400]
    DIRECTION OUTPUT ;
    USE SIGNAL ;
    PORT
      LAYER M4 ;
        RECT  0 43.68 0.192 43.704 ;
    END
  END o[400]
  PIN o[401]
    DIRECTION OUTPUT ;
    USE SIGNAL ;
    PORT
      LAYER M4 ;
        RECT  0 43.776 0.192 43.8 ;
    END
  END o[401]
  PIN o[402]
    DIRECTION OUTPUT ;
    USE SIGNAL ;
    PORT
      LAYER M4 ;
        RECT  0 43.872 0.192 43.896 ;
    END
  END o[402]
  PIN o[403]
    DIRECTION OUTPUT ;
    USE SIGNAL ;
    PORT
      LAYER M4 ;
        RECT  0 43.968 0.192 43.992 ;
    END
  END o[403]
  PIN o[404]
    DIRECTION OUTPUT ;
    USE SIGNAL ;
    PORT
      LAYER M4 ;
        RECT  0 44.064 0.192 44.088 ;
    END
  END o[404]
  PIN o[405]
    DIRECTION OUTPUT ;
    USE SIGNAL ;
    PORT
      LAYER M4 ;
        RECT  0 44.16 0.192 44.184 ;
    END
  END o[405]
  PIN o[406]
    DIRECTION OUTPUT ;
    USE SIGNAL ;
    PORT
      LAYER M4 ;
        RECT  0 44.304 0.192 44.328 ;
    END
  END o[406]
  PIN o[407]
    DIRECTION OUTPUT ;
    USE SIGNAL ;
    PORT
      LAYER M4 ;
        RECT  0 44.4 0.192 44.424 ;
    END
  END o[407]
  PIN o[408]
    DIRECTION OUTPUT ;
    USE SIGNAL ;
    PORT
      LAYER M4 ;
        RECT  0 44.496 0.192 44.52 ;
    END
  END o[408]
  PIN o[409]
    DIRECTION OUTPUT ;
    USE SIGNAL ;
    PORT
      LAYER M4 ;
        RECT  0 44.592 0.192 44.616 ;
    END
  END o[409]
  PIN o[40]
    DIRECTION OUTPUT ;
    USE SIGNAL ;
    PORT
      LAYER M4 ;
        RECT  0 6.384 0.192 6.408 ;
    END
  END o[40]
  PIN o[410]
    DIRECTION OUTPUT ;
    USE SIGNAL ;
    PORT
      LAYER M4 ;
        RECT  0 44.688 0.192 44.712 ;
    END
  END o[410]
  PIN o[411]
    DIRECTION OUTPUT ;
    USE SIGNAL ;
    PORT
      LAYER M4 ;
        RECT  0 44.784 0.192 44.808 ;
    END
  END o[411]
  PIN o[412]
    DIRECTION OUTPUT ;
    USE SIGNAL ;
    PORT
      LAYER M4 ;
        RECT  0 44.88 0.192 44.904 ;
    END
  END o[412]
  PIN o[413]
    DIRECTION OUTPUT ;
    USE SIGNAL ;
    PORT
      LAYER M4 ;
        RECT  0 45.024 0.192 45.048 ;
    END
  END o[413]
  PIN o[414]
    DIRECTION OUTPUT ;
    USE SIGNAL ;
    PORT
      LAYER M4 ;
        RECT  0 45.12 0.192 45.144 ;
    END
  END o[414]
  PIN o[415]
    DIRECTION OUTPUT ;
    USE SIGNAL ;
    PORT
      LAYER M4 ;
        RECT  0 45.216 0.192 45.24 ;
    END
  END o[415]
  PIN o[416]
    DIRECTION OUTPUT ;
    USE SIGNAL ;
    PORT
      LAYER M4 ;
        RECT  0 45.312 0.192 45.336 ;
    END
  END o[416]
  PIN o[417]
    DIRECTION OUTPUT ;
    USE SIGNAL ;
    PORT
      LAYER M4 ;
        RECT  0 45.408 0.192 45.432 ;
    END
  END o[417]
  PIN o[418]
    DIRECTION OUTPUT ;
    USE SIGNAL ;
    PORT
      LAYER M4 ;
        RECT  0 45.504 0.192 45.528 ;
    END
  END o[418]
  PIN o[419]
    DIRECTION OUTPUT ;
    USE SIGNAL ;
    PORT
      LAYER M4 ;
        RECT  0 45.648 0.192 45.672 ;
    END
  END o[419]
  PIN o[41]
    DIRECTION OUTPUT ;
    USE SIGNAL ;
    PORT
      LAYER M4 ;
        RECT  0 6.48 0.192 6.504 ;
    END
  END o[41]
  PIN o[420]
    DIRECTION OUTPUT ;
    USE SIGNAL ;
    PORT
      LAYER M4 ;
        RECT  0 45.744 0.192 45.768 ;
    END
  END o[420]
  PIN o[421]
    DIRECTION OUTPUT ;
    USE SIGNAL ;
    PORT
      LAYER M4 ;
        RECT  0 45.84 0.192 45.864 ;
    END
  END o[421]
  PIN o[422]
    DIRECTION OUTPUT ;
    USE SIGNAL ;
    PORT
      LAYER M4 ;
        RECT  0 45.936 0.192 45.96 ;
    END
  END o[422]
  PIN o[423]
    DIRECTION OUTPUT ;
    USE SIGNAL ;
    PORT
      LAYER M4 ;
        RECT  0 46.032 0.192 46.056 ;
    END
  END o[423]
  PIN o[424]
    DIRECTION OUTPUT ;
    USE SIGNAL ;
    PORT
      LAYER M4 ;
        RECT  0 46.128 0.192 46.152 ;
    END
  END o[424]
  PIN o[425]
    DIRECTION OUTPUT ;
    USE SIGNAL ;
    PORT
      LAYER M4 ;
        RECT  0 46.272 0.192 46.296 ;
    END
  END o[425]
  PIN o[426]
    DIRECTION OUTPUT ;
    USE SIGNAL ;
    PORT
      LAYER M4 ;
        RECT  0 46.368 0.192 46.392 ;
    END
  END o[426]
  PIN o[427]
    DIRECTION OUTPUT ;
    USE SIGNAL ;
    PORT
      LAYER M4 ;
        RECT  0 46.464 0.192 46.488 ;
    END
  END o[427]
  PIN o[428]
    DIRECTION OUTPUT ;
    USE SIGNAL ;
    PORT
      LAYER M4 ;
        RECT  0 46.56 0.192 46.584 ;
    END
  END o[428]
  PIN o[429]
    DIRECTION OUTPUT ;
    USE SIGNAL ;
    PORT
      LAYER M4 ;
        RECT  0 46.656 0.192 46.68 ;
    END
  END o[429]
  PIN o[42]
    DIRECTION OUTPUT ;
    USE SIGNAL ;
    PORT
      LAYER M4 ;
        RECT  0 6.576 0.192 6.6 ;
    END
  END o[42]
  PIN o[430]
    DIRECTION OUTPUT ;
    USE SIGNAL ;
    PORT
      LAYER M4 ;
        RECT  0 46.752 0.192 46.776 ;
    END
  END o[430]
  PIN o[431]
    DIRECTION OUTPUT ;
    USE SIGNAL ;
    PORT
      LAYER M4 ;
        RECT  0 46.848 0.192 46.872 ;
    END
  END o[431]
  PIN o[432]
    DIRECTION OUTPUT ;
    USE SIGNAL ;
    PORT
      LAYER M4 ;
        RECT  0 46.992 0.192 47.016 ;
    END
  END o[432]
  PIN o[433]
    DIRECTION OUTPUT ;
    USE SIGNAL ;
    PORT
      LAYER M4 ;
        RECT  0 47.088 0.192 47.112 ;
    END
  END o[433]
  PIN o[434]
    DIRECTION OUTPUT ;
    USE SIGNAL ;
    PORT
      LAYER M4 ;
        RECT  0 47.184 0.192 47.208 ;
    END
  END o[434]
  PIN o[435]
    DIRECTION OUTPUT ;
    USE SIGNAL ;
    PORT
      LAYER M4 ;
        RECT  0 47.28 0.192 47.304 ;
    END
  END o[435]
  PIN o[436]
    DIRECTION OUTPUT ;
    USE SIGNAL ;
    PORT
      LAYER M4 ;
        RECT  0 47.376 0.192 47.4 ;
    END
  END o[436]
  PIN o[437]
    DIRECTION OUTPUT ;
    USE SIGNAL ;
    PORT
      LAYER M4 ;
        RECT  0 47.472 0.192 47.496 ;
    END
  END o[437]
  PIN o[438]
    DIRECTION OUTPUT ;
    USE SIGNAL ;
    PORT
      LAYER M4 ;
        RECT  0 47.616 0.192 47.64 ;
    END
  END o[438]
  PIN o[439]
    DIRECTION OUTPUT ;
    USE SIGNAL ;
    PORT
      LAYER M4 ;
        RECT  0 47.712 0.192 47.736 ;
    END
  END o[439]
  PIN o[43]
    DIRECTION OUTPUT ;
    USE SIGNAL ;
    PORT
      LAYER M4 ;
        RECT  0 6.672 0.192 6.696 ;
    END
  END o[43]
  PIN o[440]
    DIRECTION OUTPUT ;
    USE SIGNAL ;
    PORT
      LAYER M4 ;
        RECT  0 47.808 0.192 47.832 ;
    END
  END o[440]
  PIN o[441]
    DIRECTION OUTPUT ;
    USE SIGNAL ;
    PORT
      LAYER M4 ;
        RECT  0 47.904 0.192 47.928 ;
    END
  END o[441]
  PIN o[442]
    DIRECTION OUTPUT ;
    USE SIGNAL ;
    PORT
      LAYER M4 ;
        RECT  0 48 0.192 48.024 ;
    END
  END o[442]
  PIN o[443]
    DIRECTION OUTPUT ;
    USE SIGNAL ;
    PORT
      LAYER M4 ;
        RECT  0 48.096 0.192 48.12 ;
    END
  END o[443]
  PIN o[444]
    DIRECTION OUTPUT ;
    USE SIGNAL ;
    PORT
      LAYER M4 ;
        RECT  0 48.24 0.192 48.264 ;
    END
  END o[444]
  PIN o[445]
    DIRECTION OUTPUT ;
    USE SIGNAL ;
    PORT
      LAYER M4 ;
        RECT  0 48.336 0.192 48.36 ;
    END
  END o[445]
  PIN o[446]
    DIRECTION OUTPUT ;
    USE SIGNAL ;
    PORT
      LAYER M4 ;
        RECT  0 48.432 0.192 48.456 ;
    END
  END o[446]
  PIN o[447]
    DIRECTION OUTPUT ;
    USE SIGNAL ;
    PORT
      LAYER M4 ;
        RECT  0 48.528 0.192 48.552 ;
    END
  END o[447]
  PIN o[448]
    DIRECTION OUTPUT ;
    USE SIGNAL ;
    PORT
      LAYER M4 ;
        RECT  0 48.624 0.192 48.648 ;
    END
  END o[448]
  PIN o[449]
    DIRECTION OUTPUT ;
    USE SIGNAL ;
    PORT
      LAYER M4 ;
        RECT  0 48.72 0.192 48.744 ;
    END
  END o[449]
  PIN o[44]
    DIRECTION OUTPUT ;
    USE SIGNAL ;
    PORT
      LAYER M4 ;
        RECT  0 6.768 0.192 6.792 ;
    END
  END o[44]
  PIN o[450]
    DIRECTION OUTPUT ;
    USE SIGNAL ;
    PORT
      LAYER M4 ;
        RECT  0 48.816 0.192 48.84 ;
    END
  END o[450]
  PIN o[451]
    DIRECTION OUTPUT ;
    USE SIGNAL ;
    PORT
      LAYER M4 ;
        RECT  0 48.96 0.192 48.984 ;
    END
  END o[451]
  PIN o[452]
    DIRECTION OUTPUT ;
    USE SIGNAL ;
    PORT
      LAYER M4 ;
        RECT  0 49.056 0.192 49.08 ;
    END
  END o[452]
  PIN o[453]
    DIRECTION OUTPUT ;
    USE SIGNAL ;
    PORT
      LAYER M4 ;
        RECT  0 49.152 0.192 49.176 ;
    END
  END o[453]
  PIN o[454]
    DIRECTION OUTPUT ;
    USE SIGNAL ;
    PORT
      LAYER M4 ;
        RECT  0 49.248 0.192 49.272 ;
    END
  END o[454]
  PIN o[455]
    DIRECTION OUTPUT ;
    USE SIGNAL ;
    PORT
      LAYER M4 ;
        RECT  0 49.344 0.192 49.368 ;
    END
  END o[455]
  PIN o[456]
    DIRECTION OUTPUT ;
    USE SIGNAL ;
    PORT
      LAYER M4 ;
        RECT  0 49.44 0.192 49.464 ;
    END
  END o[456]
  PIN o[457]
    DIRECTION OUTPUT ;
    USE SIGNAL ;
    PORT
      LAYER M4 ;
        RECT  0 49.584 0.192 49.608 ;
    END
  END o[457]
  PIN o[458]
    DIRECTION OUTPUT ;
    USE SIGNAL ;
    PORT
      LAYER M4 ;
        RECT  0 49.68 0.192 49.704 ;
    END
  END o[458]
  PIN o[459]
    DIRECTION OUTPUT ;
    USE SIGNAL ;
    PORT
      LAYER M4 ;
        RECT  0 49.776 0.192 49.8 ;
    END
  END o[459]
  PIN o[45]
    DIRECTION OUTPUT ;
    USE SIGNAL ;
    PORT
      LAYER M4 ;
        RECT  0 6.864 0.192 6.888 ;
    END
  END o[45]
  PIN o[460]
    DIRECTION OUTPUT ;
    USE SIGNAL ;
    PORT
      LAYER M4 ;
        RECT  0 49.872 0.192 49.896 ;
    END
  END o[460]
  PIN o[461]
    DIRECTION OUTPUT ;
    USE SIGNAL ;
    PORT
      LAYER M4 ;
        RECT  0 49.968 0.192 49.992 ;
    END
  END o[461]
  PIN o[462]
    DIRECTION OUTPUT ;
    USE SIGNAL ;
    PORT
      LAYER M4 ;
        RECT  0 50.064 0.192 50.088 ;
    END
  END o[462]
  PIN o[463]
    DIRECTION OUTPUT ;
    USE SIGNAL ;
    PORT
      LAYER M4 ;
        RECT  0 50.208 0.192 50.232 ;
    END
  END o[463]
  PIN o[464]
    DIRECTION OUTPUT ;
    USE SIGNAL ;
    PORT
      LAYER M4 ;
        RECT  0 50.304 0.192 50.328 ;
    END
  END o[464]
  PIN o[465]
    DIRECTION OUTPUT ;
    USE SIGNAL ;
    PORT
      LAYER M4 ;
        RECT  0 50.4 0.192 50.424 ;
    END
  END o[465]
  PIN o[466]
    DIRECTION OUTPUT ;
    USE SIGNAL ;
    PORT
      LAYER M4 ;
        RECT  0 50.496 0.192 50.52 ;
    END
  END o[466]
  PIN o[467]
    DIRECTION OUTPUT ;
    USE SIGNAL ;
    PORT
      LAYER M4 ;
        RECT  0 50.592 0.192 50.616 ;
    END
  END o[467]
  PIN o[468]
    DIRECTION OUTPUT ;
    USE SIGNAL ;
    PORT
      LAYER M4 ;
        RECT  0 50.688 0.192 50.712 ;
    END
  END o[468]
  PIN o[469]
    DIRECTION OUTPUT ;
    USE SIGNAL ;
    PORT
      LAYER M4 ;
        RECT  0 50.784 0.192 50.808 ;
    END
  END o[469]
  PIN o[46]
    DIRECTION OUTPUT ;
    USE SIGNAL ;
    PORT
      LAYER M4 ;
        RECT  0 7.008 0.192 7.032 ;
    END
  END o[46]
  PIN o[470]
    DIRECTION OUTPUT ;
    USE SIGNAL ;
    PORT
      LAYER M4 ;
        RECT  0 50.928 0.192 50.952 ;
    END
  END o[470]
  PIN o[471]
    DIRECTION OUTPUT ;
    USE SIGNAL ;
    PORT
      LAYER M4 ;
        RECT  0 51.024 0.192 51.048 ;
    END
  END o[471]
  PIN o[472]
    DIRECTION OUTPUT ;
    USE SIGNAL ;
    PORT
      LAYER M4 ;
        RECT  0 51.12 0.192 51.144 ;
    END
  END o[472]
  PIN o[473]
    DIRECTION OUTPUT ;
    USE SIGNAL ;
    PORT
      LAYER M4 ;
        RECT  0 51.216 0.192 51.24 ;
    END
  END o[473]
  PIN o[474]
    DIRECTION OUTPUT ;
    USE SIGNAL ;
    PORT
      LAYER M4 ;
        RECT  0 51.312 0.192 51.336 ;
    END
  END o[474]
  PIN o[475]
    DIRECTION OUTPUT ;
    USE SIGNAL ;
    PORT
      LAYER M4 ;
        RECT  0 51.408 0.192 51.432 ;
    END
  END o[475]
  PIN o[476]
    DIRECTION OUTPUT ;
    USE SIGNAL ;
    PORT
      LAYER M4 ;
        RECT  0 51.552 0.192 51.576 ;
    END
  END o[476]
  PIN o[477]
    DIRECTION OUTPUT ;
    USE SIGNAL ;
    PORT
      LAYER M4 ;
        RECT  0 51.648 0.192 51.672 ;
    END
  END o[477]
  PIN o[478]
    DIRECTION OUTPUT ;
    USE SIGNAL ;
    PORT
      LAYER M4 ;
        RECT  0 51.744 0.192 51.768 ;
    END
  END o[478]
  PIN o[479]
    DIRECTION OUTPUT ;
    USE SIGNAL ;
    PORT
      LAYER M4 ;
        RECT  0 51.84 0.192 51.864 ;
    END
  END o[479]
  PIN o[47]
    DIRECTION OUTPUT ;
    USE SIGNAL ;
    PORT
      LAYER M4 ;
        RECT  0 7.104 0.192 7.128 ;
    END
  END o[47]
  PIN o[480]
    DIRECTION OUTPUT ;
    USE SIGNAL ;
    PORT
      LAYER M4 ;
        RECT  0 51.936 0.192 51.96 ;
    END
  END o[480]
  PIN o[481]
    DIRECTION OUTPUT ;
    USE SIGNAL ;
    PORT
      LAYER M4 ;
        RECT  0 52.032 0.192 52.056 ;
    END
  END o[481]
  PIN o[482]
    DIRECTION OUTPUT ;
    USE SIGNAL ;
    PORT
      LAYER M4 ;
        RECT  0 52.176 0.192 52.2 ;
    END
  END o[482]
  PIN o[483]
    DIRECTION OUTPUT ;
    USE SIGNAL ;
    PORT
      LAYER M4 ;
        RECT  0 52.272 0.192 52.296 ;
    END
  END o[483]
  PIN o[484]
    DIRECTION OUTPUT ;
    USE SIGNAL ;
    PORT
      LAYER M4 ;
        RECT  0 52.368 0.192 52.392 ;
    END
  END o[484]
  PIN o[485]
    DIRECTION OUTPUT ;
    USE SIGNAL ;
    PORT
      LAYER M4 ;
        RECT  0 52.464 0.192 52.488 ;
    END
  END o[485]
  PIN o[486]
    DIRECTION OUTPUT ;
    USE SIGNAL ;
    PORT
      LAYER M4 ;
        RECT  0 52.56 0.192 52.584 ;
    END
  END o[486]
  PIN o[487]
    DIRECTION OUTPUT ;
    USE SIGNAL ;
    PORT
      LAYER M4 ;
        RECT  0 52.656 0.192 52.68 ;
    END
  END o[487]
  PIN o[488]
    DIRECTION OUTPUT ;
    USE SIGNAL ;
    PORT
      LAYER M4 ;
        RECT  0 52.752 0.192 52.776 ;
    END
  END o[488]
  PIN o[489]
    DIRECTION OUTPUT ;
    USE SIGNAL ;
    PORT
      LAYER M4 ;
        RECT  0 52.896 0.192 52.92 ;
    END
  END o[489]
  PIN o[48]
    DIRECTION OUTPUT ;
    USE SIGNAL ;
    PORT
      LAYER M4 ;
        RECT  0 7.2 0.192 7.224 ;
    END
  END o[48]
  PIN o[490]
    DIRECTION OUTPUT ;
    USE SIGNAL ;
    PORT
      LAYER M4 ;
        RECT  0 52.992 0.192 53.016 ;
    END
  END o[490]
  PIN o[491]
    DIRECTION OUTPUT ;
    USE SIGNAL ;
    PORT
      LAYER M4 ;
        RECT  0 53.088 0.192 53.112 ;
    END
  END o[491]
  PIN o[492]
    DIRECTION OUTPUT ;
    USE SIGNAL ;
    PORT
      LAYER M4 ;
        RECT  0 53.184 0.192 53.208 ;
    END
  END o[492]
  PIN o[493]
    DIRECTION OUTPUT ;
    USE SIGNAL ;
    PORT
      LAYER M4 ;
        RECT  0 53.28 0.192 53.304 ;
    END
  END o[493]
  PIN o[494]
    DIRECTION OUTPUT ;
    USE SIGNAL ;
    PORT
      LAYER M4 ;
        RECT  0 53.376 0.192 53.4 ;
    END
  END o[494]
  PIN o[495]
    DIRECTION OUTPUT ;
    USE SIGNAL ;
    PORT
      LAYER M4 ;
        RECT  0 53.52 0.192 53.544 ;
    END
  END o[495]
  PIN o[496]
    DIRECTION OUTPUT ;
    USE SIGNAL ;
    PORT
      LAYER M4 ;
        RECT  0 53.616 0.192 53.64 ;
    END
  END o[496]
  PIN o[497]
    DIRECTION OUTPUT ;
    USE SIGNAL ;
    PORT
      LAYER M4 ;
        RECT  0 53.712 0.192 53.736 ;
    END
  END o[497]
  PIN o[498]
    DIRECTION OUTPUT ;
    USE SIGNAL ;
    PORT
      LAYER M4 ;
        RECT  0 53.808 0.192 53.832 ;
    END
  END o[498]
  PIN o[499]
    DIRECTION OUTPUT ;
    USE SIGNAL ;
    PORT
      LAYER M4 ;
        RECT  0 53.904 0.192 53.928 ;
    END
  END o[499]
  PIN o[49]
    DIRECTION OUTPUT ;
    USE SIGNAL ;
    PORT
      LAYER M4 ;
        RECT  0 7.296 0.192 7.32 ;
    END
  END o[49]
  PIN o[4]
    DIRECTION OUTPUT ;
    USE SIGNAL ;
    PORT
      LAYER M4 ;
        RECT  0 2.64 0.192 2.664 ;
    END
  END o[4]
  PIN o[500]
    DIRECTION OUTPUT ;
    USE SIGNAL ;
    PORT
      LAYER M4 ;
        RECT  0 54 0.192 54.024 ;
    END
  END o[500]
  PIN o[501]
    DIRECTION OUTPUT ;
    USE SIGNAL ;
    PORT
      LAYER M4 ;
        RECT  0 54.144 0.192 54.168 ;
    END
  END o[501]
  PIN o[502]
    DIRECTION OUTPUT ;
    USE SIGNAL ;
    PORT
      LAYER M4 ;
        RECT  0 54.24 0.192 54.264 ;
    END
  END o[502]
  PIN o[503]
    DIRECTION OUTPUT ;
    USE SIGNAL ;
    PORT
      LAYER M4 ;
        RECT  0 54.336 0.192 54.36 ;
    END
  END o[503]
  PIN o[504]
    DIRECTION OUTPUT ;
    USE SIGNAL ;
    PORT
      LAYER M4 ;
        RECT  0 54.432 0.192 54.456 ;
    END
  END o[504]
  PIN o[505]
    DIRECTION OUTPUT ;
    USE SIGNAL ;
    PORT
      LAYER M4 ;
        RECT  0 54.528 0.192 54.552 ;
    END
  END o[505]
  PIN o[506]
    DIRECTION OUTPUT ;
    USE SIGNAL ;
    PORT
      LAYER M4 ;
        RECT  0 54.624 0.192 54.648 ;
    END
  END o[506]
  PIN o[507]
    DIRECTION OUTPUT ;
    USE SIGNAL ;
    PORT
      LAYER M4 ;
        RECT  0 54.72 0.192 54.744 ;
    END
  END o[507]
  PIN o[508]
    DIRECTION OUTPUT ;
    USE SIGNAL ;
    PORT
      LAYER M4 ;
        RECT  0 54.864 0.192 54.888 ;
    END
  END o[508]
  PIN o[509]
    DIRECTION OUTPUT ;
    USE SIGNAL ;
    PORT
      LAYER M4 ;
        RECT  0 54.96 0.192 54.984 ;
    END
  END o[509]
  PIN o[50]
    DIRECTION OUTPUT ;
    USE SIGNAL ;
    PORT
      LAYER M4 ;
        RECT  0 7.392 0.192 7.416 ;
    END
  END o[50]
  PIN o[510]
    DIRECTION OUTPUT ;
    USE SIGNAL ;
    PORT
      LAYER M4 ;
        RECT  0 55.056 0.192 55.08 ;
    END
  END o[510]
  PIN o[511]
    DIRECTION OUTPUT ;
    USE SIGNAL ;
    PORT
      LAYER M4 ;
        RECT  0 55.152 0.192 55.176 ;
    END
  END o[511]
  PIN o[512]
    DIRECTION OUTPUT ;
    USE SIGNAL ;
    PORT
      LAYER M4 ;
        RECT  0 55.248 0.192 55.272 ;
    END
  END o[512]
  PIN o[513]
    DIRECTION OUTPUT ;
    USE SIGNAL ;
    PORT
      LAYER M4 ;
        RECT  0 55.344 0.192 55.368 ;
    END
  END o[513]
  PIN o[514]
    DIRECTION OUTPUT ;
    USE SIGNAL ;
    PORT
      LAYER M4 ;
        RECT  0 55.488 0.192 55.512 ;
    END
  END o[514]
  PIN o[515]
    DIRECTION OUTPUT ;
    USE SIGNAL ;
    PORT
      LAYER M4 ;
        RECT  0 55.584 0.192 55.608 ;
    END
  END o[515]
  PIN o[516]
    DIRECTION OUTPUT ;
    USE SIGNAL ;
    PORT
      LAYER M4 ;
        RECT  0 55.68 0.192 55.704 ;
    END
  END o[516]
  PIN o[517]
    DIRECTION OUTPUT ;
    USE SIGNAL ;
    PORT
      LAYER M4 ;
        RECT  0 55.776 0.192 55.8 ;
    END
  END o[517]
  PIN o[518]
    DIRECTION OUTPUT ;
    USE SIGNAL ;
    PORT
      LAYER M4 ;
        RECT  0 55.872 0.192 55.896 ;
    END
  END o[518]
  PIN o[519]
    DIRECTION OUTPUT ;
    USE SIGNAL ;
    PORT
      LAYER M4 ;
        RECT  0 55.968 0.192 55.992 ;
    END
  END o[519]
  PIN o[51]
    DIRECTION OUTPUT ;
    USE SIGNAL ;
    PORT
      LAYER M4 ;
        RECT  0 7.488 0.192 7.512 ;
    END
  END o[51]
  PIN o[520]
    DIRECTION OUTPUT ;
    USE SIGNAL ;
    PORT
      LAYER M4 ;
        RECT  0 56.112 0.192 56.136 ;
    END
  END o[520]
  PIN o[521]
    DIRECTION OUTPUT ;
    USE SIGNAL ;
    PORT
      LAYER M4 ;
        RECT  0 56.208 0.192 56.232 ;
    END
  END o[521]
  PIN o[522]
    DIRECTION OUTPUT ;
    USE SIGNAL ;
    PORT
      LAYER M4 ;
        RECT  0 56.304 0.192 56.328 ;
    END
  END o[522]
  PIN o[523]
    DIRECTION OUTPUT ;
    USE SIGNAL ;
    PORT
      LAYER M4 ;
        RECT  0 56.4 0.192 56.424 ;
    END
  END o[523]
  PIN o[524]
    DIRECTION OUTPUT ;
    USE SIGNAL ;
    PORT
      LAYER M4 ;
        RECT  0 56.496 0.192 56.52 ;
    END
  END o[524]
  PIN o[525]
    DIRECTION OUTPUT ;
    USE SIGNAL ;
    PORT
      LAYER M4 ;
        RECT  0 56.592 0.192 56.616 ;
    END
  END o[525]
  PIN o[526]
    DIRECTION OUTPUT ;
    USE SIGNAL ;
    PORT
      LAYER M4 ;
        RECT  0 56.688 0.192 56.712 ;
    END
  END o[526]
  PIN o[527]
    DIRECTION OUTPUT ;
    USE SIGNAL ;
    PORT
      LAYER M4 ;
        RECT  0 56.832 0.192 56.856 ;
    END
  END o[527]
  PIN o[528]
    DIRECTION OUTPUT ;
    USE SIGNAL ;
    PORT
      LAYER M4 ;
        RECT  0 56.928 0.192 56.952 ;
    END
  END o[528]
  PIN o[529]
    DIRECTION OUTPUT ;
    USE SIGNAL ;
    PORT
      LAYER M4 ;
        RECT  0 57.024 0.192 57.048 ;
    END
  END o[529]
  PIN o[52]
    DIRECTION OUTPUT ;
    USE SIGNAL ;
    PORT
      LAYER M4 ;
        RECT  0 7.632 0.192 7.656 ;
    END
  END o[52]
  PIN o[530]
    DIRECTION OUTPUT ;
    USE SIGNAL ;
    PORT
      LAYER M4 ;
        RECT  0 57.12 0.192 57.144 ;
    END
  END o[530]
  PIN o[531]
    DIRECTION OUTPUT ;
    USE SIGNAL ;
    PORT
      LAYER M4 ;
        RECT  0 57.216 0.192 57.24 ;
    END
  END o[531]
  PIN o[532]
    DIRECTION OUTPUT ;
    USE SIGNAL ;
    PORT
      LAYER M4 ;
        RECT  0 57.312 0.192 57.336 ;
    END
  END o[532]
  PIN o[533]
    DIRECTION OUTPUT ;
    USE SIGNAL ;
    PORT
      LAYER M4 ;
        RECT  0 57.456 0.192 57.48 ;
    END
  END o[533]
  PIN o[534]
    DIRECTION OUTPUT ;
    USE SIGNAL ;
    PORT
      LAYER M4 ;
        RECT  0 57.552 0.192 57.576 ;
    END
  END o[534]
  PIN o[535]
    DIRECTION OUTPUT ;
    USE SIGNAL ;
    PORT
      LAYER M4 ;
        RECT  0 57.648 0.192 57.672 ;
    END
  END o[535]
  PIN o[536]
    DIRECTION OUTPUT ;
    USE SIGNAL ;
    PORT
      LAYER M4 ;
        RECT  0 57.744 0.192 57.768 ;
    END
  END o[536]
  PIN o[537]
    DIRECTION OUTPUT ;
    USE SIGNAL ;
    PORT
      LAYER M4 ;
        RECT  0 57.84 0.192 57.864 ;
    END
  END o[537]
  PIN o[538]
    DIRECTION OUTPUT ;
    USE SIGNAL ;
    PORT
      LAYER M4 ;
        RECT  0 57.936 0.192 57.96 ;
    END
  END o[538]
  PIN o[539]
    DIRECTION OUTPUT ;
    USE SIGNAL ;
    PORT
      LAYER M4 ;
        RECT  0 58.08 0.192 58.104 ;
    END
  END o[539]
  PIN o[53]
    DIRECTION OUTPUT ;
    USE SIGNAL ;
    PORT
      LAYER M4 ;
        RECT  0 7.728 0.192 7.752 ;
    END
  END o[53]
  PIN o[540]
    DIRECTION OUTPUT ;
    USE SIGNAL ;
    PORT
      LAYER M4 ;
        RECT  0 58.176 0.192 58.2 ;
    END
  END o[540]
  PIN o[541]
    DIRECTION OUTPUT ;
    USE SIGNAL ;
    PORT
      LAYER M4 ;
        RECT  0 58.272 0.192 58.296 ;
    END
  END o[541]
  PIN o[542]
    DIRECTION OUTPUT ;
    USE SIGNAL ;
    PORT
      LAYER M4 ;
        RECT  0 58.368 0.192 58.392 ;
    END
  END o[542]
  PIN o[543]
    DIRECTION OUTPUT ;
    USE SIGNAL ;
    PORT
      LAYER M4 ;
        RECT  0 58.464 0.192 58.488 ;
    END
  END o[543]
  PIN o[544]
    DIRECTION OUTPUT ;
    USE SIGNAL ;
    PORT
      LAYER M4 ;
        RECT  0 58.56 0.192 58.584 ;
    END
  END o[544]
  PIN o[545]
    DIRECTION OUTPUT ;
    USE SIGNAL ;
    PORT
      LAYER M4 ;
        RECT  0 58.656 0.192 58.68 ;
    END
  END o[545]
  PIN o[546]
    DIRECTION OUTPUT ;
    USE SIGNAL ;
    PORT
      LAYER M4 ;
        RECT  0 58.8 0.192 58.824 ;
    END
  END o[546]
  PIN o[547]
    DIRECTION OUTPUT ;
    USE SIGNAL ;
    PORT
      LAYER M4 ;
        RECT  0 58.896 0.192 58.92 ;
    END
  END o[547]
  PIN o[548]
    DIRECTION OUTPUT ;
    USE SIGNAL ;
    PORT
      LAYER M4 ;
        RECT  0 58.992 0.192 59.016 ;
    END
  END o[548]
  PIN o[549]
    DIRECTION OUTPUT ;
    USE SIGNAL ;
    PORT
      LAYER M4 ;
        RECT  0 59.088 0.192 59.112 ;
    END
  END o[549]
  PIN o[54]
    DIRECTION OUTPUT ;
    USE SIGNAL ;
    PORT
      LAYER M4 ;
        RECT  0 7.824 0.192 7.848 ;
    END
  END o[54]
  PIN o[550]
    DIRECTION OUTPUT ;
    USE SIGNAL ;
    PORT
      LAYER M4 ;
        RECT  0 59.184 0.192 59.208 ;
    END
  END o[550]
  PIN o[551]
    DIRECTION OUTPUT ;
    USE SIGNAL ;
    PORT
      LAYER M4 ;
        RECT  0 59.28 0.192 59.304 ;
    END
  END o[551]
  PIN o[552]
    DIRECTION OUTPUT ;
    USE SIGNAL ;
    PORT
      LAYER M4 ;
        RECT  0 59.424 0.192 59.448 ;
    END
  END o[552]
  PIN o[553]
    DIRECTION OUTPUT ;
    USE SIGNAL ;
    PORT
      LAYER M4 ;
        RECT  0 59.52 0.192 59.544 ;
    END
  END o[553]
  PIN o[554]
    DIRECTION OUTPUT ;
    USE SIGNAL ;
    PORT
      LAYER M4 ;
        RECT  0 59.616 0.192 59.64 ;
    END
  END o[554]
  PIN o[555]
    DIRECTION OUTPUT ;
    USE SIGNAL ;
    PORT
      LAYER M4 ;
        RECT  0 59.712 0.192 59.736 ;
    END
  END o[555]
  PIN o[556]
    DIRECTION OUTPUT ;
    USE SIGNAL ;
    PORT
      LAYER M4 ;
        RECT  0 59.808 0.192 59.832 ;
    END
  END o[556]
  PIN o[557]
    DIRECTION OUTPUT ;
    USE SIGNAL ;
    PORT
      LAYER M4 ;
        RECT  0 59.904 0.192 59.928 ;
    END
  END o[557]
  PIN o[558]
    DIRECTION OUTPUT ;
    USE SIGNAL ;
    PORT
      LAYER M4 ;
        RECT  0 60.048 0.192 60.072 ;
    END
  END o[558]
  PIN o[559]
    DIRECTION OUTPUT ;
    USE SIGNAL ;
    PORT
      LAYER M4 ;
        RECT  0 60.144 0.192 60.168 ;
    END
  END o[559]
  PIN o[55]
    DIRECTION OUTPUT ;
    USE SIGNAL ;
    PORT
      LAYER M4 ;
        RECT  0 7.92 0.192 7.944 ;
    END
  END o[55]
  PIN o[560]
    DIRECTION OUTPUT ;
    USE SIGNAL ;
    PORT
      LAYER M4 ;
        RECT  0 60.24 0.192 60.264 ;
    END
  END o[560]
  PIN o[561]
    DIRECTION OUTPUT ;
    USE SIGNAL ;
    PORT
      LAYER M4 ;
        RECT  0 60.336 0.192 60.36 ;
    END
  END o[561]
  PIN o[56]
    DIRECTION OUTPUT ;
    USE SIGNAL ;
    PORT
      LAYER M4 ;
        RECT  0 8.016 0.192 8.04 ;
    END
  END o[56]
  PIN o[57]
    DIRECTION OUTPUT ;
    USE SIGNAL ;
    PORT
      LAYER M4 ;
        RECT  0 8.112 0.192 8.136 ;
    END
  END o[57]
  PIN o[58]
    DIRECTION OUTPUT ;
    USE SIGNAL ;
    PORT
      LAYER M4 ;
        RECT  0 8.208 0.192 8.232 ;
    END
  END o[58]
  PIN o[59]
    DIRECTION OUTPUT ;
    USE SIGNAL ;
    PORT
      LAYER M4 ;
        RECT  0 8.352 0.192 8.376 ;
    END
  END o[59]
  PIN o[5]
    DIRECTION OUTPUT ;
    USE SIGNAL ;
    PORT
      LAYER M4 ;
        RECT  0 2.736 0.192 2.76 ;
    END
  END o[5]
  PIN o[60]
    DIRECTION OUTPUT ;
    USE SIGNAL ;
    PORT
      LAYER M4 ;
        RECT  0 8.448 0.192 8.472 ;
    END
  END o[60]
  PIN o[61]
    DIRECTION OUTPUT ;
    USE SIGNAL ;
    PORT
      LAYER M4 ;
        RECT  0 8.544 0.192 8.568 ;
    END
  END o[61]
  PIN o[62]
    DIRECTION OUTPUT ;
    USE SIGNAL ;
    PORT
      LAYER M4 ;
        RECT  0 8.64 0.192 8.664 ;
    END
  END o[62]
  PIN o[63]
    DIRECTION OUTPUT ;
    USE SIGNAL ;
    PORT
      LAYER M4 ;
        RECT  0 8.736 0.192 8.76 ;
    END
  END o[63]
  PIN o[64]
    DIRECTION OUTPUT ;
    USE SIGNAL ;
    PORT
      LAYER M4 ;
        RECT  0 8.832 0.192 8.856 ;
    END
  END o[64]
  PIN o[65]
    DIRECTION OUTPUT ;
    USE SIGNAL ;
    PORT
      LAYER M4 ;
        RECT  0 8.976 0.192 9 ;
    END
  END o[65]
  PIN o[66]
    DIRECTION OUTPUT ;
    USE SIGNAL ;
    PORT
      LAYER M4 ;
        RECT  0 9.072 0.192 9.096 ;
    END
  END o[66]
  PIN o[67]
    DIRECTION OUTPUT ;
    USE SIGNAL ;
    PORT
      LAYER M4 ;
        RECT  0 9.168 0.192 9.192 ;
    END
  END o[67]
  PIN o[68]
    DIRECTION OUTPUT ;
    USE SIGNAL ;
    PORT
      LAYER M4 ;
        RECT  0 9.264 0.192 9.288 ;
    END
  END o[68]
  PIN o[69]
    DIRECTION OUTPUT ;
    USE SIGNAL ;
    PORT
      LAYER M4 ;
        RECT  0 9.36 0.192 9.384 ;
    END
  END o[69]
  PIN o[6]
    DIRECTION OUTPUT ;
    USE SIGNAL ;
    PORT
      LAYER M4 ;
        RECT  0 2.832 0.192 2.856 ;
    END
  END o[6]
  PIN o[70]
    DIRECTION OUTPUT ;
    USE SIGNAL ;
    PORT
      LAYER M4 ;
        RECT  0 9.456 0.192 9.48 ;
    END
  END o[70]
  PIN o[71]
    DIRECTION OUTPUT ;
    USE SIGNAL ;
    PORT
      LAYER M4 ;
        RECT  0 9.6 0.192 9.624 ;
    END
  END o[71]
  PIN o[72]
    DIRECTION OUTPUT ;
    USE SIGNAL ;
    PORT
      LAYER M4 ;
        RECT  0 9.696 0.192 9.72 ;
    END
  END o[72]
  PIN o[73]
    DIRECTION OUTPUT ;
    USE SIGNAL ;
    PORT
      LAYER M4 ;
        RECT  0 9.792 0.192 9.816 ;
    END
  END o[73]
  PIN o[74]
    DIRECTION OUTPUT ;
    USE SIGNAL ;
    PORT
      LAYER M4 ;
        RECT  0 9.888 0.192 9.912 ;
    END
  END o[74]
  PIN o[75]
    DIRECTION OUTPUT ;
    USE SIGNAL ;
    PORT
      LAYER M4 ;
        RECT  0 9.984 0.192 10.008 ;
    END
  END o[75]
  PIN o[76]
    DIRECTION OUTPUT ;
    USE SIGNAL ;
    PORT
      LAYER M4 ;
        RECT  0 10.08 0.192 10.104 ;
    END
  END o[76]
  PIN o[77]
    DIRECTION OUTPUT ;
    USE SIGNAL ;
    PORT
      LAYER M4 ;
        RECT  0 10.224 0.192 10.248 ;
    END
  END o[77]
  PIN o[78]
    DIRECTION OUTPUT ;
    USE SIGNAL ;
    PORT
      LAYER M4 ;
        RECT  0 10.32 0.192 10.344 ;
    END
  END o[78]
  PIN o[79]
    DIRECTION OUTPUT ;
    USE SIGNAL ;
    PORT
      LAYER M4 ;
        RECT  0 10.416 0.192 10.44 ;
    END
  END o[79]
  PIN o[7]
    DIRECTION OUTPUT ;
    USE SIGNAL ;
    PORT
      LAYER M4 ;
        RECT  0 2.928 0.192 2.952 ;
    END
  END o[7]
  PIN o[80]
    DIRECTION OUTPUT ;
    USE SIGNAL ;
    PORT
      LAYER M4 ;
        RECT  0 10.512 0.192 10.536 ;
    END
  END o[80]
  PIN o[81]
    DIRECTION OUTPUT ;
    USE SIGNAL ;
    PORT
      LAYER M4 ;
        RECT  0 10.608 0.192 10.632 ;
    END
  END o[81]
  PIN o[82]
    DIRECTION OUTPUT ;
    USE SIGNAL ;
    PORT
      LAYER M4 ;
        RECT  0 10.704 0.192 10.728 ;
    END
  END o[82]
  PIN o[83]
    DIRECTION OUTPUT ;
    USE SIGNAL ;
    PORT
      LAYER M4 ;
        RECT  0 10.8 0.192 10.824 ;
    END
  END o[83]
  PIN o[84]
    DIRECTION OUTPUT ;
    USE SIGNAL ;
    PORT
      LAYER M4 ;
        RECT  0 10.944 0.192 10.968 ;
    END
  END o[84]
  PIN o[85]
    DIRECTION OUTPUT ;
    USE SIGNAL ;
    PORT
      LAYER M4 ;
        RECT  0 11.04 0.192 11.064 ;
    END
  END o[85]
  PIN o[86]
    DIRECTION OUTPUT ;
    USE SIGNAL ;
    PORT
      LAYER M4 ;
        RECT  0 11.136 0.192 11.16 ;
    END
  END o[86]
  PIN o[87]
    DIRECTION OUTPUT ;
    USE SIGNAL ;
    PORT
      LAYER M4 ;
        RECT  0 11.232 0.192 11.256 ;
    END
  END o[87]
  PIN o[88]
    DIRECTION OUTPUT ;
    USE SIGNAL ;
    PORT
      LAYER M4 ;
        RECT  0 11.328 0.192 11.352 ;
    END
  END o[88]
  PIN o[89]
    DIRECTION OUTPUT ;
    USE SIGNAL ;
    PORT
      LAYER M4 ;
        RECT  0 11.424 0.192 11.448 ;
    END
  END o[89]
  PIN o[8]
    DIRECTION OUTPUT ;
    USE SIGNAL ;
    PORT
      LAYER M4 ;
        RECT  0 3.072 0.192 3.096 ;
    END
  END o[8]
  PIN o[90]
    DIRECTION OUTPUT ;
    USE SIGNAL ;
    PORT
      LAYER M4 ;
        RECT  0 11.568 0.192 11.592 ;
    END
  END o[90]
  PIN o[91]
    DIRECTION OUTPUT ;
    USE SIGNAL ;
    PORT
      LAYER M4 ;
        RECT  0 11.664 0.192 11.688 ;
    END
  END o[91]
  PIN o[92]
    DIRECTION OUTPUT ;
    USE SIGNAL ;
    PORT
      LAYER M4 ;
        RECT  0 11.76 0.192 11.784 ;
    END
  END o[92]
  PIN o[93]
    DIRECTION OUTPUT ;
    USE SIGNAL ;
    PORT
      LAYER M4 ;
        RECT  0 11.856 0.192 11.88 ;
    END
  END o[93]
  PIN o[94]
    DIRECTION OUTPUT ;
    USE SIGNAL ;
    PORT
      LAYER M4 ;
        RECT  0 11.952 0.192 11.976 ;
    END
  END o[94]
  PIN o[95]
    DIRECTION OUTPUT ;
    USE SIGNAL ;
    PORT
      LAYER M4 ;
        RECT  0 12.048 0.192 12.072 ;
    END
  END o[95]
  PIN o[96]
    DIRECTION OUTPUT ;
    USE SIGNAL ;
    PORT
      LAYER M4 ;
        RECT  0 12.192 0.192 12.216 ;
    END
  END o[96]
  PIN o[97]
    DIRECTION OUTPUT ;
    USE SIGNAL ;
    PORT
      LAYER M4 ;
        RECT  0 12.288 0.192 12.312 ;
    END
  END o[97]
  PIN o[98]
    DIRECTION OUTPUT ;
    USE SIGNAL ;
    PORT
      LAYER M4 ;
        RECT  0 12.384 0.192 12.408 ;
    END
  END o[98]
  PIN o[99]
    DIRECTION OUTPUT ;
    USE SIGNAL ;
    PORT
      LAYER M4 ;
        RECT  0 12.48 0.192 12.504 ;
    END
  END o[99]
  PIN o[9]
    DIRECTION OUTPUT ;
    USE SIGNAL ;
    PORT
      LAYER M4 ;
        RECT  0 3.168 0.192 3.192 ;
    END
  END o[9]
  PIN rs
    DIRECTION INPUT ;
    USE SIGNAL ;
    PORT
      LAYER M5 ;
        RECT  11.856 62.448 11.88 62.64 ;
    END
  END rs
  PIN VDD
    DIRECTION INOUT ;
    USE POWER ;
    PORT
      LAYER M5 ;
        RECT  13.392 2.151 13.512 60.489 ;
        RECT  10.692 2.151 10.812 60.489 ;
        RECT  7.992 2.151 8.112 60.489 ;
        RECT  5.292 2.151 5.412 60.489 ;
        RECT  2.592 2.151 2.712 60.489 ;
    END
  END VDD
  PIN VSS
    DIRECTION INOUT ;
    USE GROUND ;
    PORT
      LAYER M5 ;
        RECT  13.2 2.137 13.32 60.503 ;
        RECT  10.5 2.137 10.62 60.503 ;
        RECT  7.8 2.137 7.92 60.503 ;
        RECT  5.1 2.137 5.22 60.503 ;
        RECT  2.4 2.137 2.52 60.503 ;
    END
  END VSS
  OBS
    LAYER RVTN ;
     RECT  2.16 2.16 15.12 2.295 ;
     RECT  2.16 2.565 15.12 2.835 ;
     RECT  2.16 3.105 15.12 3.375 ;
     RECT  2.16 3.645 15.12 3.915 ;
     RECT  2.16 4.185 15.12 4.455 ;
     RECT  2.16 4.725 15.12 4.995 ;
     RECT  2.16 5.265 15.12 5.535 ;
     RECT  2.16 5.805 15.12 6.075 ;
     RECT  2.16 6.345 15.12 6.615 ;
     RECT  2.16 6.885 15.12 7.155 ;
     RECT  2.16 7.425 15.12 7.695 ;
     RECT  2.16 7.965 15.12 8.235 ;
     RECT  2.16 8.505 15.12 8.775 ;
     RECT  2.16 9.045 15.12 9.315 ;
     RECT  2.16 9.585 15.12 9.855 ;
     RECT  2.16 10.125 15.12 10.395 ;
     RECT  2.16 10.665 15.12 10.935 ;
     RECT  2.16 11.205 15.12 11.475 ;
     RECT  2.16 11.745 15.12 12.015 ;
     RECT  2.16 12.285 15.12 12.555 ;
     RECT  2.16 12.825 15.12 13.095 ;
     RECT  2.16 13.365 15.12 13.635 ;
     RECT  2.16 13.905 15.12 14.175 ;
     RECT  2.16 14.445 15.12 14.715 ;
     RECT  2.16 14.985 15.12 15.255 ;
     RECT  2.16 15.525 15.12 15.795 ;
     RECT  2.16 16.065 15.12 16.335 ;
     RECT  2.16 16.605 15.12 16.875 ;
     RECT  2.16 17.145 15.12 17.415 ;
     RECT  2.16 17.685 15.12 17.955 ;
     RECT  2.16 18.225 15.12 18.495 ;
     RECT  2.16 18.765 15.12 19.035 ;
     RECT  2.16 19.305 15.12 19.575 ;
     RECT  2.16 19.845 15.12 20.115 ;
     RECT  2.16 20.385 15.12 20.655 ;
     RECT  2.16 20.925 15.12 21.195 ;
     RECT  2.16 21.465 15.12 21.735 ;
     RECT  2.16 22.005 15.12 22.275 ;
     RECT  2.16 22.545 15.12 22.815 ;
     RECT  2.16 23.085 15.12 23.355 ;
     RECT  2.16 23.625 15.12 23.895 ;
     RECT  2.16 24.165 15.12 24.435 ;
     RECT  2.16 24.705 15.12 24.975 ;
     RECT  2.16 25.245 15.12 25.515 ;
     RECT  2.16 25.785 15.12 26.055 ;
     RECT  2.16 26.325 15.12 26.595 ;
     RECT  2.16 26.865 15.12 27.135 ;
     RECT  2.16 27.405 15.12 27.675 ;
     RECT  2.16 27.945 15.12 28.215 ;
     RECT  2.16 28.485 15.12 28.755 ;
     RECT  2.16 29.025 15.12 29.295 ;
     RECT  2.16 29.565 15.12 29.835 ;
     RECT  2.16 30.105 15.12 30.375 ;
     RECT  2.16 30.645 15.12 30.915 ;
     RECT  2.16 31.185 15.12 31.455 ;
     RECT  2.16 31.725 15.12 31.995 ;
     RECT  2.16 32.265 15.12 32.535 ;
     RECT  2.16 32.805 15.12 33.075 ;
     RECT  2.16 33.345 15.12 33.615 ;
     RECT  2.16 33.885 15.12 34.155 ;
     RECT  2.16 34.425 15.12 34.695 ;
     RECT  2.16 34.965 15.12 35.235 ;
     RECT  2.16 35.505 15.12 35.775 ;
     RECT  2.16 36.045 15.12 36.315 ;
     RECT  2.16 36.585 15.12 36.855 ;
     RECT  2.16 37.125 15.12 37.395 ;
     RECT  2.16 37.665 15.12 37.935 ;
     RECT  2.16 38.205 15.12 38.475 ;
     RECT  2.16 38.745 15.12 39.015 ;
     RECT  2.16 39.285 15.12 39.555 ;
     RECT  2.16 39.825 15.12 40.095 ;
     RECT  2.16 40.365 15.12 40.635 ;
     RECT  2.16 40.905 15.12 41.175 ;
     RECT  2.16 41.445 15.12 41.715 ;
     RECT  2.16 41.985 15.12 42.255 ;
     RECT  2.16 42.525 15.12 42.795 ;
     RECT  2.16 43.065 15.12 43.335 ;
     RECT  2.16 43.605 15.12 43.875 ;
     RECT  2.16 44.145 15.12 44.415 ;
     RECT  2.16 44.685 15.12 44.955 ;
     RECT  2.16 45.225 15.12 45.495 ;
     RECT  2.16 45.765 15.12 46.035 ;
     RECT  2.16 46.305 15.12 46.575 ;
     RECT  2.16 46.845 15.12 47.115 ;
     RECT  2.16 47.385 15.12 47.655 ;
     RECT  2.16 47.925 15.12 48.195 ;
     RECT  2.16 48.465 15.12 48.735 ;
     RECT  2.16 49.005 15.12 49.275 ;
     RECT  2.16 49.545 15.12 49.815 ;
     RECT  2.16 50.085 15.12 50.355 ;
     RECT  2.16 50.625 15.12 50.895 ;
     RECT  2.16 51.165 15.12 51.435 ;
     RECT  2.16 51.705 15.12 51.975 ;
     RECT  2.16 52.245 15.12 52.515 ;
     RECT  2.16 52.785 15.12 53.055 ;
     RECT  2.16 53.325 15.12 53.595 ;
     RECT  2.16 53.865 15.12 54.135 ;
     RECT  2.16 54.405 15.12 54.675 ;
     RECT  2.16 54.945 15.12 55.215 ;
     RECT  2.16 55.485 15.12 55.755 ;
     RECT  2.16 56.025 15.12 56.295 ;
     RECT  2.16 56.565 15.12 56.835 ;
     RECT  2.16 57.105 15.12 57.375 ;
     RECT  2.16 57.645 15.12 57.915 ;
     RECT  2.16 58.185 15.12 58.455 ;
     RECT  2.16 58.725 15.12 58.995 ;
     RECT  2.16 59.265 15.12 59.535 ;
     RECT  2.16 59.805 15.12 60.075 ;
     RECT  2.16 60.345 15.12 60.48 ;
    LAYER RVTP ;
     RECT  2.16 2.295 15.12 2.565 ;
     RECT  2.16 2.835 15.12 3.105 ;
     RECT  2.16 3.375 15.12 3.645 ;
     RECT  2.16 3.915 15.12 4.185 ;
     RECT  2.16 4.455 15.12 4.725 ;
     RECT  2.16 4.995 15.12 5.265 ;
     RECT  2.16 5.535 15.12 5.805 ;
     RECT  2.16 6.075 15.12 6.345 ;
     RECT  2.16 6.615 15.12 6.885 ;
     RECT  2.16 7.155 15.12 7.425 ;
     RECT  2.16 7.695 15.12 7.965 ;
     RECT  2.16 8.235 15.12 8.505 ;
     RECT  2.16 8.775 15.12 9.045 ;
     RECT  2.16 9.315 15.12 9.585 ;
     RECT  2.16 9.855 15.12 10.125 ;
     RECT  2.16 10.395 15.12 10.665 ;
     RECT  2.16 10.935 15.12 11.205 ;
     RECT  2.16 11.475 15.12 11.745 ;
     RECT  2.16 12.015 15.12 12.285 ;
     RECT  2.16 12.555 15.12 12.825 ;
     RECT  2.16 13.095 15.12 13.365 ;
     RECT  2.16 13.635 15.12 13.905 ;
     RECT  2.16 14.175 15.12 14.445 ;
     RECT  2.16 14.715 15.12 14.985 ;
     RECT  2.16 15.255 15.12 15.525 ;
     RECT  2.16 15.795 15.12 16.065 ;
     RECT  2.16 16.335 15.12 16.605 ;
     RECT  2.16 16.875 15.12 17.145 ;
     RECT  2.16 17.415 15.12 17.685 ;
     RECT  2.16 17.955 15.12 18.225 ;
     RECT  2.16 18.495 15.12 18.765 ;
     RECT  2.16 19.035 15.12 19.305 ;
     RECT  2.16 19.575 15.12 19.845 ;
     RECT  2.16 20.115 15.12 20.385 ;
     RECT  2.16 20.655 15.12 20.925 ;
     RECT  2.16 21.195 15.12 21.465 ;
     RECT  2.16 21.735 15.12 22.005 ;
     RECT  2.16 22.275 15.12 22.545 ;
     RECT  2.16 22.815 15.12 23.085 ;
     RECT  2.16 23.355 15.12 23.625 ;
     RECT  2.16 23.895 15.12 24.165 ;
     RECT  2.16 24.435 15.12 24.705 ;
     RECT  2.16 24.975 15.12 25.245 ;
     RECT  2.16 25.515 15.12 25.785 ;
     RECT  2.16 26.055 15.12 26.325 ;
     RECT  2.16 26.595 15.12 26.865 ;
     RECT  2.16 27.135 15.12 27.405 ;
     RECT  2.16 27.675 15.12 27.945 ;
     RECT  2.16 28.215 15.12 28.485 ;
     RECT  2.16 28.755 15.12 29.025 ;
     RECT  2.16 29.295 15.12 29.565 ;
     RECT  2.16 29.835 15.12 30.105 ;
     RECT  2.16 30.375 15.12 30.645 ;
     RECT  2.16 30.915 15.12 31.185 ;
     RECT  2.16 31.455 15.12 31.725 ;
     RECT  2.16 31.995 15.12 32.265 ;
     RECT  2.16 32.535 15.12 32.805 ;
     RECT  2.16 33.075 15.12 33.345 ;
     RECT  2.16 33.615 15.12 33.885 ;
     RECT  2.16 34.155 15.12 34.425 ;
     RECT  2.16 34.695 15.12 34.965 ;
     RECT  2.16 35.235 15.12 35.505 ;
     RECT  2.16 35.775 15.12 36.045 ;
     RECT  2.16 36.315 15.12 36.585 ;
     RECT  2.16 36.855 15.12 37.125 ;
     RECT  2.16 37.395 15.12 37.665 ;
     RECT  2.16 37.935 15.12 38.205 ;
     RECT  2.16 38.475 15.12 38.745 ;
     RECT  2.16 39.015 15.12 39.285 ;
     RECT  2.16 39.555 15.12 39.825 ;
     RECT  2.16 40.095 15.12 40.365 ;
     RECT  2.16 40.635 15.12 40.905 ;
     RECT  2.16 41.175 15.12 41.445 ;
     RECT  2.16 41.715 15.12 41.985 ;
     RECT  2.16 42.255 15.12 42.525 ;
     RECT  2.16 42.795 15.12 43.065 ;
     RECT  2.16 43.335 15.12 43.605 ;
     RECT  2.16 43.875 15.12 44.145 ;
     RECT  2.16 44.415 15.12 44.685 ;
     RECT  2.16 44.955 15.12 45.225 ;
     RECT  2.16 45.495 15.12 45.765 ;
     RECT  2.16 46.035 15.12 46.305 ;
     RECT  2.16 46.575 15.12 46.845 ;
     RECT  2.16 47.115 15.12 47.385 ;
     RECT  2.16 47.655 15.12 47.925 ;
     RECT  2.16 48.195 15.12 48.465 ;
     RECT  2.16 48.735 15.12 49.005 ;
     RECT  2.16 49.275 15.12 49.545 ;
     RECT  2.16 49.815 15.12 50.085 ;
     RECT  2.16 50.355 15.12 50.625 ;
     RECT  2.16 50.895 15.12 51.165 ;
     RECT  2.16 51.435 15.12 51.705 ;
     RECT  2.16 51.975 15.12 52.245 ;
     RECT  2.16 52.515 15.12 52.785 ;
     RECT  2.16 53.055 15.12 53.325 ;
     RECT  2.16 53.595 15.12 53.865 ;
     RECT  2.16 54.135 15.12 54.405 ;
     RECT  2.16 54.675 15.12 54.945 ;
     RECT  2.16 55.215 15.12 55.485 ;
     RECT  2.16 55.755 15.12 56.025 ;
     RECT  2.16 56.295 15.12 56.565 ;
     RECT  2.16 56.835 15.12 57.105 ;
     RECT  2.16 57.375 15.12 57.645 ;
     RECT  2.16 57.915 15.12 58.185 ;
     RECT  2.16 58.455 15.12 58.725 ;
     RECT  2.16 58.995 15.12 59.265 ;
     RECT  2.16 59.535 15.12 59.805 ;
     RECT  2.16 60.075 15.12 60.345 ;
    LAYER M1 ;
     RECT  2.16 2.151 15.12 60.489 ;
    LAYER M2 ;
     RECT  0.211 2.844 0.311 2.862 ;
     RECT  0.211 13.986 0.311 14.166 ;
     RECT  0.211 19.116 0.311 19.134 ;
     RECT  0.211 31.311 0.311 31.329 ;
     RECT  0.211 41.616 0.311 41.634 ;
     RECT  0.211 50.481 0.311 50.499 ;
     RECT  0.211 60.318 0.311 60.336 ;
     RECT  0.247 8.208 0.347 8.226 ;
     RECT  0.211 27.108 0.347 27.864 ;
     RECT  0.247 29.034 0.347 29.052 ;
     RECT  0.211 54.036 0.347 54.666 ;
     RECT  0.211 58.5 0.347 58.518 ;
     RECT  0.283 14.958 0.383 14.976 ;
     RECT  0.283 26.136 0.383 26.154 ;
     RECT  0.499 21.636 0.535 21.654 ;
     RECT  0.211 22.446 0.535 22.464 ;
     RECT  2.119 2.538 2.16 2.556 ;
     RECT  0.535 6.588 2.16 6.606 ;
     RECT  0.535 8.316 2.16 8.334 ;
     RECT  0.211 11.556 2.16 11.574 ;
     RECT  0.535 12.906 2.16 12.924 ;
     RECT  0.535 15.228 2.16 15.246 ;
     RECT  0.535 16.956 2.16 17.64 ;
     RECT  0.535 21.474 2.16 22.464 ;
     RECT  0.211 23.976 2.16 23.994 ;
     RECT  0.347 27.846 2.16 27.864 ;
     RECT  0.535 31.698 2.16 31.716 ;
     RECT  0.535 36.936 2.16 36.954 ;
     RECT  0.211 43.506 2.16 43.524 ;
     RECT  0.211 44.856 2.16 44.874 ;
     RECT  0.535 47.826 2.16 47.844 ;
     RECT  0.535 49.554 2.16 49.572 ;
     RECT  0.535 52.146 2.16 52.164 ;
     RECT  0.535 53.136 2.16 53.154 ;
     RECT  0.347 54.036 2.16 54.054 ;
     RECT  0.535 55.728 2.16 55.746 ;
     RECT  0.535 57.996 2.16 58.014 ;
     RECT  2.16 2.151 3.091 60.489 ;
     RECT  3.091 2.151 3.811 60.534 ;
     RECT  3.811 2.07 6.979 60.534 ;
     RECT  6.979 1.962 7.339 60.534 ;
     RECT  7.339 1.962 10.103 60.642 ;
     RECT  10.103 1.962 11.183 60.57 ;
     RECT  11.183 1.962 11.723 60.534 ;
     RECT  11.723 2.034 12.703 60.534 ;
     RECT  12.703 1.998 13.099 60.534 ;
     RECT  13.099 1.998 13.415 60.57 ;
     RECT  13.415 1.998 13.919 60.534 ;
     RECT  13.919 1.998 14.099 60.489 ;
     RECT  14.099 2.034 15.12 60.489 ;
     RECT  15.12 3.276 15.431 19.296 ;
     RECT  15.12 20.088 15.431 29.862 ;
     RECT  15.12 30.618 15.431 38.97 ;
     RECT  15.12 39.798 15.431 52.884 ;
     RECT  15.12 53.91 15.431 60.336 ;
     RECT  15.431 10.44 15.467 12.888 ;
     RECT  15.431 15.84 15.467 18.72 ;
     RECT  15.431 36.36 15.467 37.764 ;
     RECT  15.431 40.68 15.467 42.75 ;
     RECT  15.431 50.67 15.467 52.812 ;
     RECT  15.431 57.384 15.467 58.518 ;
     RECT  15.431 59.508 15.467 59.76 ;
     RECT  15.467 17.622 15.503 18.72 ;
     RECT  15.431 45.234 15.971 47.106 ;
     RECT  15.12 2.034 16.007 2.25 ;
     RECT  15.467 10.566 16.007 12.582 ;
     RECT  15.431 32.31 16.007 33.444 ;
     RECT  15.971 46.854 16.007 47.106 ;
     RECT  15.431 47.862 16.007 47.88 ;
     RECT  15.431 4.5 16.547 6.372 ;
     RECT  15.431 7.776 16.547 9.648 ;
     RECT  16.007 10.566 16.547 11.502 ;
     RECT  16.007 12.564 16.547 12.582 ;
     RECT  15.467 15.84 16.547 16.668 ;
     RECT  15.503 18.036 16.547 18.72 ;
     RECT  15.431 20.898 16.547 20.916 ;
     RECT  15.431 21.672 16.547 23.31 ;
     RECT  15.431 25.29 16.547 28.818 ;
     RECT  16.007 32.31 16.547 33.408 ;
     RECT  15.431 34.362 16.547 34.38 ;
     RECT  15.467 36.594 16.547 37.764 ;
     RECT  15.431 38.952 16.547 38.97 ;
     RECT  15.467 40.68 16.547 41.238 ;
     RECT  15.467 41.994 16.547 42.75 ;
     RECT  15.431 43.812 16.547 44.442 ;
     RECT  15.431 49.086 16.547 49.842 ;
     RECT  15.467 50.67 16.547 52.074 ;
     RECT  15.431 54.954 16.547 56.592 ;
     RECT  15.467 58.5 16.547 58.518 ;
     RECT  15.467 59.742 16.547 59.76 ;
     RECT  16.007 2.106 16.583 2.25 ;
     RECT  15.431 3.456 16.583 3.708 ;
     RECT  16.547 21.672 16.583 22.338 ;
     RECT  16.547 25.29 16.583 26.244 ;
     RECT  15.431 29.61 16.583 29.862 ;
     RECT  15.971 45.234 16.583 46.098 ;
     RECT  16.547 49.086 16.583 49.104 ;
     RECT  15.467 57.384 16.583 57.6 ;
     RECT  16.547 7.776 16.619 9.036 ;
     RECT  16.583 29.61 16.619 29.664 ;
     RECT  16.619 7.776 16.655 7.992 ;
     RECT  16.583 21.672 16.655 22.302 ;
     RECT  16.547 10.566 17.059 10.89 ;
     RECT  15.431 24.21 17.059 24.39 ;
     RECT  16.547 36.792 17.059 37.764 ;
     RECT  16.547 41.994 17.059 42.246 ;
     RECT  16.547 44.271 17.059 44.442 ;
     RECT  16.583 45.972 17.059 46.098 ;
     RECT  16.007 47.088 17.059 47.106 ;
     RECT  16.547 51.48 17.059 52.074 ;
     RECT  16.547 56.538 17.059 56.592 ;
     RECT  16.547 5.238 17.087 5.256 ;
     RECT  17.059 2.808 17.159 3.33 ;
     RECT  17.059 4.158 17.159 4.176 ;
     RECT  16.547 6.084 17.159 6.102 ;
     RECT  17.059 7.506 17.159 7.524 ;
     RECT  16.619 8.748 17.159 9.036 ;
     RECT  17.059 10.206 17.159 10.89 ;
     RECT  17.059 12.06 17.159 12.276 ;
     RECT  17.059 13.716 17.159 14.166 ;
     RECT  17.059 14.994 17.159 15.012 ;
     RECT  17.059 17.316 17.159 17.334 ;
     RECT  16.655 21.672 17.159 21.69 ;
     RECT  17.059 24.138 17.159 24.966 ;
     RECT  16.583 25.992 17.159 26.244 ;
     RECT  17.059 29.304 17.159 29.556 ;
     RECT  17.059 34.128 17.159 34.146 ;
     RECT  17.059 34.938 17.159 34.956 ;
     RECT  17.059 36.792 17.159 37.998 ;
     RECT  17.059 39.294 17.159 39.312 ;
     RECT  17.059 41.571 17.159 42.246 ;
     RECT  17.059 44.271 17.159 44.946 ;
     RECT  17.059 45.972 17.159 47.376 ;
     RECT  17.059 48.402 17.159 48.996 ;
     RECT  17.059 50.526 17.159 50.544 ;
     RECT  17.059 51.48 17.159 53.856 ;
     RECT  17.059 56.538 17.159 56.934 ;
     RECT  17.059 58.536 17.159 58.986 ;
    LAYER M3 ;
     RECT  3.672 2.059 3.69 2.065 ;
     RECT  14.076 1.993 14.094 2.065 ;
     RECT  8.064 2.029 8.082 2.101 ;
     RECT  15.984 2.029 16.002 2.101 ;
     RECT  12.708 1.993 12.726 2.143 ;
     RECT  13.824 2.065 14.094 2.143 ;
     RECT  7.74 2.101 8.082 2.191 ;
     RECT  2.415 2.143 2.505 2.299 ;
     RECT  10.515 2.143 10.605 2.299 ;
     RECT  11.7 1.957 11.718 2.299 ;
     RECT  12.708 2.143 14.094 2.299 ;
     RECT  3.672 2.065 3.834 2.335 ;
     RECT  5.115 2.143 5.205 2.335 ;
     RECT  10.515 2.299 11.718 2.335 ;
     RECT  12.492 2.299 14.094 2.335 ;
     RECT  3.672 2.335 5.205 2.371 ;
     RECT  9.54 2.263 9.558 2.371 ;
     RECT  9.036 2.371 9.558 2.395 ;
     RECT  10.515 2.335 14.094 2.395 ;
     RECT  2.34 2.299 2.505 2.413 ;
     RECT  3.672 2.371 5.274 2.413 ;
     RECT  2.34 2.413 2.697 2.443 ;
     RECT  2.304 2.443 2.697 2.461 ;
     RECT  3.672 2.413 5.397 2.461 ;
     RECT  15.984 2.101 16.578 2.477 ;
     RECT  6.984 1.957 7.002 2.491 ;
     RECT  7.74 2.191 8.226 2.491 ;
     RECT  6.984 2.491 8.226 2.497 ;
     RECT  9.036 2.395 14.094 2.497 ;
     RECT  2.304 2.461 5.397 2.533 ;
     RECT  6.984 2.497 14.094 2.533 ;
     RECT  15.984 2.477 16.002 2.573 ;
     RECT  6.84 2.533 14.094 2.605 ;
     RECT  14.832 2.299 14.85 2.605 ;
     RECT  6.84 2.605 14.85 2.641 ;
     RECT  0.216 2.059 0.234 2.839 ;
     RECT  2.124 2.533 5.397 2.875 ;
     RECT  6.84 2.641 14.886 2.875 ;
     RECT  0.216 2.839 0.306 2.909 ;
     RECT  6.768 2.875 14.886 2.923 ;
     RECT  0.216 2.909 0.234 2.957 ;
     RECT  2.124 2.875 5.49 3.029 ;
     RECT  5.076 3.029 5.49 3.065 ;
     RECT  5.076 3.065 5.397 3.173 ;
     RECT  6.768 2.923 15.426 3.173 ;
     RECT  6.804 3.173 15.426 3.197 ;
     RECT  17.064 2.779 17.154 3.344 ;
     RECT  2.124 3.029 4.266 3.629 ;
     RECT  6.804 3.197 13.914 3.839 ;
     RECT  6.804 3.839 13.842 3.869 ;
     RECT  6.804 3.869 13.59 3.979 ;
     RECT  14.796 3.197 15.426 3.983 ;
     RECT  16.524 3.451 16.578 4.123 ;
     RECT  16.524 4.123 17.154 4.181 ;
     RECT  16.524 4.181 17.082 4.205 ;
     RECT  6.624 3.979 13.59 4.289 ;
     RECT  2.268 3.629 4.266 4.301 ;
     RECT  5.115 3.173 5.397 4.423 ;
     RECT  5.115 4.423 5.706 4.493 ;
     RECT  2.304 4.301 4.266 4.507 ;
     RECT  5.115 4.493 5.397 4.507 ;
     RECT  6.624 4.289 11.214 4.541 ;
     RECT  11.952 4.289 13.59 4.589 ;
     RECT  2.304 4.507 5.397 4.649 ;
     RECT  2.304 4.649 4.338 4.721 ;
     RECT  12.312 4.589 13.59 4.747 ;
     RECT  14.832 3.983 15.426 4.793 ;
     RECT  12.312 4.747 13.842 4.801 ;
     RECT  14.832 4.793 14.922 4.801 ;
     RECT  2.304 4.721 4.266 4.829 ;
     RECT  12.312 4.801 14.922 5.027 ;
     RECT  14.616 5.027 14.922 5.069 ;
     RECT  14.616 5.069 14.886 5.099 ;
     RECT  6.66 4.541 11.214 5.225 ;
     RECT  16.524 4.205 16.578 5.227 ;
     RECT  16.524 5.227 17.082 5.267 ;
     RECT  14.832 5.099 14.886 5.531 ;
     RECT  12.312 5.027 13.77 5.539 ;
     RECT  6.732 5.225 11.214 5.611 ;
     RECT  11.952 5.539 13.77 5.611 ;
     RECT  5.115 4.649 5.397 5.737 ;
     RECT  6.732 5.611 13.77 5.809 ;
     RECT  6.732 5.809 13.986 5.837 ;
     RECT  2.304 4.829 4.014 5.881 ;
     RECT  5.112 5.737 5.397 5.881 ;
     RECT  2.304 5.881 5.397 6.037 ;
     RECT  16.524 5.267 16.542 6.043 ;
     RECT  2.304 6.037 5.742 6.077 ;
     RECT  16.524 6.043 17.082 6.079 ;
     RECT  16.524 6.079 17.154 6.125 ;
     RECT  6.804 5.837 13.986 6.269 ;
     RECT  12.564 6.269 13.986 6.313 ;
     RECT  14.832 5.531 14.85 6.313 ;
     RECT  7.272 6.269 11.682 6.317 ;
     RECT  12.564 6.313 14.85 6.331 ;
     RECT  16.524 6.125 16.542 6.377 ;
     RECT  2.304 6.077 5.397 6.475 ;
     RECT  12.564 6.331 14.958 6.571 ;
     RECT  2.268 6.475 5.397 6.605 ;
     RECT  2.268 6.605 4.266 6.719 ;
     RECT  7.344 6.317 11.682 6.809 ;
     RECT  0.54 6.583 0.558 6.893 ;
     RECT  7.38 6.809 11.682 7.195 ;
     RECT  12.564 6.571 15.426 7.195 ;
     RECT  7.38 7.195 15.426 7.385 ;
     RECT  17.136 7.483 17.154 7.501 ;
     RECT  17.064 7.501 17.154 7.529 ;
     RECT  17.064 7.529 17.082 7.565 ;
     RECT  7.38 7.385 13.914 7.661 ;
     RECT  14.868 7.385 15.426 7.691 ;
     RECT  2.304 6.719 4.266 7.699 ;
     RECT  5.004 6.605 5.397 7.699 ;
     RECT  7.38 7.661 13.842 7.861 ;
     RECT  7.236 7.861 13.842 7.915 ;
     RECT  0.252 7.963 0.27 8.155 ;
     RECT  7.092 7.915 13.842 8.155 ;
     RECT  2.304 7.699 5.397 8.189 ;
     RECT  5.115 8.189 5.397 8.203 ;
     RECT  6.984 8.155 13.842 8.239 ;
     RECT  0.252 8.155 0.342 8.24 ;
     RECT  6.876 8.239 13.842 8.401 ;
     RECT  14.868 7.691 14.886 8.401 ;
     RECT  2.304 8.189 4.23 8.429 ;
     RECT  5.115 8.203 5.706 8.429 ;
     RECT  6.876 8.401 14.886 8.443 ;
     RECT  2.304 8.429 4.158 8.477 ;
     RECT  6.876 8.443 15.426 8.539 ;
     RECT  0.54 8.311 0.558 8.573 ;
     RECT  2.304 8.477 4.05 8.699 ;
     RECT  16.524 7.723 16.65 8.731 ;
     RECT  16.524 8.731 17.154 9.053 ;
     RECT  3.816 8.699 4.05 9.101 ;
     RECT  4.032 9.101 4.05 9.307 ;
     RECT  4.032 9.307 4.194 9.347 ;
     RECT  6.804 8.539 15.426 9.383 ;
     RECT  6.804 9.383 14.958 9.389 ;
     RECT  5.115 8.429 5.397 9.595 ;
     RECT  16.524 9.053 16.542 9.653 ;
     RECT  2.304 8.699 3.078 9.751 ;
     RECT  2.196 9.751 3.078 9.821 ;
     RECT  2.304 9.821 3.078 9.895 ;
     RECT  5.115 9.595 5.454 10.027 ;
     RECT  7.128 9.389 14.958 10.123 ;
     RECT  5.115 10.027 5.49 10.157 ;
     RECT  7.128 10.123 15.426 10.291 ;
     RECT  6.696 10.291 15.426 10.315 ;
     RECT  5.115 10.157 5.397 10.411 ;
     RECT  6.696 10.315 15.462 10.427 ;
     RECT  17.064 10.171 17.154 10.561 ;
     RECT  4.536 10.411 5.397 10.589 ;
     RECT  2.304 9.895 3.726 10.633 ;
     RECT  0.252 9.835 0.27 10.829 ;
     RECT  16.524 10.561 17.154 10.925 ;
     RECT  2.304 10.633 4.23 11.101 ;
     RECT  2.196 11.101 4.23 11.165 ;
     RECT  6.84 10.427 15.462 11.173 ;
     RECT  6.264 11.173 15.462 11.201 ;
     RECT  6.264 11.201 15.426 11.261 ;
     RECT  16.524 10.925 16.542 11.507 ;
     RECT  2.304 11.165 4.23 11.551 ;
     RECT  0.216 11.551 0.234 11.597 ;
     RECT  2.304 11.551 4.338 11.803 ;
     RECT  5.115 10.589 5.397 11.803 ;
     RECT  6.408 11.261 15.426 11.849 ;
     RECT  6.408 11.849 14.958 11.939 ;
     RECT  6.768 11.939 14.958 12.029 ;
     RECT  15.984 11.947 16.002 12.029 ;
     RECT  2.304 11.803 5.397 12.091 ;
     RECT  17.064 12.043 17.154 12.281 ;
     RECT  17.064 12.281 17.082 12.317 ;
     RECT  2.304 12.091 5.454 12.325 ;
     RECT  2.304 12.325 5.562 12.331 ;
     RECT  6.768 12.029 11.574 12.353 ;
     RECT  6.84 12.353 11.574 12.389 ;
     RECT  2.304 12.331 5.634 12.595 ;
     RECT  12.636 12.029 14.958 12.619 ;
     RECT  12.636 12.619 15.426 12.757 ;
     RECT  12.6 12.757 15.426 12.811 ;
     RECT  12.6 12.811 15.462 12.893 ;
     RECT  2.304 12.595 5.706 12.929 ;
     RECT  12.6 12.893 15.426 12.929 ;
     RECT  0.54 12.901 0.558 13.133 ;
     RECT  16.524 12.523 16.578 13.133 ;
     RECT  12.6 12.929 14.058 13.135 ;
     RECT  6.912 12.389 11.574 13.147 ;
     RECT  6.912 13.147 11.718 13.288 ;
     RECT  12.456 13.135 14.058 13.288 ;
     RECT  2.304 12.929 5.397 13.289 ;
     RECT  6.912 13.288 14.058 13.289 ;
     RECT  16.56 13.133 16.578 13.373 ;
     RECT  2.304 13.289 4.302 13.559 ;
     RECT  2.304 13.559 3.114 13.613 ;
     RECT  4.212 13.559 4.302 13.667 ;
     RECT  5.115 13.289 5.397 13.711 ;
     RECT  6.12 13.675 6.138 13.711 ;
     RECT  0.288 13.675 0.306 13.723 ;
     RECT  5.115 13.711 6.138 13.915 ;
     RECT  6.984 13.289 14.058 13.981 ;
     RECT  14.832 12.929 15.426 13.981 ;
     RECT  6.984 13.981 15.426 14.009 ;
     RECT  5.115 13.915 6.246 14.071 ;
     RECT  17.064 13.675 17.154 14.171 ;
     RECT  7.344 14.009 15.426 14.189 ;
     RECT  17.064 14.171 17.082 14.189 ;
     RECT  5.076 14.071 6.246 14.207 ;
     RECT  7.452 14.189 15.426 14.207 ;
     RECT  7.452 14.207 14.094 14.243 ;
     RECT  4.212 13.667 4.23 14.341 ;
     RECT  5.076 14.207 6.174 14.369 ;
     RECT  0.216 13.723 0.306 14.381 ;
     RECT  4.104 14.341 4.23 14.44 ;
     RECT  5.076 14.369 6.102 14.441 ;
     RECT  2.304 13.613 2.862 14.521 ;
     RECT  3.744 14.44 4.23 14.521 ;
     RECT  2.304 14.521 4.23 14.611 ;
     RECT  5.076 14.441 5.526 14.611 ;
     RECT  2.304 14.611 5.526 14.669 ;
     RECT  12.42 14.243 14.094 14.675 ;
     RECT  0.288 14.381 0.306 14.875 ;
     RECT  5.112 14.669 5.526 14.909 ;
     RECT  7.452 14.243 11.466 14.917 ;
     RECT  2.304 14.669 4.122 14.989 ;
     RECT  17.064 14.971 17.082 14.989 ;
     RECT  0.288 14.875 0.45 15.005 ;
     RECT  17.064 14.989 17.154 15.053 ;
     RECT  12.6 14.675 14.094 15.061 ;
     RECT  14.832 14.207 15.426 15.061 ;
     RECT  7.272 14.917 11.466 15.187 ;
     RECT  12.6 15.061 15.426 15.215 ;
     RECT  0.432 15.005 0.45 15.223 ;
     RECT  0.432 15.223 0.558 15.245 ;
     RECT  2.268 14.989 4.122 15.245 ;
     RECT  12.6 15.215 13.986 15.251 ;
     RECT  7.128 15.187 11.466 15.287 ;
     RECT  7.308 15.287 11.466 15.295 ;
     RECT  5.112 14.909 5.397 15.421 ;
     RECT  12.6 15.251 13.842 15.449 ;
     RECT  12.6 15.449 13.806 15.457 ;
     RECT  7.308 15.295 11.646 15.493 ;
     RECT  12.564 15.457 13.806 15.493 ;
     RECT  14.832 15.215 15.426 15.521 ;
     RECT  0.54 15.245 0.558 15.533 ;
     RECT  14.832 15.521 15.03 15.581 ;
     RECT  2.268 15.245 3.618 15.725 ;
     RECT  4.356 15.421 5.397 15.899 ;
     RECT  2.304 15.725 3.618 16.013 ;
     RECT  3.42 16.013 3.618 16.025 ;
     RECT  3.492 16.025 3.618 16.105 ;
     RECT  7.308 15.493 13.806 16.105 ;
     RECT  0.252 16.027 0.27 16.157 ;
     RECT  3.492 16.105 4.302 16.169 ;
     RECT  5.076 15.899 5.397 16.231 ;
     RECT  6.912 16.105 13.806 16.231 ;
     RECT  6.912 16.231 13.914 16.267 ;
     RECT  14.832 15.581 14.958 16.303 ;
     RECT  14.832 16.303 15.426 16.349 ;
     RECT  6.84 16.267 13.914 16.363 ;
     RECT  5.076 16.231 5.634 16.501 ;
     RECT  6.804 16.363 13.914 16.529 ;
     RECT  5.076 16.501 5.706 16.573 ;
     RECT  6.804 16.529 11.574 16.573 ;
     RECT  16.524 15.691 16.542 16.673 ;
     RECT  3.528 16.169 4.302 16.681 ;
     RECT  5.076 16.573 11.574 16.681 ;
     RECT  2.304 16.013 2.697 16.699 ;
     RECT  2.268 16.699 2.697 16.943 ;
     RECT  2.304 16.943 2.697 16.951 ;
     RECT  3.528 16.681 11.574 16.951 ;
     RECT  12.456 16.529 13.914 16.951 ;
     RECT  12.456 16.951 13.986 17.149 ;
     RECT  14.832 16.349 14.886 17.149 ;
     RECT  12.456 17.149 14.886 17.179 ;
     RECT  17.064 17.275 17.082 17.311 ;
     RECT  0.54 16.951 0.558 17.323 ;
     RECT  12.456 17.179 15.426 17.339 ;
     RECT  17.064 17.311 17.154 17.357 ;
     RECT  14.832 17.339 15.426 17.371 ;
     RECT  0.252 17.323 0.558 17.453 ;
     RECT  2.304 16.951 11.574 17.609 ;
     RECT  14.832 17.371 15.462 17.617 ;
     RECT  5.04 17.609 11.574 17.681 ;
     RECT  0.54 17.453 0.558 17.789 ;
     RECT  14.832 17.617 15.498 17.837 ;
     RECT  6.732 17.681 11.574 17.851 ;
     RECT  12.456 17.339 14.094 17.851 ;
     RECT  16.56 17.755 16.578 18.031 ;
     RECT  2.304 17.609 4.302 18.149 ;
     RECT  2.304 18.149 3.186 18.221 ;
     RECT  5.04 17.681 5.598 18.317 ;
     RECT  16.524 18.031 16.578 18.317 ;
     RECT  6.732 17.851 14.094 18.419 ;
     RECT  6.732 18.419 13.914 18.475 ;
     RECT  6.696 18.475 13.914 18.535 ;
     RECT  6.444 18.535 13.914 18.701 ;
     RECT  14.832 17.837 14.922 18.715 ;
     RECT  16.524 18.317 16.542 18.725 ;
     RECT  7.092 18.701 13.914 18.749 ;
     RECT  14.796 18.715 14.922 18.811 ;
     RECT  3.924 18.149 4.302 18.841 ;
     RECT  5.04 18.317 5.397 18.841 ;
     RECT  0.252 18.907 0.27 19.111 ;
     RECT  3.924 18.841 5.397 19.111 ;
     RECT  14.796 18.811 15.426 19.195 ;
     RECT  0.216 19.111 0.306 19.229 ;
     RECT  3.708 19.111 5.397 19.229 ;
     RECT  0.252 19.229 0.306 19.277 ;
     RECT  2.304 18.221 2.754 19.471 ;
     RECT  7.308 18.749 13.914 19.483 ;
     RECT  7.164 19.483 13.914 19.651 ;
     RECT  14.76 19.195 15.426 19.651 ;
     RECT  2.304 19.471 2.826 19.741 ;
     RECT  7.164 19.651 15.426 19.769 ;
     RECT  0.252 19.277 0.27 19.949 ;
     RECT  6.228 19.849 6.246 19.949 ;
     RECT  7.164 19.769 13.842 19.949 ;
     RECT  7.164 19.949 11.718 20.083 ;
     RECT  5.115 19.229 5.397 20.155 ;
     RECT  4.104 19.229 4.23 20.183 ;
     RECT  2.304 19.741 3.33 20.191 ;
     RECT  5.115 20.155 5.454 20.281 ;
     RECT  4.284 20.281 5.454 20.381 ;
     RECT  5.115 20.381 5.454 20.417 ;
     RECT  2.304 20.191 3.546 20.539 ;
     RECT  12.492 19.949 13.842 20.551 ;
     RECT  6.264 20.083 11.718 20.683 ;
     RECT  12.492 20.551 13.914 20.683 ;
     RECT  2.268 20.539 3.546 20.723 ;
     RECT  6.264 20.683 13.914 20.893 ;
     RECT  14.796 19.769 15.426 20.893 ;
     RECT  4.284 20.381 4.302 20.921 ;
     RECT  2.304 20.723 3.546 20.923 ;
     RECT  6.264 20.893 15.426 20.993 ;
     RECT  0.252 20.923 0.27 21.101 ;
     RECT  5.115 20.417 5.418 21.211 ;
     RECT  6.264 20.993 13.914 21.211 ;
     RECT  5.115 21.211 13.914 21.235 ;
     RECT  4.788 21.235 13.914 21.299 ;
     RECT  4.788 21.299 5.397 21.389 ;
     RECT  4.86 21.389 5.397 21.461 ;
     RECT  16.524 20.587 16.542 21.643 ;
     RECT  6.12 21.299 13.914 21.659 ;
     RECT  16.524 21.643 17.082 21.667 ;
     RECT  16.524 21.667 17.154 21.725 ;
     RECT  6.516 21.659 13.914 21.739 ;
     RECT  14.832 20.993 15.426 21.739 ;
     RECT  6.516 21.739 15.426 21.931 ;
     RECT  2.304 20.923 4.014 22.045 ;
     RECT  6.516 21.931 15.462 22.073 ;
     RECT  6.516 22.073 15.066 22.235 ;
     RECT  0.504 21.469 0.558 22.253 ;
     RECT  2.304 22.045 4.05 22.315 ;
     RECT  4.932 21.461 5.397 22.315 ;
     RECT  6.516 22.235 14.85 22.343 ;
     RECT  6.516 22.343 6.534 22.349 ;
     RECT  0.216 22.411 0.234 22.469 ;
     RECT  7.344 22.343 14.85 22.469 ;
     RECT  16.524 21.725 16.65 22.685 ;
     RECT  7.452 22.469 14.85 22.739 ;
     RECT  7.452 22.739 13.986 22.784 ;
     RECT  2.304 22.315 5.397 22.891 ;
     RECT  16.524 22.685 16.614 22.925 ;
     RECT  14.796 22.739 14.85 22.987 ;
     RECT  2.304 22.891 5.454 23.189 ;
     RECT  2.304 23.189 3.402 23.279 ;
     RECT  7.452 22.784 13.842 23.323 ;
     RECT  4.248 23.189 5.454 23.359 ;
     RECT  4.248 23.359 5.706 23.549 ;
     RECT  14.796 22.987 15.426 23.549 ;
     RECT  7.272 23.323 13.842 23.563 ;
     RECT  7.164 23.563 13.842 23.629 ;
     RECT  6.552 23.629 13.842 23.701 ;
     RECT  6.264 23.701 13.842 23.791 ;
     RECT  4.248 23.549 5.397 23.971 ;
     RECT  0.216 23.971 0.234 24.029 ;
     RECT  4.032 23.971 5.397 24.089 ;
     RECT  16.524 22.925 16.542 24.091 ;
     RECT  16.524 24.091 17.082 24.133 ;
     RECT  6.264 23.791 13.878 24.221 ;
     RECT  16.524 24.133 17.154 24.233 ;
     RECT  2.304 23.279 2.697 24.241 ;
     RECT  2.268 24.241 2.697 24.317 ;
     RECT  2.304 24.317 2.697 24.331 ;
     RECT  2.304 24.331 3.186 24.359 ;
     RECT  2.415 24.359 3.186 24.461 ;
     RECT  4.104 24.089 5.397 24.511 ;
     RECT  6.84 24.221 13.878 24.511 ;
     RECT  6.84 24.511 14.058 24.629 ;
     RECT  6.84 24.629 13.914 24.809 ;
     RECT  0.252 24.667 0.27 24.845 ;
     RECT  4.104 24.511 5.922 24.899 ;
     RECT  16.56 24.233 17.154 24.971 ;
     RECT  16.56 24.971 17.082 24.989 ;
     RECT  4.104 24.899 5.49 25.007 ;
     RECT  14.832 23.549 15.426 25.043 ;
     RECT  16.56 24.989 16.578 25.051 ;
     RECT  2.415 24.461 2.862 25.099 ;
     RECT  4.104 25.007 5.397 25.141 ;
     RECT  2.304 25.099 2.862 25.213 ;
     RECT  3.816 25.141 5.397 25.229 ;
     RECT  2.304 25.213 2.934 25.285 ;
     RECT  3.816 25.229 4.338 25.285 ;
     RECT  2.304 25.285 4.338 25.339 ;
     RECT  7.02 24.809 13.914 25.411 ;
     RECT  2.268 25.339 4.338 25.439 ;
     RECT  14.868 25.043 15.426 25.477 ;
     RECT  14.868 25.477 15.462 25.517 ;
     RECT  14.868 25.517 15.426 25.583 ;
     RECT  7.02 25.411 14.13 25.675 ;
     RECT  6.984 25.675 14.13 25.681 ;
     RECT  0.288 25.771 0.306 25.963 ;
     RECT  16.524 25.051 16.578 25.963 ;
     RECT  6.48 25.681 14.13 25.987 ;
     RECT  16.524 25.963 17.082 25.987 ;
     RECT  6.48 25.987 14.85 26.053 ;
     RECT  0.288 25.963 0.45 26.093 ;
     RECT  4.032 25.439 4.338 26.095 ;
     RECT  5.115 25.229 5.397 26.095 ;
     RECT  0.288 26.093 0.378 26.159 ;
     RECT  0.288 26.159 0.306 26.189 ;
     RECT  6.336 26.053 14.85 26.189 ;
     RECT  16.524 25.987 17.154 26.285 ;
     RECT  2.304 25.439 3.222 26.293 ;
     RECT  4.032 26.095 5.397 26.293 ;
     RECT  2.304 26.293 5.397 26.357 ;
     RECT  6.768 26.189 14.85 26.392 ;
     RECT  2.304 26.357 4.194 26.401 ;
     RECT  2.268 26.401 4.194 26.477 ;
     RECT  6.768 26.392 14.886 26.587 ;
     RECT  6.768 26.587 14.994 26.627 ;
     RECT  14.832 26.627 14.994 26.923 ;
     RECT  0.252 26.827 0.27 27.067 ;
     RECT  6.768 26.627 14.058 27.067 ;
     RECT  0.216 27.067 0.27 27.103 ;
     RECT  0.216 27.103 0.342 27.149 ;
     RECT  2.304 26.477 4.194 27.163 ;
     RECT  2.304 27.163 4.374 27.175 ;
     RECT  5.112 26.357 5.397 27.175 ;
     RECT  6.228 27.067 14.058 27.203 ;
     RECT  2.304 27.175 5.397 27.409 ;
     RECT  6.948 27.203 14.058 27.409 ;
     RECT  14.832 26.923 15.426 27.409 ;
     RECT  2.304 27.409 5.454 27.481 ;
     RECT  6.948 27.409 15.426 27.599 ;
     RECT  2.304 27.481 5.526 27.869 ;
     RECT  5.115 27.869 5.526 27.941 ;
     RECT  0.216 27.149 0.234 27.965 ;
     RECT  14.832 27.599 15.426 27.965 ;
     RECT  2.304 27.869 4.374 28.111 ;
     RECT  2.268 28.111 4.374 28.157 ;
     RECT  16.524 26.285 16.542 28.255 ;
     RECT  15.984 28.255 16.542 28.301 ;
     RECT  2.304 28.157 4.374 28.481 ;
     RECT  3.744 28.481 4.374 28.493 ;
     RECT  6.948 27.599 14.058 28.555 ;
     RECT  0.252 28.603 0.27 28.651 ;
     RECT  3.924 28.493 4.374 28.651 ;
     RECT  5.115 27.941 5.397 28.651 ;
     RECT  6.912 28.555 14.058 28.723 ;
     RECT  14.832 27.965 14.922 28.723 ;
     RECT  6.912 28.723 14.922 28.747 ;
     RECT  0.252 28.651 0.414 28.781 ;
     RECT  6.804 28.747 14.922 28.795 ;
     RECT  2.304 28.481 2.697 28.939 ;
     RECT  2.196 28.939 2.697 29.021 ;
     RECT  6.804 28.795 15.426 29.021 ;
     RECT  0.252 28.781 0.342 29.057 ;
     RECT  0.252 29.057 0.27 29.069 ;
     RECT  16.524 28.301 16.542 29.275 ;
     RECT  1.152 29.371 1.17 29.549 ;
     RECT  6.804 29.021 14.85 29.561 ;
     RECT  2.304 29.021 2.697 29.563 ;
     RECT  16.524 29.275 17.154 29.597 ;
     RECT  2.304 29.563 3.186 29.605 ;
     RECT  3.924 28.651 5.397 29.605 ;
     RECT  16.524 29.597 16.614 29.633 ;
     RECT  16.56 29.633 16.614 29.741 ;
     RECT  16.56 29.741 16.578 29.867 ;
     RECT  2.304 29.605 5.397 29.939 ;
     RECT  2.304 29.939 2.898 30.029 ;
     RECT  6.912 29.561 14.85 30.209 ;
     RECT  6.912 30.209 13.95 30.343 ;
     RECT  0.396 30.283 0.414 30.413 ;
     RECT  6.372 30.343 13.95 30.427 ;
     RECT  14.832 30.209 14.85 30.427 ;
     RECT  6.228 30.427 13.95 30.569 ;
     RECT  6.228 30.569 13.914 30.641 ;
     RECT  6.372 30.641 13.914 30.653 ;
     RECT  3.708 29.939 5.397 30.713 ;
     RECT  2.304 30.029 2.697 30.811 ;
     RECT  2.268 30.811 3.546 30.911 ;
     RECT  4.5 30.713 5.397 30.919 ;
     RECT  4.5 30.919 5.454 31.181 ;
     RECT  0.252 31.147 0.27 31.306 ;
     RECT  0.216 31.306 0.306 31.373 ;
     RECT  0.288 31.373 0.306 31.421 ;
     RECT  6.372 30.653 13.734 31.483 ;
     RECT  14.832 30.427 15.426 31.483 ;
     RECT  4.86 31.181 5.454 31.495 ;
     RECT  6.372 31.483 15.426 31.495 ;
     RECT  2.304 30.911 3.546 31.621 ;
     RECT  4.86 31.495 15.426 31.649 ;
     RECT  1.152 31.531 1.17 31.693 ;
     RECT  0.54 31.693 1.17 31.709 ;
     RECT  14.832 31.649 15.426 31.721 ;
     RECT  4.86 31.649 13.77 31.757 ;
     RECT  6.264 31.757 13.77 31.805 ;
     RECT  6.336 31.805 13.77 31.949 ;
     RECT  0.54 31.709 0.558 31.997 ;
     RECT  2.304 31.621 4.014 32.161 ;
     RECT  4.86 31.757 5.397 32.161 ;
     RECT  7.128 31.949 13.77 32.639 ;
     RECT  2.304 32.161 5.397 32.701 ;
     RECT  1.152 32.539 1.17 32.717 ;
     RECT  14.832 31.721 14.922 32.731 ;
     RECT  14.832 32.731 15.426 32.801 ;
     RECT  12.06 32.639 13.77 32.827 ;
     RECT  2.304 32.701 5.454 32.909 ;
     RECT  12.06 32.827 13.842 32.909 ;
     RECT  12.528 32.909 13.842 32.971 ;
     RECT  6.336 31.949 6.354 33.007 ;
     RECT  7.128 32.639 11.322 33.007 ;
     RECT  6.336 33.007 11.322 33.019 ;
     RECT  16.524 32.107 16.542 33.259 ;
     RECT  6.228 33.019 11.322 33.269 ;
     RECT  14.832 32.801 14.85 33.277 ;
     RECT  12.528 32.971 13.914 33.349 ;
     RECT  14.724 33.277 14.85 33.349 ;
     RECT  15.984 33.259 16.542 33.403 ;
     RECT  15.984 33.403 16.578 33.449 ;
     RECT  2.304 32.909 5.397 33.499 ;
     RECT  12.528 33.349 14.85 33.547 ;
     RECT  12.528 33.547 15.426 33.584 ;
     RECT  2.268 33.499 5.397 33.655 ;
     RECT  6.84 33.269 11.322 33.655 ;
     RECT  6.84 33.655 11.718 33.817 ;
     RECT  12.528 33.584 14.058 33.817 ;
     RECT  6.84 33.817 14.058 33.869 ;
     RECT  6.984 33.869 14.058 33.965 ;
     RECT  16.56 33.449 16.578 34.075 ;
     RECT  2.268 33.655 5.634 34.115 ;
     RECT  16.56 34.075 17.082 34.123 ;
     RECT  16.56 34.123 17.154 34.16 ;
     RECT  2.268 34.115 5.397 34.205 ;
     RECT  14.832 33.584 15.426 34.357 ;
     RECT  7.02 33.965 14.058 34.501 ;
     RECT  14.796 34.357 15.426 34.501 ;
     RECT  16.524 34.171 16.542 34.891 ;
     RECT  16.524 34.891 17.082 34.933 ;
     RECT  16.524 34.933 17.154 34.973 ;
     RECT  2.304 34.205 5.397 35.033 ;
     RECT  7.02 34.501 15.426 35.159 ;
     RECT  0.288 34.987 0.306 35.179 ;
     RECT  7.02 35.159 14.058 35.275 ;
     RECT  0.288 35.179 0.414 35.309 ;
     RECT  6.948 35.275 14.058 35.323 ;
     RECT  16.524 34.973 16.542 35.357 ;
     RECT  6.84 35.323 14.058 35.467 ;
     RECT  6.228 35.467 14.058 35.609 ;
     RECT  12.492 35.609 14.058 35.843 ;
     RECT  4.212 35.033 5.397 35.947 ;
     RECT  14.832 35.159 15.426 35.947 ;
     RECT  2.304 35.033 3.402 36.085 ;
     RECT  4.212 35.947 5.49 36.085 ;
     RECT  2.304 36.085 5.49 36.121 ;
     RECT  6.228 35.609 11.718 36.121 ;
     RECT  2.304 36.121 11.718 36.125 ;
     RECT  0.252 35.899 0.27 36.365 ;
     RECT  14.832 35.947 15.462 36.383 ;
     RECT  4.284 36.125 11.718 36.475 ;
     RECT  12.492 35.843 13.914 36.475 ;
     RECT  4.284 36.475 13.914 36.605 ;
     RECT  16.524 36.475 16.542 36.763 ;
     RECT  16.524 36.763 17.082 36.787 ;
     RECT  6.804 36.605 13.914 36.941 ;
     RECT  6.876 36.941 13.914 37.021 ;
     RECT  14.832 36.383 14.85 37.021 ;
     RECT  4.284 36.605 5.922 37.049 ;
     RECT  0.54 36.931 0.558 37.181 ;
     RECT  6.876 37.021 14.85 37.181 ;
     RECT  7.2 37.181 14.85 37.229 ;
     RECT  2.304 36.125 3.51 37.291 ;
     RECT  4.284 37.049 5.742 37.291 ;
     RECT  2.304 37.291 5.742 37.421 ;
     RECT  7.416 37.229 14.85 37.625 ;
     RECT  12.456 37.625 14.85 37.723 ;
     RECT  2.304 37.421 5.526 37.741 ;
     RECT  16.524 36.787 17.154 37.853 ;
     RECT  16.56 37.853 17.154 38.003 ;
     RECT  16.56 38.003 17.082 38.045 ;
     RECT  7.416 37.625 11.682 38.059 ;
     RECT  2.268 37.741 5.526 38.129 ;
     RECT  4.68 38.129 5.526 38.165 ;
     RECT  4.932 38.165 5.526 38.189 ;
     RECT  7.38 38.059 11.682 38.203 ;
     RECT  16.56 38.045 16.614 38.285 ;
     RECT  2.268 38.129 3.654 38.399 ;
     RECT  12.456 37.723 15.426 38.471 ;
     RECT  6.12 38.395 6.138 38.515 ;
     RECT  7.344 38.203 11.682 38.515 ;
     RECT  12.456 38.471 14.958 38.515 ;
     RECT  7.344 38.515 14.958 38.641 ;
     RECT  6.12 38.515 6.21 38.669 ;
     RECT  7.308 38.641 14.958 38.669 ;
     RECT  7.308 38.669 14.886 38.713 ;
     RECT  2.268 38.399 3.402 38.765 ;
     RECT  7.236 38.713 14.886 38.911 ;
     RECT  16.56 38.285 16.578 38.947 ;
     RECT  16.524 38.947 16.578 39.005 ;
     RECT  4.932 38.189 5.397 39.091 ;
     RECT  16.56 39.005 16.578 39.101 ;
     RECT  2.268 38.765 2.862 39.119 ;
     RECT  4.14 39.091 5.397 39.208 ;
     RECT  3.6 39.208 5.397 39.209 ;
     RECT  6.624 38.911 14.886 39.209 ;
     RECT  5.004 39.209 5.397 39.289 ;
     RECT  17.064 39.259 17.082 39.289 ;
     RECT  17.064 39.289 17.154 39.317 ;
     RECT  6.624 39.209 13.842 39.341 ;
     RECT  17.136 39.317 17.154 39.341 ;
     RECT  5.004 39.289 5.814 39.479 ;
     RECT  14.796 39.209 14.886 39.559 ;
     RECT  14.796 39.559 14.958 39.587 ;
     RECT  2.304 39.119 2.862 39.595 ;
     RECT  3.6 39.209 4.014 39.595 ;
     RECT  6.624 39.341 13.734 39.595 ;
     RECT  14.832 39.587 14.958 39.595 ;
     RECT  5.004 39.479 5.598 39.749 ;
     RECT  6.408 39.595 13.734 39.749 ;
     RECT  2.304 39.595 4.014 39.773 ;
     RECT  5.004 39.749 5.397 40.027 ;
     RECT  2.304 39.773 3.978 40.289 ;
     RECT  6.624 39.749 13.734 40.441 ;
     RECT  2.304 40.289 3.294 40.459 ;
     RECT  6.624 40.441 13.914 40.603 ;
     RECT  6.336 40.603 13.914 40.639 ;
     RECT  14.832 39.595 15.426 40.639 ;
     RECT  4.932 40.027 5.397 40.711 ;
     RECT  2.268 40.459 3.294 40.739 ;
     RECT  6.336 40.639 15.426 40.829 ;
     RECT  4.176 40.711 5.397 41.071 ;
     RECT  2.304 40.739 3.294 41.143 ;
     RECT  4.032 41.071 5.397 41.143 ;
     RECT  2.304 41.143 5.397 41.251 ;
     RECT  16.524 40.603 16.542 41.515 ;
     RECT  2.304 41.251 5.454 41.549 ;
     RECT  0.252 41.419 0.27 41.596 ;
     RECT  6.336 40.829 13.842 41.659 ;
     RECT  14.832 40.829 15.426 41.659 ;
     RECT  2.304 41.549 5.397 41.747 ;
     RECT  14.832 41.659 15.462 41.755 ;
     RECT  16.524 41.515 17.154 41.755 ;
     RECT  0.216 41.596 0.306 41.789 ;
     RECT  14.832 41.755 17.154 41.791 ;
     RECT  0.216 41.789 0.27 41.837 ;
     RECT  14.796 41.791 17.154 41.981 ;
     RECT  14.832 41.981 17.154 42.053 ;
     RECT  2.304 41.747 2.754 42.088 ;
     RECT  6.228 41.659 13.842 42.151 ;
     RECT  6.228 42.151 13.914 42.259 ;
     RECT  3.492 41.747 5.397 42.269 ;
     RECT  16.524 42.053 17.154 42.269 ;
     RECT  0.252 41.837 0.27 42.365 ;
     RECT  6.192 42.259 13.914 42.521 ;
     RECT  14.832 42.053 15.462 42.521 ;
     RECT  2.268 42.088 2.754 42.523 ;
     RECT  3.492 42.269 4.05 42.523 ;
     RECT  6.228 42.521 13.914 42.593 ;
     RECT  6.228 42.593 6.246 42.629 ;
     RECT  2.268 42.523 4.05 42.719 ;
     RECT  16.524 42.269 16.542 42.755 ;
     RECT  7.236 42.593 13.914 42.763 ;
     RECT  7.236 42.763 14.022 42.871 ;
     RECT  7.236 42.871 14.058 42.989 ;
     RECT  2.304 42.719 4.05 43.051 ;
     RECT  2.304 43.051 4.086 43.099 ;
     RECT  4.824 42.269 5.397 43.099 ;
     RECT  14.832 42.521 15.426 43.331 ;
     RECT  7.236 42.989 13.914 43.373 ;
     RECT  0.216 43.435 0.234 43.529 ;
     RECT  2.304 43.099 5.397 43.627 ;
     RECT  2.16 43.627 5.397 43.681 ;
     RECT  2.16 43.681 5.922 43.799 ;
     RECT  7.236 43.373 13.734 43.807 ;
     RECT  2.16 43.799 2.697 43.901 ;
     RECT  6.84 43.807 13.734 44.113 ;
     RECT  14.832 43.331 15.066 44.113 ;
     RECT  3.636 43.799 5.397 44.141 ;
     RECT  6.84 44.113 15.066 44.155 ;
     RECT  6.264 44.155 15.066 44.249 ;
     RECT  16.524 43.723 16.542 44.251 ;
     RECT  16.524 44.251 17.082 44.266 ;
     RECT  3.816 44.141 5.397 44.411 ;
     RECT  7.344 44.249 15.066 44.539 ;
     RECT  3.924 44.411 5.397 44.581 ;
     RECT  3.924 44.581 5.742 44.681 ;
     RECT  2.304 43.901 2.697 44.689 ;
     RECT  2.304 44.689 2.862 44.761 ;
     RECT  2.304 44.761 2.934 44.779 ;
     RECT  2.124 44.779 2.934 44.875 ;
     RECT  2.124 44.875 3.042 44.957 ;
     RECT  16.524 44.266 17.154 44.96 ;
     RECT  7.344 44.539 15.426 44.995 ;
     RECT  0.216 44.851 0.234 45.053 ;
     RECT  7.128 44.995 15.426 45.053 ;
     RECT  2.268 44.957 3.042 45.112 ;
     RECT  2.268 45.112 3.114 45.149 ;
     RECT  3.924 44.681 5.397 45.221 ;
     RECT  2.268 45.149 2.934 45.257 ;
     RECT  7.272 45.053 15.426 45.329 ;
     RECT  3.924 45.221 4.302 45.391 ;
     RECT  6.264 45.265 6.282 45.437 ;
     RECT  5.115 45.221 5.397 45.841 ;
     RECT  7.272 45.329 13.842 45.925 ;
     RECT  0.288 45.787 0.306 45.931 ;
     RECT  16.524 44.96 16.578 45.931 ;
     RECT  2.268 45.257 2.697 45.959 ;
     RECT  5.115 45.841 5.454 45.959 ;
     RECT  16.524 45.931 17.082 45.967 ;
     RECT  2.304 45.959 2.697 46.027 ;
     RECT  14.832 45.329 15.426 46.027 ;
     RECT  0.288 45.931 0.414 46.061 ;
     RECT  3.888 45.391 4.302 46.067 ;
     RECT  7.164 45.925 13.842 46.075 ;
     RECT  16.524 45.967 17.154 46.103 ;
     RECT  6.732 46.075 13.842 46.201 ;
     RECT  2.304 46.027 2.862 46.229 ;
     RECT  2.304 46.229 2.754 46.253 ;
     RECT  3.996 46.067 4.302 46.273 ;
     RECT  3.996 46.273 4.338 46.363 ;
     RECT  5.115 45.959 5.397 46.363 ;
     RECT  6.732 46.201 13.914 46.381 ;
     RECT  14.832 46.027 15.462 46.381 ;
     RECT  6.732 46.381 15.462 46.571 ;
     RECT  6.732 46.571 14.922 46.607 ;
     RECT  3.996 46.363 5.397 46.813 ;
     RECT  15.948 46.651 16.002 46.877 ;
     RECT  3.996 46.813 5.886 46.921 ;
     RECT  6.732 46.607 13.914 46.921 ;
     RECT  3.996 46.921 13.914 47.035 ;
     RECT  17.064 46.103 17.154 47.035 ;
     RECT  16.524 47.035 17.154 47.111 ;
     RECT  3.42 47.035 13.914 47.183 ;
     RECT  3.42 47.183 5.814 47.219 ;
     RECT  2.304 46.253 2.697 47.371 ;
     RECT  3.42 47.219 5.742 47.371 ;
     RECT  17.064 47.111 17.154 47.381 ;
     RECT  17.064 47.381 17.082 47.405 ;
     RECT  2.304 47.371 5.742 47.417 ;
     RECT  6.732 47.183 13.914 47.461 ;
     RECT  14.832 46.607 14.922 47.467 ;
     RECT  6.732 47.461 14.022 47.695 ;
     RECT  14.832 47.467 15.426 47.695 ;
     RECT  2.304 47.417 5.526 47.849 ;
     RECT  6.732 47.695 15.426 47.857 ;
     RECT  0.54 47.821 0.558 47.933 ;
     RECT  6.732 47.857 16.002 47.933 ;
     RECT  2.304 47.849 5.397 48.085 ;
     RECT  6.732 47.933 15.426 48.163 ;
     RECT  2.268 48.085 5.397 48.389 ;
     RECT  6.588 48.163 15.426 48.389 ;
     RECT  17.064 48.379 17.082 48.397 ;
     RECT  5.115 48.389 5.397 48.703 ;
     RECT  14.832 48.389 15.426 48.749 ;
     RECT  14.832 48.749 14.958 48.845 ;
     RECT  6.696 48.389 14.058 48.929 ;
     RECT  17.064 48.397 17.154 49.001 ;
     RECT  17.064 49.001 17.082 49.037 ;
     RECT  16.56 49.081 16.578 49.147 ;
     RECT  2.268 48.389 4.338 49.171 ;
     RECT  5.115 48.703 5.49 49.171 ;
     RECT  2.268 49.171 5.49 49.181 ;
     RECT  6.696 48.929 13.662 49.195 ;
     RECT  2.304 49.181 5.49 49.243 ;
     RECT  6.228 49.195 13.662 49.243 ;
     RECT  16.524 49.147 16.578 49.277 ;
     RECT  2.304 49.243 13.662 49.379 ;
     RECT  2.304 49.379 5.397 49.469 ;
     RECT  16.524 49.277 16.542 49.477 ;
     RECT  6.264 49.379 13.662 49.517 ;
     RECT  16.488 49.477 16.542 49.565 ;
     RECT  0.54 49.549 0.558 49.613 ;
     RECT  6.264 49.517 12.186 49.613 ;
     RECT  12.924 49.517 13.662 49.613 ;
     RECT  14.832 48.845 14.85 49.771 ;
     RECT  16.524 49.565 16.542 49.847 ;
     RECT  6.48 49.613 12.186 49.901 ;
     RECT  2.304 49.469 4.338 50.117 ;
     RECT  14.832 49.771 14.922 50.155 ;
     RECT  0.396 50.203 0.414 50.333 ;
     RECT  3.6 50.117 4.338 50.333 ;
     RECT  7.38 49.901 12.186 50.395 ;
     RECT  12.924 49.613 13.497 50.395 ;
     RECT  1.152 49.675 1.278 50.429 ;
     RECT  3.888 50.333 4.338 50.431 ;
     RECT  5.115 49.469 5.397 50.431 ;
     RECT  14.832 50.155 15.426 50.431 ;
     RECT  17.064 50.491 17.082 50.521 ;
     RECT  0.216 50.476 0.306 50.525 ;
     RECT  0.288 50.525 0.306 50.573 ;
     RECT  17.064 50.521 17.154 50.573 ;
     RECT  6.48 49.901 6.57 50.665 ;
     RECT  7.38 50.395 13.497 50.665 ;
     RECT  1.152 50.429 1.17 50.669 ;
     RECT  3.888 50.431 5.397 50.669 ;
     RECT  6.48 50.665 13.497 50.791 ;
     RECT  14.508 50.431 15.426 50.791 ;
     RECT  6.48 50.791 15.426 50.971 ;
     RECT  5.115 50.669 5.397 51.019 ;
     RECT  5.115 51.019 5.49 51.089 ;
     RECT  2.304 50.117 2.862 51.115 ;
     RECT  3.888 50.669 4.266 51.115 ;
     RECT  6.336 50.971 15.426 51.293 ;
     RECT  6.696 51.293 15.426 51.437 ;
     RECT  16.524 50.587 16.578 51.451 ;
     RECT  2.304 51.115 4.266 51.503 ;
     RECT  3.672 51.503 4.266 51.643 ;
     RECT  5.115 51.089 5.454 51.643 ;
     RECT  3.672 51.643 5.454 51.943 ;
     RECT  3.672 51.943 5.922 52.141 ;
     RECT  6.696 51.437 14.094 52.141 ;
     RECT  14.832 51.437 14.886 52.213 ;
     RECT  2.304 51.503 2.826 52.249 ;
     RECT  3.672 52.141 14.094 52.249 ;
     RECT  2.304 52.249 14.094 52.439 ;
     RECT  6.3 52.439 14.094 52.717 ;
     RECT  14.832 52.213 14.958 52.717 ;
     RECT  6.3 52.717 14.958 52.789 ;
     RECT  6.3 52.789 15.462 52.889 ;
     RECT  6.3 52.889 11.574 53.015 ;
     RECT  12.564 52.889 15.462 53.117 ;
     RECT  6.516 53.015 11.574 53.123 ;
     RECT  6.624 53.123 11.574 53.261 ;
     RECT  2.304 52.439 5.397 53.293 ;
     RECT  2.304 53.293 5.454 53.323 ;
     RECT  2.304 53.323 5.706 53.519 ;
     RECT  16.524 51.451 17.154 53.597 ;
     RECT  6.768 53.261 11.574 53.671 ;
     RECT  12.564 53.117 14.922 53.671 ;
     RECT  5.115 53.519 5.706 53.761 ;
     RECT  0.54 52.141 0.558 53.837 ;
     RECT  17.064 53.597 17.154 53.861 ;
     RECT  17.136 53.861 17.154 53.885 ;
     RECT  5.115 53.761 5.742 53.897 ;
     RECT  6.768 53.671 14.922 53.899 ;
     RECT  2.304 53.519 4.338 54.059 ;
     RECT  6.768 53.899 15.426 54.059 ;
     RECT  6.768 54.059 13.842 54.125 ;
     RECT  6.768 54.125 13.806 54.301 ;
     RECT  6.336 54.301 13.806 54.401 ;
     RECT  6.336 54.401 11.43 54.599 ;
     RECT  0.216 54.031 0.306 54.643 ;
     RECT  0.216 54.643 0.342 54.671 ;
     RECT  14.832 54.059 15.426 54.671 ;
     RECT  0.324 54.671 0.342 54.701 ;
     RECT  5.115 53.897 5.397 54.751 ;
     RECT  6.336 54.599 11.25 54.751 ;
     RECT  5.115 54.751 11.25 54.977 ;
     RECT  2.304 54.059 4.158 55.021 ;
     RECT  12.168 54.401 13.806 55.021 ;
     RECT  5.115 54.977 11.214 55.139 ;
     RECT  2.304 55.021 4.302 55.381 ;
     RECT  5.115 55.139 5.397 55.381 ;
     RECT  1.152 55.339 1.17 55.469 ;
     RECT  2.304 55.381 5.397 55.469 ;
     RECT  6.336 55.139 11.214 55.517 ;
     RECT  12.168 55.021 13.842 55.531 ;
     RECT  11.988 55.531 13.842 55.561 ;
     RECT  14.832 54.671 14.958 55.963 ;
     RECT  0.54 55.723 0.558 55.997 ;
     RECT  2.304 55.469 4.05 56.191 ;
     RECT  2.268 56.191 4.05 56.237 ;
     RECT  14.832 55.963 15.426 56.291 ;
     RECT  7.308 55.517 11.106 56.299 ;
     RECT  11.988 55.561 13.878 56.299 ;
     RECT  6.336 55.517 6.39 56.335 ;
     RECT  2.304 56.237 4.05 56.461 ;
     RECT  5.115 55.469 5.397 56.461 ;
     RECT  7.308 56.299 13.878 56.461 ;
     RECT  7.272 56.461 13.878 56.491 ;
     RECT  16.524 54.715 16.542 56.491 ;
     RECT  2.304 56.461 5.526 56.497 ;
     RECT  6.3 56.335 6.39 56.497 ;
     RECT  16.524 56.491 17.082 56.533 ;
     RECT  7.272 56.491 14.058 56.569 ;
     RECT  2.304 56.497 6.39 56.731 ;
     RECT  7.272 56.569 14.13 56.731 ;
     RECT  2.304 56.731 14.13 56.759 ;
     RECT  14.868 56.291 15.426 56.831 ;
     RECT  16.524 56.533 17.154 56.939 ;
     RECT  16.524 56.939 17.082 56.957 ;
     RECT  1.152 56.683 1.17 57.211 ;
     RECT  1.152 57.211 1.278 57.341 ;
     RECT  16.524 56.957 16.578 57.407 ;
     RECT  1.152 57.341 1.17 57.437 ;
     RECT  2.304 56.759 14.058 57.569 ;
     RECT  16.56 57.407 16.578 57.605 ;
     RECT  14.868 56.831 14.994 57.643 ;
     RECT  14.868 57.643 15.426 57.739 ;
     RECT  14.832 57.739 15.426 57.835 ;
     RECT  14.832 57.835 15.462 57.883 ;
     RECT  14.616 57.883 15.462 57.983 ;
     RECT  0.54 57.991 0.558 58.205 ;
     RECT  2.304 57.569 13.842 58.423 ;
     RECT  14.616 57.983 15.426 58.423 ;
     RECT  0.396 58.363 0.414 58.459 ;
     RECT  0.216 58.459 0.414 58.493 ;
     RECT  16.524 58.267 16.542 58.507 ;
     RECT  0.216 58.493 0.342 58.523 ;
     RECT  16.524 58.507 17.154 58.523 ;
     RECT  0.252 58.523 0.342 58.829 ;
     RECT  0.324 58.829 0.342 58.925 ;
     RECT  17.064 58.523 17.154 58.991 ;
     RECT  17.064 58.991 17.082 59.021 ;
     RECT  2.304 58.423 15.426 59.063 ;
     RECT  2.304 59.063 13.914 59.225 ;
     RECT  14.832 59.063 15.426 59.503 ;
     RECT  1.26 59.419 1.278 59.515 ;
     RECT  1.152 59.515 1.278 59.549 ;
     RECT  2.304 59.225 6.246 59.549 ;
     RECT  14.832 59.503 15.462 59.549 ;
     RECT  1.152 59.549 1.242 59.693 ;
     RECT  16.524 59.707 16.542 59.765 ;
     RECT  1.224 59.693 1.242 59.789 ;
     RECT  2.304 59.549 4.266 59.789 ;
     RECT  14.832 59.549 15.426 59.899 ;
     RECT  7.344 59.225 13.914 59.971 ;
     RECT  14.796 59.899 15.426 59.971 ;
     RECT  7.344 59.971 15.426 59.995 ;
     RECT  2.304 59.789 3.654 59.999 ;
     RECT  5.004 59.549 6.246 60.071 ;
     RECT  0.252 59.899 0.27 60.091 ;
     RECT  0.252 60.091 0.378 60.139 ;
     RECT  7.056 59.995 15.426 60.241 ;
     RECT  2.415 59.999 3.654 60.269 ;
     RECT  5.004 60.071 6.138 60.269 ;
     RECT  6.984 60.241 15.426 60.269 ;
     RECT  6.984 60.269 11.718 60.305 ;
     RECT  12.6 60.269 13.914 60.305 ;
     RECT  0.252 60.139 0.45 60.313 ;
     RECT  6.984 60.305 9.126 60.317 ;
     RECT  5.004 60.269 5.922 60.331 ;
     RECT  6.984 60.317 8.73 60.341 ;
     RECT  10.08 60.305 11.358 60.341 ;
     RECT  0.216 60.313 0.45 60.365 ;
     RECT  14.832 60.269 15.426 60.365 ;
     RECT  2.415 60.269 3.402 60.377 ;
     RECT  4.5 60.331 5.922 60.377 ;
     RECT  0.432 60.365 0.45 60.413 ;
     RECT  2.415 60.377 3.222 60.413 ;
     RECT  14.832 60.365 14.922 60.413 ;
     RECT  2.415 60.413 3.114 60.497 ;
     RECT  5.115 60.377 5.922 60.497 ;
     RECT  6.984 60.341 8.478 60.497 ;
     RECT  3.096 60.497 3.114 60.539 ;
     RECT  13.104 60.305 13.914 60.539 ;
     RECT  14.904 60.413 14.922 60.557 ;
     RECT  6.984 60.497 7.686 60.575 ;
     RECT  10.08 60.341 11.178 60.575 ;
     RECT  13.104 60.539 13.41 60.575 ;
     RECT  6.984 60.575 7.434 60.605 ;
     RECT  8.46 60.497 8.478 60.605 ;
     RECT  7.344 60.605 7.434 60.647 ;
     RECT  10.08 60.575 10.71 60.647 ;
     RECT  7.416 60.647 7.434 60.653 ;
     RECT  10.692 60.647 10.71 60.653 ;
     RECT  5.904 60.497 5.922 61.579 ;
     RECT  5.4 61.579 5.922 62.508 ;
     RECT  5.904 62.508 5.922 62.525 ;
    LAYER M4 ;
     RECT  0.156 2.208 0.205 60.456 ;
     RECT  0.205 2.064 0.515 60.456 ;
     RECT  0.515 2.064 2.408 60.408 ;
     RECT  2.408 2.064 2.512 60.492 ;
     RECT  2.512 2.064 2.837 60.408 ;
     RECT  2.837 40.848 3.233 60.408 ;
     RECT  3.233 40.848 3.377 60.312 ;
     RECT  3.377 40.848 3.413 60.12 ;
     RECT  2.837 2.064 3.701 39.864 ;
     RECT  3.701 2.496 3.805 39.864 ;
     RECT  3.413 40.848 3.805 59.88 ;
     RECT  3.805 2.496 4.025 59.88 ;
     RECT  4.025 2.496 4.133 31.416 ;
     RECT  4.025 52.752 4.489 59.88 ;
     RECT  4.133 2.736 5.108 31.416 ;
     RECT  4.025 32.544 5.108 51.768 ;
     RECT  4.489 52.752 5.108 60.36 ;
     RECT  5.108 2.148 5.212 60.492 ;
     RECT  5.212 2.418 5.404 60.36 ;
     RECT  5.389 61.584 5.603 61.608 ;
     RECT  5.404 44.112 6.793 54.984 ;
     RECT  5.404 56.016 6.793 60.36 ;
     RECT  5.404 2.832 6.829 43.128 ;
     RECT  6.793 44.112 6.973 60.36 ;
     RECT  6.829 2.544 7.225 43.128 ;
     RECT  6.973 44.112 7.225 60.6 ;
     RECT  7.225 2.544 7.405 60.6 ;
     RECT  7.405 2.544 7.657 60.648 ;
     RECT  7.657 2.496 7.808 60.648 ;
     RECT  7.808 2.148 7.912 60.648 ;
     RECT  7.912 2.418 8.104 60.648 ;
     RECT  8.104 2.496 9.205 60.648 ;
     RECT  9.205 2.4 10.508 60.648 ;
     RECT  10.508 2.148 10.612 60.648 ;
     RECT  10.612 2.418 10.721 60.648 ;
     RECT  10.721 2.418 10.804 60.552 ;
     RECT  5.893 62.496 11.413 62.52 ;
     RECT  11.413 62.4 11.459 62.52 ;
     RECT  11.459 62.4 11.891 62.424 ;
     RECT  10.804 2.544 12.197 60.552 ;
     RECT  12.197 2.784 13.208 60.552 ;
     RECT  13.208 2.148 13.312 60.552 ;
     RECT  13.312 2.418 13.504 60.552 ;
     RECT  13.504 2.784 14.821 60.552 ;
     RECT  14.821 2.304 14.933 60.552 ;
     RECT  14.933 2.304 16.513 60.456 ;
     RECT  16.513 2.208 17.1 60.456 ;
     RECT  17.1 2.784 17.165 4.152 ;
     RECT  17.1 6.096 17.165 6.12 ;
     RECT  17.1 7.488 17.165 7.512 ;
     RECT  17.1 8.736 17.165 9.048 ;
     RECT  17.1 10.176 17.165 10.92 ;
     RECT  17.1 12.048 17.165 12.264 ;
     RECT  17.1 13.68 17.165 15.048 ;
     RECT  17.1 17.328 17.165 17.352 ;
     RECT  17.1 21.696 17.165 21.72 ;
     RECT  17.1 24.144 17.165 24.936 ;
     RECT  17.1 26.016 17.165 26.28 ;
     RECT  17.1 29.28 17.165 29.592 ;
     RECT  17.1 34.128 17.165 34.968 ;
     RECT  17.1 36.816 17.165 37.992 ;
     RECT  17.1 39.312 17.165 39.336 ;
     RECT  17.1 41.52 17.165 42.264 ;
     RECT  17.1 44.304 17.165 44.952 ;
     RECT  17.1 45.984 17.165 47.352 ;
     RECT  17.1 48.432 17.165 48.984 ;
     RECT  17.1 50.544 17.165 53.88 ;
     RECT  17.1 56.544 17.165 56.904 ;
     RECT  17.1 58.512 17.165 58.968 ;
    LAYER M5 ;
     RECT  2.4 2.137 2.52 2.151 ;
     RECT  5.1 2.137 5.22 2.151 ;
     RECT  7.8 2.137 7.92 2.151 ;
     RECT  10.5 2.137 10.62 2.151 ;
     RECT  13.2 2.137 13.32 2.151 ;
     RECT  2.4 2.151 2.712 2.485 ;
     RECT  2.304 2.485 2.712 2.627 ;
     RECT  10.5 2.151 10.812 2.677 ;
     RECT  10.5 2.677 11.064 4.213 ;
     RECT  10.5 4.213 11.16 4.499 ;
     RECT  7.8 2.151 8.112 4.597 ;
     RECT  7.8 4.597 9.096 4.883 ;
     RECT  9.216 4.885 9.24 5.029 ;
     RECT  10.5 4.499 11.064 5.029 ;
     RECT  9.216 5.029 11.064 5.075 ;
     RECT  7.8 4.883 8.232 5.173 ;
     RECT  7.536 5.173 8.232 5.411 ;
     RECT  10.128 5.075 11.064 5.411 ;
     RECT  7.8 5.411 8.232 5.555 ;
     RECT  10.5 5.411 11.064 5.699 ;
     RECT  13.2 2.151 13.512 5.701 ;
     RECT  9.12 6.229 9.336 6.371 ;
     RECT  13.2 5.701 13.608 6.613 ;
     RECT  9.12 6.371 9.144 6.851 ;
     RECT  13.2 6.613 13.848 6.851 ;
     RECT  7.8 5.555 8.112 6.853 ;
     RECT  7.8 6.853 9.048 7.379 ;
     RECT  10.5 5.699 10.812 7.717 ;
     RECT  10.368 7.717 10.812 8.771 ;
     RECT  14.832 9.445 14.856 9.683 ;
     RECT  7.8 7.379 8.856 10.789 ;
     RECT  7.8 10.789 9.096 12.565 ;
     RECT  13.2 6.851 13.512 12.757 ;
     RECT  13.2 12.757 13.944 12.899 ;
     RECT  10.5 8.771 10.812 12.901 ;
     RECT  7.8 12.565 9.144 12.995 ;
     RECT  7.8 12.995 9.096 14.197 ;
     RECT  10.176 12.901 10.812 14.197 ;
     RECT  7.8 14.197 11.016 14.387 ;
     RECT  7.8 14.387 9.432 15.443 ;
     RECT  13.2 12.899 13.512 16.453 ;
     RECT  13.2 16.453 13.608 16.643 ;
     RECT  7.8 15.443 9.096 16.693 ;
     RECT  10.5 14.387 11.016 16.693 ;
     RECT  7.632 16.693 11.016 16.837 ;
     RECT  7.632 16.837 11.208 16.883 ;
     RECT  7.8 16.883 11.208 17.123 ;
     RECT  10.368 17.123 11.208 17.219 ;
     RECT  7.8 17.123 9.096 19.909 ;
     RECT  10.368 17.219 10.812 19.909 ;
     RECT  7.632 19.909 9.096 20.389 ;
     RECT  10.368 19.909 11.64 20.483 ;
     RECT  14.832 20.245 14.856 20.483 ;
     RECT  7.632 20.389 9.144 20.531 ;
     RECT  10.5 20.483 11.64 20.677 ;
     RECT  13.2 16.643 13.512 20.677 ;
     RECT  7.632 20.531 9.096 20.867 ;
     RECT  10.5 20.677 11.736 21.011 ;
     RECT  7.8 20.867 9.096 21.685 ;
     RECT  10.5 21.011 11.64 21.685 ;
     RECT  13.2 20.677 13.656 21.781 ;
     RECT  13.2 21.781 13.944 21.973 ;
     RECT  13.2 21.973 14.856 22.067 ;
     RECT  14.832 22.067 14.856 22.163 ;
     RECT  7.8 21.685 11.64 23.123 ;
     RECT  9.792 23.123 11.64 23.893 ;
     RECT  13.2 22.067 13.512 23.893 ;
     RECT  9.792 23.893 13.512 25.187 ;
     RECT  7.8 23.123 8.808 25.715 ;
     RECT  9.792 25.187 11.64 26.243 ;
     RECT  9.792 26.243 11.592 26.437 ;
     RECT  9.12 26.437 11.592 26.723 ;
     RECT  14.832 26.533 14.856 26.723 ;
     RECT  9.792 26.723 11.592 28.019 ;
     RECT  6.432 23.653 6.456 29.461 ;
     RECT  7.8 25.715 8.112 29.461 ;
     RECT  6.432 29.461 8.112 29.507 ;
     RECT  9.792 28.019 10.812 30.517 ;
     RECT  0.288 30.373 0.312 30.563 ;
     RECT  6.864 29.507 8.112 30.757 ;
     RECT  9.12 30.517 10.812 30.757 ;
     RECT  6.864 30.757 10.812 30.851 ;
     RECT  7.8 30.851 10.812 30.947 ;
     RECT  9.792 30.947 10.812 31.427 ;
     RECT  5.1 2.151 5.412 31.429 ;
     RECT  7.8 30.947 8.376 31.909 ;
     RECT  7.056 31.909 8.376 32.531 ;
     RECT  13.2 25.187 13.512 32.581 ;
     RECT  13.2 32.581 13.944 32.867 ;
     RECT  13.2 32.867 13.512 34.405 ;
     RECT  13.2 34.405 13.944 34.549 ;
     RECT  13.2 34.549 14.856 34.691 ;
     RECT  13.2 34.691 13.944 34.739 ;
     RECT  9.936 31.427 10.812 35.269 ;
     RECT  12.048 35.125 12.072 35.269 ;
     RECT  9.936 35.269 12.072 35.315 ;
     RECT  7.056 32.531 8.112 35.411 ;
     RECT  14.832 35.749 14.856 35.939 ;
     RECT  9.936 35.315 11.4 36.133 ;
     RECT  13.2 34.739 13.512 36.229 ;
     RECT  9.12 36.133 11.4 36.275 ;
     RECT  13.2 36.229 13.848 36.371 ;
     RECT  7.8 35.411 8.112 36.421 ;
     RECT  9.936 36.275 11.4 36.565 ;
     RECT  9.936 36.565 11.592 36.613 ;
     RECT  9.936 36.613 11.784 36.947 ;
     RECT  9.936 36.947 11.496 37.333 ;
     RECT  9.12 37.333 11.496 37.955 ;
     RECT  9.936 37.955 11.496 38.003 ;
     RECT  9.936 38.003 11.4 38.387 ;
     RECT  9.936 38.387 10.812 39.109 ;
     RECT  9.12 39.109 10.812 39.251 ;
     RECT  5.1 31.429 5.592 39.253 ;
     RECT  6.96 36.421 8.112 39.253 ;
     RECT  5.1 39.253 8.112 39.299 ;
     RECT  9.936 39.251 10.812 39.541 ;
     RECT  7.8 39.299 8.112 39.925 ;
     RECT  7.8 39.925 8.232 40.211 ;
     RECT  9.936 39.541 11.16 40.309 ;
     RECT  9.936 40.309 11.784 40.451 ;
     RECT  7.8 40.211 8.112 40.453 ;
     RECT  7.68 40.453 8.112 40.979 ;
     RECT  9.936 40.451 11.208 41.461 ;
     RECT  13.2 36.371 13.512 41.749 ;
     RECT  13.2 41.749 13.944 42.565 ;
     RECT  13.2 42.565 14.04 42.755 ;
     RECT  9.84 41.461 11.208 42.851 ;
     RECT  9.84 42.851 10.812 44.483 ;
     RECT  13.2 42.755 13.512 44.677 ;
     RECT  13.2 44.677 13.944 44.915 ;
     RECT  7.8 40.979 8.112 45.061 ;
     RECT  10.32 44.483 10.812 45.253 ;
     RECT  7.8 45.061 8.712 45.301 ;
     RECT  7.8 45.301 9.096 45.443 ;
     RECT  10.32 45.253 10.92 46.211 ;
     RECT  9.12 46.357 9.144 47.123 ;
     RECT  13.2 44.915 13.512 47.365 ;
     RECT  12.768 47.365 13.512 47.605 ;
     RECT  12.672 47.605 13.512 47.747 ;
     RECT  14.832 47.989 14.856 48.227 ;
     RECT  10.32 46.211 10.812 48.421 ;
     RECT  10.32 48.421 11.448 48.709 ;
     RECT  2.4 2.627 2.712 48.757 ;
     RECT  10.32 48.709 12.168 48.805 ;
     RECT  13.2 47.747 13.512 48.805 ;
     RECT  7.8 45.443 8.112 48.853 ;
     RECT  9.12 48.613 9.144 48.853 ;
     RECT  2.304 48.757 2.712 48.947 ;
     RECT  10.32 48.805 13.512 48.995 ;
     RECT  7.8 48.853 9.144 49.043 ;
     RECT  7.8 49.043 8.856 49.955 ;
     RECT  10.32 48.995 11.448 50.051 ;
     RECT  0.288 50.293 0.312 50.483 ;
     RECT  12.528 48.995 13.512 50.915 ;
     RECT  7.8 49.955 8.112 51.253 ;
     RECT  7.8 51.253 8.76 51.395 ;
     RECT  7.8 51.395 8.328 52.405 ;
     RECT  13.2 50.915 13.512 52.501 ;
     RECT  7.8 52.405 8.52 52.885 ;
     RECT  12.576 52.501 13.512 53.027 ;
     RECT  7.8 52.885 9.096 53.557 ;
     RECT  10.32 50.051 10.812 53.557 ;
     RECT  7.8 53.557 10.812 53.939 ;
     RECT  14.832 54.373 14.856 54.563 ;
     RECT  10.224 53.939 10.812 54.755 ;
     RECT  7.8 53.939 9.096 55.907 ;
     RECT  10.5 54.755 10.812 56.293 ;
     RECT  7.8 55.907 9.048 56.387 ;
     RECT  14.832 57.109 14.856 57.587 ;
     RECT  10.5 56.293 10.968 58.933 ;
     RECT  10.5 58.933 11.928 59.125 ;
     RECT  10.5 59.125 12.024 59.267 ;
     RECT  5.1 39.299 6.552 59.891 ;
     RECT  10.5 59.267 11.016 60.275 ;
     RECT  0.48 60.325 0.504 60.467 ;
     RECT  2.4 48.947 2.712 60.489 ;
     RECT  7.8 56.387 8.112 60.489 ;
     RECT  10.5 60.275 10.812 60.489 ;
     RECT  13.2 53.027 13.512 60.489 ;
     RECT  2.4 60.489 2.52 60.503 ;
     RECT  5.1 59.891 5.592 60.503 ;
     RECT  7.8 60.489 7.92 60.503 ;
     RECT  10.5 60.489 10.62 60.503 ;
     RECT  13.2 60.489 13.32 60.503 ;
     RECT  5.568 60.503 5.592 61.619 ;
     RECT  11.424 62.389 11.88 62.48 ;
     RECT  11.424 62.48 11.448 62.531 ;
  END
END dsfd_dvrly_562_EW
END LIBRARY
